VERSION 5.7 ;
  NOWIREEXTENSIONATPIN ON ;
  DIVIDERCHAR "/" ;
  BUSBITCHARS "[]" ;
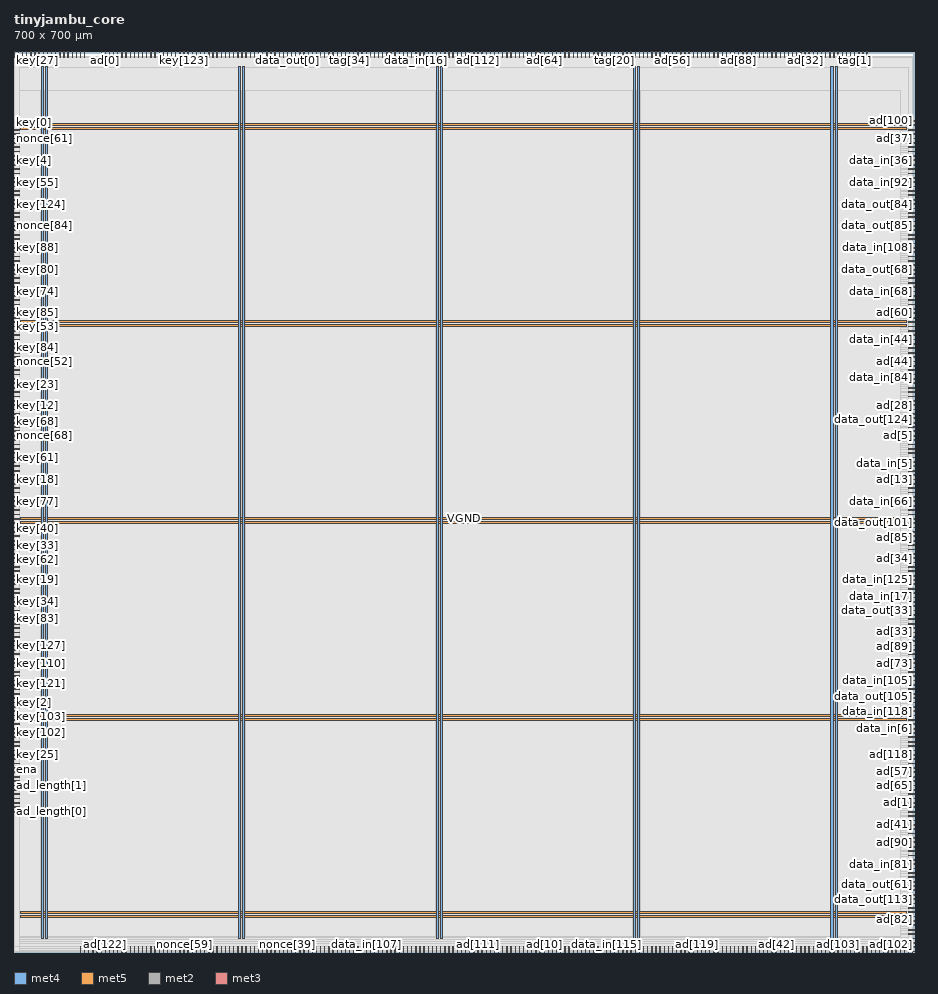
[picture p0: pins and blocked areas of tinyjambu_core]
MACRO tinyjambu_core
  CLASS BLOCK ;
  FOREIGN tinyjambu_core ;
  ORIGIN 0.000 0.000 ;
  SIZE 700.000 BY 700.000 ;
  PIN VGND
    DIRECTION INOUT ;
    USE GROUND ;
    PORT
      LAYER met4 ;
        RECT 24.340 10.640 25.940 688.400 ;
    END
    PORT
      LAYER met4 ;
        RECT 177.940 10.640 179.540 688.400 ;
    END
    PORT
      LAYER met4 ;
        RECT 331.540 10.640 333.140 688.400 ;
    END
    PORT
      LAYER met4 ;
        RECT 485.140 10.640 486.740 688.400 ;
    END
    PORT
      LAYER met4 ;
        RECT 638.740 10.640 640.340 688.400 ;
    END
    PORT
      LAYER met5 ;
        RECT 5.280 30.030 694.380 31.630 ;
    END
    PORT
      LAYER met5 ;
        RECT 5.280 183.210 694.380 184.810 ;
    END
    PORT
      LAYER met5 ;
        RECT 5.280 336.390 694.380 337.990 ;
    END
    PORT
      LAYER met5 ;
        RECT 5.280 489.570 694.380 491.170 ;
    END
    PORT
      LAYER met5 ;
        RECT 5.280 642.750 694.380 644.350 ;
    END
  END VGND
  PIN VPWR
    DIRECTION INOUT ;
    USE POWER ;
    PORT
      LAYER met4 ;
        RECT 21.040 10.640 22.640 688.400 ;
    END
    PORT
      LAYER met4 ;
        RECT 174.640 10.640 176.240 688.400 ;
    END
    PORT
      LAYER met4 ;
        RECT 328.240 10.640 329.840 688.400 ;
    END
    PORT
      LAYER met4 ;
        RECT 481.840 10.640 483.440 688.400 ;
    END
    PORT
      LAYER met4 ;
        RECT 635.440 10.640 637.040 688.400 ;
    END
    PORT
      LAYER met5 ;
        RECT 5.280 26.730 694.380 28.330 ;
    END
    PORT
      LAYER met5 ;
        RECT 5.280 179.910 694.380 181.510 ;
    END
    PORT
      LAYER met5 ;
        RECT 5.280 333.090 694.380 334.690 ;
    END
    PORT
      LAYER met5 ;
        RECT 5.280 486.270 694.380 487.870 ;
    END
    PORT
      LAYER met5 ;
        RECT 5.280 639.450 694.380 641.050 ;
    END
  END VPWR
  PIN ad[0]
    DIRECTION INPUT ;
    USE SIGNAL ;
    ANTENNAGATEAREA 0.213000 ;
    PORT
      LAYER met2 ;
        RECT 70.930 696.000 71.210 700.000 ;
    END
  END ad[0]
  PIN ad[100]
    DIRECTION INPUT ;
    USE SIGNAL ;
    ANTENNAGATEAREA 0.196500 ;
    PORT
      LAYER met3 ;
        RECT 696.000 646.040 700.000 646.640 ;
    END
  END ad[100]
  PIN ad[101]
    DIRECTION INPUT ;
    USE SIGNAL ;
    ANTENNAGATEAREA 0.196500 ;
    PORT
      LAYER met3 ;
        RECT 696.000 326.440 700.000 327.040 ;
    END
  END ad[101]
  PIN ad[102]
    DIRECTION INPUT ;
    USE SIGNAL ;
    ANTENNAGATEAREA 0.196500 ;
    PORT
      LAYER met2 ;
        RECT 685.950 0.000 686.230 4.000 ;
    END
  END ad[102]
  PIN ad[103]
    DIRECTION INPUT ;
    USE SIGNAL ;
    ANTENNAGATEAREA 0.213000 ;
    PORT
      LAYER met2 ;
        RECT 640.870 0.000 641.150 4.000 ;
    END
  END ad[103]
  PIN ad[104]
    DIRECTION INPUT ;
    USE SIGNAL ;
    ANTENNAGATEAREA 0.213000 ;
    PORT
      LAYER met2 ;
        RECT 663.410 696.000 663.690 700.000 ;
    END
  END ad[104]
  PIN ad[105]
    DIRECTION INPUT ;
    USE SIGNAL ;
    ANTENNAGATEAREA 0.213000 ;
    PORT
      LAYER met3 ;
        RECT 696.000 0.040 700.000 0.640 ;
    END
  END ad[105]
  PIN ad[106]
    DIRECTION INPUT ;
    USE SIGNAL ;
    ANTENNAGATEAREA 0.126000 ;
    PORT
      LAYER met3 ;
        RECT 696.000 71.440 700.000 72.040 ;
    END
  END ad[106]
  PIN ad[107]
    DIRECTION INPUT ;
    USE SIGNAL ;
    ANTENNAGATEAREA 0.213000 ;
    PORT
      LAYER met2 ;
        RECT 51.610 0.000 51.890 4.000 ;
    END
  END ad[107]
  PIN ad[108]
    DIRECTION INPUT ;
    USE SIGNAL ;
    ANTENNAGATEAREA 0.196500 ;
    PORT
      LAYER met3 ;
        RECT 696.000 618.840 700.000 619.440 ;
    END
  END ad[108]
  PIN ad[109]
    DIRECTION INPUT ;
    USE SIGNAL ;
    ANTENNAGATEAREA 0.196500 ;
    PORT
      LAYER met3 ;
        RECT 696.000 319.640 700.000 320.240 ;
    END
  END ad[109]
  PIN ad[10]
    DIRECTION INPUT ;
    USE SIGNAL ;
    ANTENNAGATEAREA 0.126000 ;
    PORT
      LAYER met2 ;
        RECT 412.250 0.000 412.530 4.000 ;
    END
  END ad[10]
  PIN ad[110]
    DIRECTION INPUT ;
    USE SIGNAL ;
    ANTENNAGATEAREA 0.196500 ;
    PORT
      LAYER met2 ;
        RECT 695.610 0.000 695.890 4.000 ;
    END
  END ad[110]
  PIN ad[111]
    DIRECTION INPUT ;
    USE SIGNAL ;
    ANTENNAGATEAREA 0.196500 ;
    PORT
      LAYER met2 ;
        RECT 360.730 0.000 361.010 4.000 ;
    END
  END ad[111]
  PIN ad[112]
    DIRECTION INPUT ;
    USE SIGNAL ;
    ANTENNAGATEAREA 0.196500 ;
    PORT
      LAYER met2 ;
        RECT 360.730 696.000 361.010 700.000 ;
    END
  END ad[112]
  PIN ad[113]
    DIRECTION INPUT ;
    USE SIGNAL ;
    ANTENNAGATEAREA 0.196500 ;
    PORT
      LAYER met3 ;
        RECT 696.000 295.840 700.000 296.440 ;
    END
  END ad[113]
  PIN ad[114]
    DIRECTION INPUT ;
    USE SIGNAL ;
    ANTENNAGATEAREA 0.196500 ;
    PORT
      LAYER met3 ;
        RECT 696.000 397.840 700.000 398.440 ;
    END
  END ad[114]
  PIN ad[115]
    DIRECTION INPUT ;
    USE SIGNAL ;
    ANTENNAGATEAREA 0.196500 ;
    PORT
      LAYER met2 ;
        RECT 621.550 0.000 621.830 4.000 ;
    END
  END ad[115]
  PIN ad[116]
    DIRECTION INPUT ;
    USE SIGNAL ;
    ANTENNAGATEAREA 0.126000 ;
    PORT
      LAYER met3 ;
        RECT 696.000 411.440 700.000 412.040 ;
    END
  END ad[116]
  PIN ad[117]
    DIRECTION INPUT ;
    USE SIGNAL ;
    ANTENNAGATEAREA 0.196500 ;
    PORT
      LAYER met3 ;
        RECT 696.000 520.240 700.000 520.840 ;
    END
  END ad[117]
  PIN ad[118]
    DIRECTION INPUT ;
    USE SIGNAL ;
    ANTENNAGATEAREA 0.196500 ;
    PORT
      LAYER met3 ;
        RECT 696.000 153.040 700.000 153.640 ;
    END
  END ad[118]
  PIN ad[119]
    DIRECTION INPUT ;
    USE SIGNAL ;
    ANTENNAGATEAREA 0.196500 ;
    PORT
      LAYER met2 ;
        RECT 531.390 0.000 531.670 4.000 ;
    END
  END ad[119]
  PIN ad[11]
    DIRECTION INPUT ;
    USE SIGNAL ;
    ANTENNAGATEAREA 0.213000 ;
    PORT
      LAYER met2 ;
        RECT 74.150 0.000 74.430 4.000 ;
    END
  END ad[11]
  PIN ad[120]
    DIRECTION INPUT ;
    USE SIGNAL ;
    ANTENNAGATEAREA 0.196500 ;
    PORT
      LAYER met2 ;
        RECT 370.390 696.000 370.670 700.000 ;
    END
  END ad[120]
  PIN ad[121]
    DIRECTION INPUT ;
    USE SIGNAL ;
    ANTENNAGATEAREA 0.196500 ;
    PORT
      LAYER met3 ;
        RECT 696.000 105.440 700.000 106.040 ;
    END
  END ad[121]
  PIN ad[122]
    DIRECTION INPUT ;
    USE SIGNAL ;
    ANTENNAGATEAREA 0.213000 ;
    PORT
      LAYER met2 ;
        RECT 70.930 0.000 71.210 4.000 ;
    END
  END ad[122]
  PIN ad[123]
    DIRECTION INPUT ;
    USE SIGNAL ;
    ANTENNAGATEAREA 0.213000 ;
    PORT
      LAYER met2 ;
        RECT 54.830 0.000 55.110 4.000 ;
    END
  END ad[123]
  PIN ad[124]
    DIRECTION INPUT ;
    USE SIGNAL ;
    ANTENNAGATEAREA 0.196500 ;
    PORT
      LAYER met3 ;
        RECT 696.000 612.040 700.000 612.640 ;
    END
  END ad[124]
  PIN ad[125]
    DIRECTION INPUT ;
    USE SIGNAL ;
    ANTENNAGATEAREA 0.196500 ;
    PORT
      LAYER met3 ;
        RECT 696.000 47.640 700.000 48.240 ;
    END
  END ad[125]
  PIN ad[126]
    DIRECTION INPUT ;
    USE SIGNAL ;
    ANTENNAGATEAREA 0.196500 ;
    PORT
      LAYER met2 ;
        RECT 518.510 0.000 518.790 4.000 ;
    END
  END ad[126]
  PIN ad[127]
    DIRECTION INPUT ;
    USE SIGNAL ;
    ANTENNAGATEAREA 0.196500 ;
    PORT
      LAYER met2 ;
        RECT 634.430 0.000 634.710 4.000 ;
    END
  END ad[127]
  PIN ad[12]
    DIRECTION INPUT ;
    USE SIGNAL ;
    ANTENNAGATEAREA 0.196500 ;
    PORT
      LAYER met3 ;
        RECT 696.000 571.240 700.000 571.840 ;
    END
  END ad[12]
  PIN ad[13]
    DIRECTION INPUT ;
    USE SIGNAL ;
    ANTENNAGATEAREA 0.196500 ;
    PORT
      LAYER met3 ;
        RECT 696.000 367.240 700.000 367.840 ;
    END
  END ad[13]
  PIN ad[14]
    DIRECTION INPUT ;
    USE SIGNAL ;
    ANTENNAGATEAREA 0.196500 ;
    PORT
      LAYER met2 ;
        RECT 666.630 0.000 666.910 4.000 ;
    END
  END ad[14]
  PIN ad[15]
    DIRECTION INPUT ;
    USE SIGNAL ;
    ANTENNAGATEAREA 0.196500 ;
    PORT
      LAYER met2 ;
        RECT 370.390 0.000 370.670 4.000 ;
    END
  END ad[15]
  PIN ad[16]
    DIRECTION INPUT ;
    USE SIGNAL ;
    ANTENNAGATEAREA 0.213000 ;
    PORT
      LAYER met2 ;
        RECT 83.810 696.000 84.090 700.000 ;
    END
  END ad[16]
  PIN ad[17]
    DIRECTION INPUT ;
    USE SIGNAL ;
    ANTENNAGATEAREA 0.196500 ;
    PORT
      LAYER met3 ;
        RECT 696.000 88.440 700.000 89.040 ;
    END
  END ad[17]
  PIN ad[18]
    DIRECTION INPUT ;
    USE SIGNAL ;
    ANTENNAGATEAREA 0.196500 ;
    PORT
      LAYER met3 ;
        RECT 696.000 6.840 700.000 7.440 ;
    END
  END ad[18]
  PIN ad[19]
    DIRECTION INPUT ;
    USE SIGNAL ;
    ANTENNAGATEAREA 0.196500 ;
    PORT
      LAYER met2 ;
        RECT 544.270 0.000 544.550 4.000 ;
    END
  END ad[19]
  PIN ad[1]
    DIRECTION INPUT ;
    USE SIGNAL ;
    ANTENNAGATEAREA 0.196500 ;
    PORT
      LAYER met3 ;
        RECT 696.000 115.640 700.000 116.240 ;
    END
  END ad[1]
  PIN ad[20]
    DIRECTION INPUT ;
    USE SIGNAL ;
    ANTENNAGATEAREA 0.196500 ;
    PORT
      LAYER met3 ;
        RECT 696.000 496.440 700.000 497.040 ;
    END
  END ad[20]
  PIN ad[21]
    DIRECTION INPUT ;
    USE SIGNAL ;
    ANTENNAGATEAREA 0.213000 ;
    PORT
      LAYER met3 ;
        RECT 696.000 601.840 700.000 602.440 ;
    END
  END ad[21]
  PIN ad[22]
    DIRECTION INPUT ;
    USE SIGNAL ;
    ANTENNAGATEAREA 0.196500 ;
    PORT
      LAYER met2 ;
        RECT 647.310 0.000 647.590 4.000 ;
    END
  END ad[22]
  PIN ad[23]
    DIRECTION INPUT ;
    USE SIGNAL ;
    ANTENNAGATEAREA 0.213000 ;
    PORT
      LAYER met2 ;
        RECT 637.650 0.000 637.930 4.000 ;
    END
  END ad[23]
  PIN ad[24]
    DIRECTION INPUT ;
    USE SIGNAL ;
    ANTENNAGATEAREA 0.196500 ;
    PORT
      LAYER met2 ;
        RECT 608.670 696.000 608.950 700.000 ;
    END
  END ad[24]
  PIN ad[25]
    DIRECTION INPUT ;
    USE SIGNAL ;
    ANTENNAGATEAREA 0.196500 ;
    PORT
      LAYER met3 ;
        RECT 696.000 95.240 700.000 95.840 ;
    END
  END ad[25]
  PIN ad[26]
    DIRECTION INPUT ;
    USE SIGNAL ;
    ANTENNAGATEAREA 0.213000 ;
    PORT
      LAYER met2 ;
        RECT 93.470 0.000 93.750 4.000 ;
    END
  END ad[26]
  PIN ad[27]
    DIRECTION INPUT ;
    USE SIGNAL ;
    ANTENNAGATEAREA 0.196500 ;
    PORT
      LAYER met2 ;
        RECT 415.470 0.000 415.750 4.000 ;
    END
  END ad[27]
  PIN ad[28]
    DIRECTION INPUT ;
    USE SIGNAL ;
    ANTENNAGATEAREA 0.196500 ;
    PORT
      LAYER met3 ;
        RECT 696.000 425.040 700.000 425.640 ;
    END
  END ad[28]
  PIN ad[29]
    DIRECTION INPUT ;
    USE SIGNAL ;
    ANTENNAGATEAREA 0.213000 ;
    PORT
      LAYER met3 ;
        RECT 696.000 622.240 700.000 622.840 ;
    END
  END ad[29]
  PIN ad[2]
    DIRECTION INPUT ;
    USE SIGNAL ;
    ANTENNAGATEAREA 0.213000 ;
    PORT
      LAYER met2 ;
        RECT 67.710 0.000 67.990 4.000 ;
    END
  END ad[2]
  PIN ad[30]
    DIRECTION INPUT ;
    USE SIGNAL ;
    ANTENNAGATEAREA 0.196500 ;
    PORT
      LAYER met2 ;
        RECT 692.390 0.000 692.670 4.000 ;
    END
  END ad[30]
  PIN ad[31]
    DIRECTION INPUT ;
    USE SIGNAL ;
    ANTENNAGATEAREA 0.159000 ;
    PORT
      LAYER met2 ;
        RECT 64.490 0.000 64.770 4.000 ;
    END
  END ad[31]
  PIN ad[32]
    DIRECTION INPUT ;
    USE SIGNAL ;
    ANTENNAGATEAREA 0.196500 ;
    PORT
      LAYER met2 ;
        RECT 615.110 696.000 615.390 700.000 ;
    END
  END ad[32]
  PIN ad[33]
    DIRECTION INPUT ;
    USE SIGNAL ;
    ANTENNAGATEAREA 0.196500 ;
    PORT
      LAYER met3 ;
        RECT 696.000 255.040 700.000 255.640 ;
    END
  END ad[33]
  PIN ad[34]
    DIRECTION INPUT ;
    USE SIGNAL ;
    ANTENNAGATEAREA 0.196500 ;
    PORT
      LAYER met3 ;
        RECT 696.000 306.040 700.000 306.640 ;
    END
  END ad[34]
  PIN ad[35]
    DIRECTION INPUT ;
    USE SIGNAL ;
    ANTENNAGATEAREA 0.196500 ;
    PORT
      LAYER met2 ;
        RECT 418.690 0.000 418.970 4.000 ;
    END
  END ad[35]
  PIN ad[36]
    DIRECTION INPUT ;
    USE SIGNAL ;
    ANTENNAGATEAREA 0.196500 ;
    PORT
      LAYER met3 ;
        RECT 696.000 510.040 700.000 510.640 ;
    END
  END ad[36]
  PIN ad[37]
    DIRECTION INPUT ;
    USE SIGNAL ;
    ANTENNAGATEAREA 0.213000 ;
    PORT
      LAYER met3 ;
        RECT 696.000 632.440 700.000 633.040 ;
    END
  END ad[37]
  PIN ad[38]
    DIRECTION INPUT ;
    USE SIGNAL ;
    ANTENNAGATEAREA 0.196500 ;
    PORT
      LAYER met2 ;
        RECT 679.510 0.000 679.790 4.000 ;
    END
  END ad[38]
  PIN ad[39]
    DIRECTION INPUT ;
    USE SIGNAL ;
    ANTENNAGATEAREA 0.196500 ;
    PORT
      LAYER met2 ;
        RECT 405.810 0.000 406.090 4.000 ;
    END
  END ad[39]
  PIN ad[3]
    DIRECTION INPUT ;
    USE SIGNAL ;
    ANTENNAGATEAREA 0.196500 ;
    PORT
      LAYER met2 ;
        RECT 483.090 0.000 483.370 4.000 ;
    END
  END ad[3]
  PIN ad[40]
    DIRECTION INPUT ;
    USE SIGNAL ;
    ANTENNAGATEAREA 0.196500 ;
    PORT
      LAYER met2 ;
        RECT 499.190 696.000 499.470 700.000 ;
    END
  END ad[40]
  PIN ad[41]
    DIRECTION INPUT ;
    USE SIGNAL ;
    ANTENNAGATEAREA 0.196500 ;
    PORT
      LAYER met3 ;
        RECT 696.000 98.640 700.000 99.240 ;
    END
  END ad[41]
  PIN ad[42]
    DIRECTION INPUT ;
    USE SIGNAL ;
    ANTENNAGATEAREA 0.196500 ;
    PORT
      LAYER met2 ;
        RECT 592.570 0.000 592.850 4.000 ;
    END
  END ad[42]
  PIN ad[43]
    DIRECTION INPUT ;
    USE SIGNAL ;
    ANTENNAGATEAREA 0.196500 ;
    PORT
      LAYER met2 ;
        RECT 367.170 0.000 367.450 4.000 ;
    END
  END ad[43]
  PIN ad[44]
    DIRECTION INPUT ;
    USE SIGNAL ;
    ANTENNAGATEAREA 0.196500 ;
    PORT
      LAYER met3 ;
        RECT 696.000 459.040 700.000 459.640 ;
    END
  END ad[44]
  PIN ad[45]
    DIRECTION INPUT ;
    USE SIGNAL ;
    ANTENNAGATEAREA 0.196500 ;
    PORT
      LAYER met3 ;
        RECT 696.000 421.640 700.000 422.240 ;
    END
  END ad[45]
  PIN ad[46]
    DIRECTION INPUT ;
    USE SIGNAL ;
    ANTENNAGATEAREA 0.196500 ;
    PORT
      LAYER met2 ;
        RECT 663.410 0.000 663.690 4.000 ;
    END
  END ad[46]
  PIN ad[47]
    DIRECTION INPUT ;
    USE SIGNAL ;
    ANTENNAGATEAREA 0.213000 ;
    PORT
      LAYER met2 ;
        RECT 103.130 0.000 103.410 4.000 ;
    END
  END ad[47]
  PIN ad[48]
    DIRECTION INPUT ;
    USE SIGNAL ;
    ANTENNAGATEAREA 0.126000 ;
    PORT
      LAYER met2 ;
        RECT 90.250 696.000 90.530 700.000 ;
    END
  END ad[48]
  PIN ad[49]
    DIRECTION INPUT ;
    USE SIGNAL ;
    ANTENNAGATEAREA 0.196500 ;
    PORT
      LAYER met3 ;
        RECT 696.000 108.840 700.000 109.440 ;
    END
  END ad[49]
  PIN ad[4]
    DIRECTION INPUT ;
    USE SIGNAL ;
    ANTENNAGATEAREA 0.196500 ;
    PORT
      LAYER met3 ;
        RECT 696.000 465.840 700.000 466.440 ;
    END
  END ad[4]
  PIN ad[50]
    DIRECTION INPUT ;
    USE SIGNAL ;
    ANTENNAGATEAREA 0.196500 ;
    PORT
      LAYER met3 ;
        RECT 696.000 360.440 700.000 361.040 ;
    END
  END ad[50]
  PIN ad[51]
    DIRECTION INPUT ;
    USE SIGNAL ;
    ANTENNAGATEAREA 0.196500 ;
    PORT
      LAYER met2 ;
        RECT 557.150 0.000 557.430 4.000 ;
    END
  END ad[51]
  PIN ad[52]
    DIRECTION INPUT ;
    USE SIGNAL ;
    ANTENNAGATEAREA 0.196500 ;
    PORT
      LAYER met3 ;
        RECT 696.000 462.440 700.000 463.040 ;
    END
  END ad[52]
  PIN ad[53]
    DIRECTION INPUT ;
    USE SIGNAL ;
    ANTENNAGATEAREA 0.213000 ;
    PORT
      LAYER met3 ;
        RECT 696.000 629.040 700.000 629.640 ;
    END
  END ad[53]
  PIN ad[54]
    DIRECTION INPUT ;
    USE SIGNAL ;
    ANTENNAGATEAREA 0.196500 ;
    PORT
      LAYER met2 ;
        RECT 673.070 0.000 673.350 4.000 ;
    END
  END ad[54]
  PIN ad[55]
    DIRECTION INPUT ;
    USE SIGNAL ;
    ANTENNAGATEAREA 0.196500 ;
    PORT
      LAYER met2 ;
        RECT 521.730 0.000 522.010 4.000 ;
    END
  END ad[55]
  PIN ad[56]
    DIRECTION INPUT ;
    USE SIGNAL ;
    ANTENNAGATEAREA 0.196500 ;
    PORT
      LAYER met2 ;
        RECT 512.070 696.000 512.350 700.000 ;
    END
  END ad[56]
  PIN ad[57]
    DIRECTION INPUT ;
    USE SIGNAL ;
    ANTENNAGATEAREA 0.196500 ;
    PORT
      LAYER met3 ;
        RECT 696.000 146.240 700.000 146.840 ;
    END
  END ad[57]
  PIN ad[58]
    DIRECTION INPUT ;
    USE SIGNAL ;
    ANTENNAGATEAREA 0.213000 ;
    PORT
      LAYER met3 ;
        RECT 696.000 292.440 700.000 293.040 ;
    END
  END ad[58]
  PIN ad[59]
    DIRECTION INPUT ;
    USE SIGNAL ;
    ANTENNAGATEAREA 0.196500 ;
    PORT
      LAYER met2 ;
        RECT 302.770 0.000 303.050 4.000 ;
    END
  END ad[59]
  PIN ad[5]
    DIRECTION INPUT ;
    USE SIGNAL ;
    ANTENNAGATEAREA 0.196500 ;
    PORT
      LAYER met3 ;
        RECT 696.000 401.240 700.000 401.840 ;
    END
  END ad[5]
  PIN ad[60]
    DIRECTION INPUT ;
    USE SIGNAL ;
    ANTENNAGATEAREA 0.196500 ;
    PORT
      LAYER met3 ;
        RECT 696.000 503.240 700.000 503.840 ;
    END
  END ad[60]
  PIN ad[61]
    DIRECTION INPUT ;
    USE SIGNAL ;
    ANTENNAGATEAREA 0.196500 ;
    PORT
      LAYER met3 ;
        RECT 696.000 414.840 700.000 415.440 ;
    END
  END ad[61]
  PIN ad[62]
    DIRECTION INPUT ;
    USE SIGNAL ;
    ANTENNAGATEAREA 0.196500 ;
    PORT
      LAYER met2 ;
        RECT 698.830 0.000 699.110 4.000 ;
    END
  END ad[62]
  PIN ad[63]
    DIRECTION INPUT ;
    USE SIGNAL ;
    ANTENNAGATEAREA 0.196500 ;
    PORT
      LAYER met2 ;
        RECT 470.210 0.000 470.490 4.000 ;
    END
  END ad[63]
  PIN ad[64]
    DIRECTION INPUT ;
    USE SIGNAL ;
    ANTENNAGATEAREA 0.196500 ;
    PORT
      LAYER met2 ;
        RECT 412.250 696.000 412.530 700.000 ;
    END
  END ad[64]
  PIN ad[65]
    DIRECTION INPUT ;
    USE SIGNAL ;
    ANTENNAGATEAREA 0.196500 ;
    PORT
      LAYER met3 ;
        RECT 696.000 129.240 700.000 129.840 ;
    END
  END ad[65]
  PIN ad[66]
    DIRECTION INPUT ;
    USE SIGNAL ;
    ANTENNAGATEAREA 0.196500 ;
    PORT
      LAYER met3 ;
        RECT 696.000 336.640 700.000 337.240 ;
    END
  END ad[66]
  PIN ad[67]
    DIRECTION INPUT ;
    USE SIGNAL ;
    ANTENNAGATEAREA 0.126000 ;
    PORT
      LAYER met2 ;
        RECT 624.770 0.000 625.050 4.000 ;
    END
  END ad[67]
  PIN ad[68]
    DIRECTION INPUT ;
    USE SIGNAL ;
    ANTENNAGATEAREA 0.196500 ;
    PORT
      LAYER met3 ;
        RECT 696.000 537.240 700.000 537.840 ;
    END
  END ad[68]
  PIN ad[69]
    DIRECTION INPUT ;
    USE SIGNAL ;
    ANTENNAGATEAREA 0.196500 ;
    PORT
      LAYER met3 ;
        RECT 696.000 363.840 700.000 364.440 ;
    END
  END ad[69]
  PIN ad[6]
    DIRECTION INPUT ;
    USE SIGNAL ;
    ANTENNAGATEAREA 0.196500 ;
    PORT
      LAYER met2 ;
        RECT 689.170 0.000 689.450 4.000 ;
    END
  END ad[6]
  PIN ad[70]
    DIRECTION INPUT ;
    USE SIGNAL ;
    ANTENNAGATEAREA 0.196500 ;
    PORT
      LAYER met2 ;
        RECT 656.970 0.000 657.250 4.000 ;
    END
  END ad[70]
  PIN ad[71]
    DIRECTION INPUT ;
    USE SIGNAL ;
    ANTENNAGATEAREA 0.196500 ;
    PORT
      LAYER met2 ;
        RECT 512.070 0.000 512.350 4.000 ;
    END
  END ad[71]
  PIN ad[72]
    DIRECTION INPUT ;
    USE SIGNAL ;
    ANTENNAGATEAREA 0.196500 ;
    PORT
      LAYER met2 ;
        RECT 418.690 696.000 418.970 700.000 ;
    END
  END ad[72]
  PIN ad[73]
    DIRECTION INPUT ;
    USE SIGNAL ;
    ANTENNAGATEAREA 0.196500 ;
    PORT
      LAYER met3 ;
        RECT 696.000 224.440 700.000 225.040 ;
    END
  END ad[73]
  PIN ad[74]
    DIRECTION INPUT ;
    USE SIGNAL ;
    ANTENNAGATEAREA 0.196500 ;
    PORT
      LAYER met3 ;
        RECT 696.000 54.440 700.000 55.040 ;
    END
  END ad[74]
  PIN ad[75]
    DIRECTION INPUT ;
    USE SIGNAL ;
    ANTENNAGATEAREA 0.196500 ;
    PORT
      LAYER met2 ;
        RECT 421.910 0.000 422.190 4.000 ;
    END
  END ad[75]
  PIN ad[76]
    DIRECTION INPUT ;
    USE SIGNAL ;
    ANTENNAGATEAREA 0.196500 ;
    PORT
      LAYER met3 ;
        RECT 696.000 482.840 700.000 483.440 ;
    END
  END ad[76]
  PIN ad[77]
    DIRECTION INPUT ;
    USE SIGNAL ;
    ANTENNAGATEAREA 0.159000 ;
    PORT
      LAYER met3 ;
        RECT 696.000 10.240 700.000 10.840 ;
    END
  END ad[77]
  PIN ad[78]
    DIRECTION INPUT ;
    USE SIGNAL ;
    ANTENNAGATEAREA 0.196500 ;
    PORT
      LAYER met2 ;
        RECT 653.750 0.000 654.030 4.000 ;
    END
  END ad[78]
  PIN ad[79]
    DIRECTION INPUT ;
    USE SIGNAL ;
    ANTENNAGATEAREA 0.196500 ;
    PORT
      LAYER met2 ;
        RECT 357.510 0.000 357.790 4.000 ;
    END
  END ad[79]
  PIN ad[7]
    DIRECTION INPUT ;
    USE SIGNAL ;
    ANTENNAGATEAREA 0.159000 ;
    PORT
      LAYER met2 ;
        RECT 61.270 0.000 61.550 4.000 ;
    END
  END ad[7]
  PIN ad[80]
    DIRECTION INPUT ;
    USE SIGNAL ;
    ANTENNAGATEAREA 0.126000 ;
    PORT
      LAYER met2 ;
        RECT 389.710 696.000 389.990 700.000 ;
    END
  END ad[80]
  PIN ad[81]
    DIRECTION INPUT ;
    USE SIGNAL ;
    ANTENNAGATEAREA 0.196500 ;
    PORT
      LAYER met3 ;
        RECT 696.000 125.840 700.000 126.440 ;
    END
  END ad[81]
  PIN ad[82]
    DIRECTION INPUT ;
    USE SIGNAL ;
    ANTENNAGATEAREA 0.196500 ;
    PORT
      LAYER met3 ;
        RECT 696.000 30.640 700.000 31.240 ;
    END
  END ad[82]
  PIN ad[83]
    DIRECTION INPUT ;
    USE SIGNAL ;
    ANTENNAGATEAREA 0.196500 ;
    PORT
      LAYER met2 ;
        RECT 570.030 0.000 570.310 4.000 ;
    END
  END ad[83]
  PIN ad[84]
    DIRECTION INPUT ;
    USE SIGNAL ;
    ANTENNAGATEAREA 0.196500 ;
    PORT
      LAYER met3 ;
        RECT 696.000 642.640 700.000 643.240 ;
    END
  END ad[84]
  PIN ad[85]
    DIRECTION INPUT ;
    USE SIGNAL ;
    ANTENNAGATEAREA 0.196500 ;
    PORT
      LAYER met3 ;
        RECT 696.000 316.240 700.000 316.840 ;
    END
  END ad[85]
  PIN ad[86]
    DIRECTION INPUT ;
    USE SIGNAL ;
    ANTENNAGATEAREA 0.196500 ;
    PORT
      LAYER met2 ;
        RECT 644.090 0.000 644.370 4.000 ;
    END
  END ad[86]
  PIN ad[87]
    DIRECTION INPUT ;
    USE SIGNAL ;
    ANTENNAGATEAREA 0.196500 ;
    PORT
      LAYER met2 ;
        RECT 576.470 0.000 576.750 4.000 ;
    END
  END ad[87]
  PIN ad[88]
    DIRECTION INPUT ;
    USE SIGNAL ;
    ANTENNAGATEAREA 0.126000 ;
    PORT
      LAYER met2 ;
        RECT 563.590 696.000 563.870 700.000 ;
    END
  END ad[88]
  PIN ad[89]
    DIRECTION INPUT ;
    USE SIGNAL ;
    ANTENNAGATEAREA 0.196500 ;
    PORT
      LAYER met3 ;
        RECT 696.000 231.240 700.000 231.840 ;
    END
  END ad[89]
  PIN ad[8]
    DIRECTION INPUT ;
    USE SIGNAL ;
    ANTENNAGATEAREA 0.196500 ;
    PORT
      LAYER met2 ;
        RECT 573.250 696.000 573.530 700.000 ;
    END
  END ad[8]
  PIN ad[90]
    DIRECTION INPUT ;
    USE SIGNAL ;
    ANTENNAGATEAREA 0.196500 ;
    PORT
      LAYER met3 ;
        RECT 696.000 85.040 700.000 85.640 ;
    END
  END ad[90]
  PIN ad[91]
    DIRECTION INPUT ;
    USE SIGNAL ;
    ANTENNAGATEAREA 0.196500 ;
    PORT
      LAYER met2 ;
        RECT 541.050 0.000 541.330 4.000 ;
    END
  END ad[91]
  PIN ad[92]
    DIRECTION INPUT ;
    USE SIGNAL ;
    ANTENNAGATEAREA 0.196500 ;
    PORT
      LAYER met3 ;
        RECT 696.000 428.440 700.000 429.040 ;
    END
  END ad[92]
  PIN ad[93]
    DIRECTION INPUT ;
    USE SIGNAL ;
    ANTENNAGATEAREA 0.159000 ;
    PORT
      LAYER met3 ;
        RECT 696.000 23.840 700.000 24.440 ;
    END
  END ad[93]
  PIN ad[94]
    DIRECTION INPUT ;
    USE SIGNAL ;
    ANTENNAGATEAREA 0.196500 ;
    PORT
      LAYER met2 ;
        RECT 650.530 0.000 650.810 4.000 ;
    END
  END ad[94]
  PIN ad[95]
    DIRECTION INPUT ;
    USE SIGNAL ;
    ANTENNAGATEAREA 0.159000 ;
    PORT
      LAYER met2 ;
        RECT 58.050 0.000 58.330 4.000 ;
    END
  END ad[95]
  PIN ad[96]
    DIRECTION INPUT ;
    USE SIGNAL ;
    ANTENNAGATEAREA 0.196500 ;
    PORT
      LAYER met2 ;
        RECT 579.690 696.000 579.970 700.000 ;
    END
  END ad[96]
  PIN ad[97]
    DIRECTION INPUT ;
    USE SIGNAL ;
    ANTENNAGATEAREA 0.196500 ;
    PORT
      LAYER met3 ;
        RECT 696.000 112.240 700.000 112.840 ;
    END
  END ad[97]
  PIN ad[98]
    DIRECTION INPUT ;
    USE SIGNAL ;
    ANTENNAGATEAREA 0.196500 ;
    PORT
      LAYER met3 ;
        RECT 696.000 380.840 700.000 381.440 ;
    END
  END ad[98]
  PIN ad[99]
    DIRECTION INPUT ;
    USE SIGNAL ;
    ANTENNAGATEAREA 0.196500 ;
    PORT
      LAYER met2 ;
        RECT 489.530 0.000 489.810 4.000 ;
    END
  END ad[99]
  PIN ad[9]
    DIRECTION INPUT ;
    USE SIGNAL ;
    ANTENNAGATEAREA 0.196500 ;
    PORT
      LAYER met3 ;
        RECT 696.000 221.040 700.000 221.640 ;
    END
  END ad[9]
  PIN ad_length[0]
    DIRECTION INPUT ;
    USE SIGNAL ;
    ANTENNAGATEAREA 0.247500 ;
    PORT
      LAYER met3 ;
        RECT 0.000 108.840 4.000 109.440 ;
    END
  END ad_length[0]
  PIN ad_length[1]
    DIRECTION INPUT ;
    USE SIGNAL ;
    ANTENNAGATEAREA 0.247500 ;
    PORT
      LAYER met3 ;
        RECT 0.000 129.240 4.000 129.840 ;
    END
  END ad_length[1]
  PIN ad_length[2]
    DIRECTION INPUT ;
    USE SIGNAL ;
    ANTENNAGATEAREA 0.426000 ;
    PORT
      LAYER met3 ;
        RECT 696.000 479.440 700.000 480.040 ;
    END
  END ad_length[2]
  PIN ad_length[3]
    DIRECTION INPUT ;
    USE SIGNAL ;
    ANTENNAGATEAREA 0.213000 ;
    PORT
      LAYER met2 ;
        RECT 322.090 0.000 322.370 4.000 ;
    END
  END ad_length[3]
  PIN ad_length[4]
    DIRECTION INPUT ;
    USE SIGNAL ;
    ANTENNAGATEAREA 0.213000 ;
    PORT
      LAYER met2 ;
        RECT 328.530 0.000 328.810 4.000 ;
    END
  END ad_length[4]
  PIN clk
    DIRECTION INPUT ;
    USE SIGNAL ;
    ANTENNAGATEAREA 0.852000 ;
    PORT
      LAYER met2 ;
        RECT 67.710 696.000 67.990 700.000 ;
    END
  END clk
  PIN data_in[0]
    DIRECTION INPUT ;
    USE SIGNAL ;
    ANTENNAGATEAREA 0.196500 ;
    PORT
      LAYER met2 ;
        RECT 248.030 696.000 248.310 700.000 ;
    END
  END data_in[0]
  PIN data_in[100]
    DIRECTION INPUT ;
    USE SIGNAL ;
    ANTENNAGATEAREA 0.196500 ;
    PORT
      LAYER met3 ;
        RECT 696.000 523.640 700.000 524.240 ;
    END
  END data_in[100]
  PIN data_in[101]
    DIRECTION INPUT ;
    USE SIGNAL ;
    ANTENNAGATEAREA 0.213000 ;
    PORT
      LAYER met3 ;
        RECT 696.000 567.840 700.000 568.440 ;
    END
  END data_in[101]
  PIN data_in[102]
    DIRECTION INPUT ;
    USE SIGNAL ;
    ANTENNAGATEAREA 0.196500 ;
    PORT
      LAYER met2 ;
        RECT 669.850 0.000 670.130 4.000 ;
    END
  END data_in[102]
  PIN data_in[103]
    DIRECTION INPUT ;
    USE SIGNAL ;
    ANTENNAGATEAREA 0.196500 ;
    PORT
      LAYER met2 ;
        RECT 447.670 0.000 447.950 4.000 ;
    END
  END data_in[103]
  PIN data_in[104]
    DIRECTION INPUT ;
    USE SIGNAL ;
    ANTENNAGATEAREA 0.196500 ;
    PORT
      LAYER met2 ;
        RECT 495.970 696.000 496.250 700.000 ;
    END
  END data_in[104]
  PIN data_in[105]
    DIRECTION INPUT ;
    USE SIGNAL ;
    ANTENNAGATEAREA 0.196500 ;
    PORT
      LAYER met3 ;
        RECT 696.000 210.840 700.000 211.440 ;
    END
  END data_in[105]
  PIN data_in[106]
    DIRECTION INPUT ;
    USE SIGNAL ;
    ANTENNAGATEAREA 0.196500 ;
    PORT
      LAYER met3 ;
        RECT 696.000 81.640 700.000 82.240 ;
    END
  END data_in[106]
  PIN data_in[107]
    DIRECTION INPUT ;
    USE SIGNAL ;
    ANTENNAGATEAREA 0.196500 ;
    PORT
      LAYER met2 ;
        RECT 273.790 0.000 274.070 4.000 ;
    END
  END data_in[107]
  PIN data_in[108]
    DIRECTION INPUT ;
    USE SIGNAL ;
    ANTENNAGATEAREA 0.196500 ;
    PORT
      LAYER met3 ;
        RECT 696.000 547.440 700.000 548.040 ;
    END
  END data_in[108]
  PIN data_in[109]
    DIRECTION INPUT ;
    USE SIGNAL ;
    ANTENNAGATEAREA 0.213000 ;
    PORT
      LAYER met3 ;
        RECT 696.000 3.440 700.000 4.040 ;
    END
  END data_in[109]
  PIN data_in[10]
    DIRECTION INPUT ;
    USE SIGNAL ;
    ANTENNAGATEAREA 0.196500 ;
    PORT
      LAYER met2 ;
        RECT 586.130 0.000 586.410 4.000 ;
    END
  END data_in[10]
  PIN data_in[110]
    DIRECTION INPUT ;
    USE SIGNAL ;
    ANTENNAGATEAREA 0.196500 ;
    PORT
      LAYER met2 ;
        RECT 682.730 0.000 683.010 4.000 ;
    END
  END data_in[110]
  PIN data_in[111]
    DIRECTION INPUT ;
    USE SIGNAL ;
    ANTENNAGATEAREA 0.196500 ;
    PORT
      LAYER met2 ;
        RECT 351.070 0.000 351.350 4.000 ;
    END
  END data_in[111]
  PIN data_in[112]
    DIRECTION INPUT ;
    USE SIGNAL ;
    ANTENNAGATEAREA 0.159000 ;
    PORT
      LAYER met2 ;
        RECT 80.590 696.000 80.870 700.000 ;
    END
  END data_in[112]
  PIN data_in[113]
    DIRECTION INPUT ;
    USE SIGNAL ;
    ANTENNAGATEAREA 0.126000 ;
    PORT
      LAYER met3 ;
        RECT 696.000 302.640 700.000 303.240 ;
    END
  END data_in[113]
  PIN data_in[114]
    DIRECTION INPUT ;
    USE SIGNAL ;
    ANTENNAGATEAREA 0.196500 ;
    PORT
      LAYER met3 ;
        RECT 696.000 370.640 700.000 371.240 ;
    END
  END data_in[114]
  PIN data_in[115]
    DIRECTION INPUT ;
    USE SIGNAL ;
    ANTENNAGATEAREA 0.196500 ;
    PORT
      LAYER met2 ;
        RECT 460.550 0.000 460.830 4.000 ;
    END
  END data_in[115]
  PIN data_in[116]
    DIRECTION INPUT ;
    USE SIGNAL ;
    ANTENNAGATEAREA 0.196500 ;
    PORT
      LAYER met3 ;
        RECT 696.000 544.040 700.000 544.640 ;
    END
  END data_in[116]
  PIN data_in[117]
    DIRECTION INPUT ;
    USE SIGNAL ;
    ANTENNAGATEAREA 0.213000 ;
    PORT
      LAYER met3 ;
        RECT 696.000 595.040 700.000 595.640 ;
    END
  END data_in[117]
  PIN data_in[118]
    DIRECTION INPUT ;
    USE SIGNAL ;
    ANTENNAGATEAREA 0.196500 ;
    PORT
      LAYER met3 ;
        RECT 696.000 187.040 700.000 187.640 ;
    END
  END data_in[118]
  PIN data_in[119]
    DIRECTION INPUT ;
    USE SIGNAL ;
    ANTENNAGATEAREA 0.126000 ;
    PORT
      LAYER met2 ;
        RECT 615.110 0.000 615.390 4.000 ;
    END
  END data_in[119]
  PIN data_in[11]
    DIRECTION INPUT ;
    USE SIGNAL ;
    ANTENNAGATEAREA 0.196500 ;
    PORT
      LAYER met2 ;
        RECT 344.630 0.000 344.910 4.000 ;
    END
  END data_in[11]
  PIN data_in[120]
    DIRECTION INPUT ;
    USE SIGNAL ;
    ANTENNAGATEAREA 0.126000 ;
    PORT
      LAYER met2 ;
        RECT 650.530 696.000 650.810 700.000 ;
    END
  END data_in[120]
  PIN data_in[121]
    DIRECTION INPUT ;
    USE SIGNAL ;
    ANTENNAGATEAREA 0.196500 ;
    PORT
      LAYER met3 ;
        RECT 696.000 248.240 700.000 248.840 ;
    END
  END data_in[121]
  PIN data_in[122]
    DIRECTION INPUT ;
    USE SIGNAL ;
    ANTENNAGATEAREA 0.196500 ;
    PORT
      LAYER met2 ;
        RECT 383.270 0.000 383.550 4.000 ;
    END
  END data_in[122]
  PIN data_in[123]
    DIRECTION INPUT ;
    USE SIGNAL ;
    ANTENNAGATEAREA 0.196500 ;
    PORT
      LAYER met2 ;
        RECT 409.030 0.000 409.310 4.000 ;
    END
  END data_in[123]
  PIN data_in[124]
    DIRECTION INPUT ;
    USE SIGNAL ;
    ANTENNAGATEAREA 0.196500 ;
    PORT
      LAYER met3 ;
        RECT 696.000 561.040 700.000 561.640 ;
    END
  END data_in[124]
  PIN data_in[125]
    DIRECTION INPUT ;
    USE SIGNAL ;
    ANTENNAGATEAREA 0.213000 ;
    PORT
      LAYER met3 ;
        RECT 696.000 289.040 700.000 289.640 ;
    END
  END data_in[125]
  PIN data_in[126]
    DIRECTION INPUT ;
    USE SIGNAL ;
    ANTENNAGATEAREA 0.196500 ;
    PORT
      LAYER met3 ;
        RECT 696.000 183.640 700.000 184.240 ;
    END
  END data_in[126]
  PIN data_in[127]
    DIRECTION INPUT ;
    USE SIGNAL ;
    ANTENNAGATEAREA 0.196500 ;
    PORT
      LAYER met2 ;
        RECT 602.230 0.000 602.510 4.000 ;
    END
  END data_in[127]
  PIN data_in[12]
    DIRECTION INPUT ;
    USE SIGNAL ;
    ANTENNAGATEAREA 0.196500 ;
    PORT
      LAYER met3 ;
        RECT 696.000 493.040 700.000 493.640 ;
    END
  END data_in[12]
  PIN data_in[13]
    DIRECTION INPUT ;
    USE SIGNAL ;
    ANTENNAGATEAREA 0.213000 ;
    PORT
      LAYER met3 ;
        RECT 696.000 574.640 700.000 575.240 ;
    END
  END data_in[13]
  PIN data_in[14]
    DIRECTION INPUT ;
    USE SIGNAL ;
    ANTENNAGATEAREA 0.196500 ;
    PORT
      LAYER met2 ;
        RECT 676.290 0.000 676.570 4.000 ;
    END
  END data_in[14]
  PIN data_in[15]
    DIRECTION INPUT ;
    USE SIGNAL ;
    ANTENNAGATEAREA 0.213000 ;
    PORT
      LAYER met2 ;
        RECT 87.030 0.000 87.310 4.000 ;
    END
  END data_in[15]
  PIN data_in[16]
    DIRECTION INPUT ;
    USE SIGNAL ;
    ANTENNAGATEAREA 0.196500 ;
    PORT
      LAYER met2 ;
        RECT 312.430 696.000 312.710 700.000 ;
    END
  END data_in[16]
  PIN data_in[17]
    DIRECTION INPUT ;
    USE SIGNAL ;
    ANTENNAGATEAREA 0.126000 ;
    PORT
      LAYER met3 ;
        RECT 696.000 282.240 700.000 282.840 ;
    END
  END data_in[17]
  PIN data_in[18]
    DIRECTION INPUT ;
    USE SIGNAL ;
    ANTENNAGATEAREA 0.196500 ;
    PORT
      LAYER met3 ;
        RECT 696.000 323.040 700.000 323.640 ;
    END
  END data_in[18]
  PIN data_in[19]
    DIRECTION INPUT ;
    USE SIGNAL ;
    ANTENNAGATEAREA 0.196500 ;
    PORT
      LAYER met2 ;
        RECT 595.790 0.000 596.070 4.000 ;
    END
  END data_in[19]
  PIN data_in[1]
    DIRECTION INPUT ;
    USE SIGNAL ;
    ANTENNAGATEAREA 0.196500 ;
    PORT
      LAYER met3 ;
        RECT 696.000 244.840 700.000 245.440 ;
    END
  END data_in[1]
  PIN data_in[20]
    DIRECTION INPUT ;
    USE SIGNAL ;
    ANTENNAGATEAREA 0.196500 ;
    PORT
      LAYER met3 ;
        RECT 696.000 550.840 700.000 551.440 ;
    END
  END data_in[20]
  PIN data_in[21]
    DIRECTION INPUT ;
    USE SIGNAL ;
    ANTENNAGATEAREA 0.213000 ;
    PORT
      LAYER met3 ;
        RECT 696.000 635.840 700.000 636.440 ;
    END
  END data_in[21]
  PIN data_in[22]
    DIRECTION INPUT ;
    USE SIGNAL ;
    ANTENNAGATEAREA 0.196500 ;
    PORT
      LAYER met2 ;
        RECT 660.190 0.000 660.470 4.000 ;
    END
  END data_in[22]
  PIN data_in[23]
    DIRECTION INPUT ;
    USE SIGNAL ;
    ANTENNAGATEAREA 0.196500 ;
    PORT
      LAYER met2 ;
        RECT 454.110 0.000 454.390 4.000 ;
    END
  END data_in[23]
  PIN data_in[24]
    DIRECTION INPUT ;
    USE SIGNAL ;
    ANTENNAGATEAREA 0.196500 ;
    PORT
      LAYER met2 ;
        RECT 611.890 696.000 612.170 700.000 ;
    END
  END data_in[24]
  PIN data_in[25]
    DIRECTION INPUT ;
    USE SIGNAL ;
    ANTENNAGATEAREA 0.196500 ;
    PORT
      LAYER met3 ;
        RECT 696.000 258.440 700.000 259.040 ;
    END
  END data_in[25]
  PIN data_in[26]
    DIRECTION INPUT ;
    USE SIGNAL ;
    ANTENNAGATEAREA 0.196500 ;
    PORT
      LAYER met2 ;
        RECT 286.670 0.000 286.950 4.000 ;
    END
  END data_in[26]
  PIN data_in[27]
    DIRECTION INPUT ;
    USE SIGNAL ;
    ANTENNAGATEAREA 0.196500 ;
    PORT
      LAYER met2 ;
        RECT 392.930 0.000 393.210 4.000 ;
    END
  END data_in[27]
  PIN data_in[28]
    DIRECTION INPUT ;
    USE SIGNAL ;
    ANTENNAGATEAREA 0.196500 ;
    PORT
      LAYER met3 ;
        RECT 696.000 557.640 700.000 558.240 ;
    END
  END data_in[28]
  PIN data_in[29]
    DIRECTION INPUT ;
    USE SIGNAL ;
    ANTENNAGATEAREA 0.196500 ;
    PORT
      LAYER met3 ;
        RECT 696.000 37.440 700.000 38.040 ;
    END
  END data_in[29]
  PIN data_in[2]
    DIRECTION INPUT ;
    USE SIGNAL ;
    ANTENNAGATEAREA 0.126000 ;
    PORT
      LAYER met2 ;
        RECT 90.250 0.000 90.530 4.000 ;
    END
  END data_in[2]
  PIN data_in[30]
    DIRECTION INPUT ;
    USE SIGNAL ;
    ANTENNAGATEAREA 0.196500 ;
    PORT
      LAYER met2 ;
        RECT 502.410 0.000 502.690 4.000 ;
    END
  END data_in[30]
  PIN data_in[31]
    DIRECTION INPUT ;
    USE SIGNAL ;
    ANTENNAGATEAREA 0.196500 ;
    PORT
      LAYER met2 ;
        RECT 283.450 0.000 283.730 4.000 ;
    END
  END data_in[31]
  PIN data_in[32]
    DIRECTION INPUT ;
    USE SIGNAL ;
    ANTENNAGATEAREA 0.196500 ;
    PORT
      LAYER met2 ;
        RECT 640.870 696.000 641.150 700.000 ;
    END
  END data_in[32]
  PIN data_in[33]
    DIRECTION INPUT ;
    USE SIGNAL ;
    ANTENNAGATEAREA 0.196500 ;
    PORT
      LAYER met3 ;
        RECT 696.000 261.840 700.000 262.440 ;
    END
  END data_in[33]
  PIN data_in[34]
    DIRECTION INPUT ;
    USE SIGNAL ;
    ANTENNAGATEAREA 0.196500 ;
    PORT
      LAYER met3 ;
        RECT 696.000 312.840 700.000 313.440 ;
    END
  END data_in[34]
  PIN data_in[35]
    DIRECTION INPUT ;
    USE SIGNAL ;
    ANTENNAGATEAREA 0.196500 ;
    PORT
      LAYER met2 ;
        RECT 386.490 0.000 386.770 4.000 ;
    END
  END data_in[35]
  PIN data_in[36]
    DIRECTION INPUT ;
    USE SIGNAL ;
    ANTENNAGATEAREA 0.196500 ;
    PORT
      LAYER met3 ;
        RECT 696.000 615.440 700.000 616.040 ;
    END
  END data_in[36]
  PIN data_in[37]
    DIRECTION INPUT ;
    USE SIGNAL ;
    ANTENNAGATEAREA 0.196500 ;
    PORT
      LAYER met3 ;
        RECT 696.000 431.840 700.000 432.440 ;
    END
  END data_in[37]
  PIN data_in[38]
    DIRECTION INPUT ;
    USE SIGNAL ;
    ANTENNAGATEAREA 0.196500 ;
    PORT
      LAYER met3 ;
        RECT 696.000 136.040 700.000 136.640 ;
    END
  END data_in[38]
  PIN data_in[39]
    DIRECTION INPUT ;
    USE SIGNAL ;
    ANTENNAGATEAREA 0.196500 ;
    PORT
      LAYER met2 ;
        RECT 373.610 0.000 373.890 4.000 ;
    END
  END data_in[39]
  PIN data_in[3]
    DIRECTION INPUT ;
    USE SIGNAL ;
    ANTENNAGATEAREA 0.196500 ;
    PORT
      LAYER met2 ;
        RECT 457.330 0.000 457.610 4.000 ;
    END
  END data_in[3]
  PIN data_in[40]
    DIRECTION INPUT ;
    USE SIGNAL ;
    ANTENNAGATEAREA 0.196500 ;
    PORT
      LAYER met2 ;
        RECT 444.450 696.000 444.730 700.000 ;
    END
  END data_in[40]
  PIN data_in[41]
    DIRECTION INPUT ;
    USE SIGNAL ;
    ANTENNAGATEAREA 0.196500 ;
    PORT
      LAYER met3 ;
        RECT 696.000 197.240 700.000 197.840 ;
    END
  END data_in[41]
  PIN data_in[42]
    DIRECTION INPUT ;
    USE SIGNAL ;
    ANTENNAGATEAREA 0.196500 ;
    PORT
      LAYER met2 ;
        RECT 589.350 0.000 589.630 4.000 ;
    END
  END data_in[42]
  PIN data_in[43]
    DIRECTION INPUT ;
    USE SIGNAL ;
    ANTENNAGATEAREA 0.213000 ;
    PORT
      LAYER met2 ;
        RECT 83.810 0.000 84.090 4.000 ;
    END
  END data_in[43]
  PIN data_in[44]
    DIRECTION INPUT ;
    USE SIGNAL ;
    ANTENNAGATEAREA 0.196500 ;
    PORT
      LAYER met3 ;
        RECT 696.000 476.040 700.000 476.640 ;
    END
  END data_in[44]
  PIN data_in[45]
    DIRECTION INPUT ;
    USE SIGNAL ;
    ANTENNAGATEAREA 0.213000 ;
    PORT
      LAYER met3 ;
        RECT 696.000 591.640 700.000 592.240 ;
    END
  END data_in[45]
  PIN data_in[46]
    DIRECTION INPUT ;
    USE SIGNAL ;
    ANTENNAGATEAREA 0.196500 ;
    PORT
      LAYER met3 ;
        RECT 696.000 119.040 700.000 119.640 ;
    END
  END data_in[46]
  PIN data_in[47]
    DIRECTION INPUT ;
    USE SIGNAL ;
    ANTENNAGATEAREA 0.196500 ;
    PORT
      LAYER met2 ;
        RECT 325.310 0.000 325.590 4.000 ;
    END
  END data_in[47]
  PIN data_in[48]
    DIRECTION INPUT ;
    USE SIGNAL ;
    ANTENNAGATEAREA 0.196500 ;
    PORT
      LAYER met2 ;
        RECT 116.010 696.000 116.290 700.000 ;
    END
  END data_in[48]
  PIN data_in[49]
    DIRECTION INPUT ;
    USE SIGNAL ;
    ANTENNAGATEAREA 0.196500 ;
    PORT
      LAYER met3 ;
        RECT 696.000 78.240 700.000 78.840 ;
    END
  END data_in[49]
  PIN data_in[4]
    DIRECTION INPUT ;
    USE SIGNAL ;
    ANTENNAGATEAREA 0.196500 ;
    PORT
      LAYER met3 ;
        RECT 696.000 533.840 700.000 534.440 ;
    END
  END data_in[4]
  PIN data_in[50]
    DIRECTION INPUT ;
    USE SIGNAL ;
    ANTENNAGATEAREA 0.213000 ;
    PORT
      LAYER met3 ;
        RECT 696.000 625.640 700.000 626.240 ;
    END
  END data_in[50]
  PIN data_in[51]
    DIRECTION INPUT ;
    USE SIGNAL ;
    ANTENNAGATEAREA 0.196500 ;
    PORT
      LAYER met2 ;
        RECT 479.870 0.000 480.150 4.000 ;
    END
  END data_in[51]
  PIN data_in[52]
    DIRECTION INPUT ;
    USE SIGNAL ;
    ANTENNAGATEAREA 0.196500 ;
    PORT
      LAYER met3 ;
        RECT 696.000 445.440 700.000 446.040 ;
    END
  END data_in[52]
  PIN data_in[53]
    DIRECTION INPUT ;
    USE SIGNAL ;
    ANTENNAGATEAREA 0.196500 ;
    PORT
      LAYER met3 ;
        RECT 696.000 394.440 700.000 395.040 ;
    END
  END data_in[53]
  PIN data_in[54]
    DIRECTION INPUT ;
    USE SIGNAL ;
    ANTENNAGATEAREA 0.196500 ;
    PORT
      LAYER met2 ;
        RECT 608.670 0.000 608.950 4.000 ;
    END
  END data_in[54]
  PIN data_in[55]
    DIRECTION INPUT ;
    USE SIGNAL ;
    ANTENNAGATEAREA 0.196500 ;
    PORT
      LAYER met2 ;
        RECT 450.890 0.000 451.170 4.000 ;
    END
  END data_in[55]
  PIN data_in[56]
    DIRECTION INPUT ;
    USE SIGNAL ;
    ANTENNAGATEAREA 0.196500 ;
    PORT
      LAYER met2 ;
        RECT 425.130 696.000 425.410 700.000 ;
    END
  END data_in[56]
  PIN data_in[57]
    DIRECTION INPUT ;
    USE SIGNAL ;
    ANTENNAGATEAREA 0.196500 ;
    PORT
      LAYER met3 ;
        RECT 696.000 149.640 700.000 150.240 ;
    END
  END data_in[57]
  PIN data_in[58]
    DIRECTION INPUT ;
    USE SIGNAL ;
    ANTENNAGATEAREA 0.196500 ;
    PORT
      LAYER met2 ;
        RECT 376.830 0.000 377.110 4.000 ;
    END
  END data_in[58]
  PIN data_in[59]
    DIRECTION INPUT ;
    USE SIGNAL ;
    ANTENNAGATEAREA 0.196500 ;
    PORT
      LAYER met2 ;
        RECT 338.190 0.000 338.470 4.000 ;
    END
  END data_in[59]
  PIN data_in[5]
    DIRECTION INPUT ;
    USE SIGNAL ;
    ANTENNAGATEAREA 0.196500 ;
    PORT
      LAYER met3 ;
        RECT 696.000 374.040 700.000 374.640 ;
    END
  END data_in[5]
  PIN data_in[60]
    DIRECTION INPUT ;
    USE SIGNAL ;
    ANTENNAGATEAREA 0.196500 ;
    PORT
      LAYER met3 ;
        RECT 696.000 605.240 700.000 605.840 ;
    END
  END data_in[60]
  PIN data_in[61]
    DIRECTION INPUT ;
    USE SIGNAL ;
    ANTENNAGATEAREA 0.196500 ;
    PORT
      LAYER met3 ;
        RECT 696.000 51.040 700.000 51.640 ;
    END
  END data_in[61]
  PIN data_in[62]
    DIRECTION INPUT ;
    USE SIGNAL ;
    ANTENNAGATEAREA 0.196500 ;
    PORT
      LAYER met2 ;
        RECT 505.630 0.000 505.910 4.000 ;
    END
  END data_in[62]
  PIN data_in[63]
    DIRECTION INPUT ;
    USE SIGNAL ;
    ANTENNAGATEAREA 0.196500 ;
    PORT
      LAYER met2 ;
        RECT 399.370 0.000 399.650 4.000 ;
    END
  END data_in[63]
  PIN data_in[64]
    DIRECTION INPUT ;
    USE SIGNAL ;
    ANTENNAGATEAREA 0.213000 ;
    PORT
      LAYER met2 ;
        RECT 560.370 696.000 560.650 700.000 ;
    END
  END data_in[64]
  PIN data_in[65]
    DIRECTION INPUT ;
    USE SIGNAL ;
    ANTENNAGATEAREA 0.196500 ;
    PORT
      LAYER met3 ;
        RECT 696.000 238.040 700.000 238.640 ;
    END
  END data_in[65]
  PIN data_in[66]
    DIRECTION INPUT ;
    USE SIGNAL ;
    ANTENNAGATEAREA 0.196500 ;
    PORT
      LAYER met3 ;
        RECT 696.000 350.240 700.000 350.840 ;
    END
  END data_in[66]
  PIN data_in[67]
    DIRECTION INPUT ;
    USE SIGNAL ;
    ANTENNAGATEAREA 0.196500 ;
    PORT
      LAYER met2 ;
        RECT 486.310 0.000 486.590 4.000 ;
    END
  END data_in[67]
  PIN data_in[68]
    DIRECTION INPUT ;
    USE SIGNAL ;
    ANTENNAGATEAREA 0.196500 ;
    PORT
      LAYER met3 ;
        RECT 696.000 513.440 700.000 514.040 ;
    END
  END data_in[68]
  PIN data_in[69]
    DIRECTION INPUT ;
    USE SIGNAL ;
    ANTENNAGATEAREA 0.196500 ;
    PORT
      LAYER met3 ;
        RECT 696.000 343.440 700.000 344.040 ;
    END
  END data_in[69]
  PIN data_in[6]
    DIRECTION INPUT ;
    USE SIGNAL ;
    ANTENNAGATEAREA 0.196500 ;
    PORT
      LAYER met3 ;
        RECT 696.000 173.440 700.000 174.040 ;
    END
  END data_in[6]
  PIN data_in[70]
    DIRECTION INPUT ;
    USE SIGNAL ;
    ANTENNAGATEAREA 0.196500 ;
    PORT
      LAYER met3 ;
        RECT 696.000 156.440 700.000 157.040 ;
    END
  END data_in[70]
  PIN data_in[71]
    DIRECTION INPUT ;
    USE SIGNAL ;
    ANTENNAGATEAREA 0.196500 ;
    PORT
      LAYER met2 ;
        RECT 441.230 0.000 441.510 4.000 ;
    END
  END data_in[71]
  PIN data_in[72]
    DIRECTION INPUT ;
    USE SIGNAL ;
    ANTENNAGATEAREA 0.196500 ;
    PORT
      LAYER met2 ;
        RECT 428.350 696.000 428.630 700.000 ;
    END
  END data_in[72]
  PIN data_in[73]
    DIRECTION INPUT ;
    USE SIGNAL ;
    ANTENNAGATEAREA 0.196500 ;
    PORT
      LAYER met3 ;
        RECT 696.000 190.440 700.000 191.040 ;
    END
  END data_in[73]
  PIN data_in[74]
    DIRECTION INPUT ;
    USE SIGNAL ;
    ANTENNAGATEAREA 0.196500 ;
    PORT
      LAYER met3 ;
        RECT 696.000 285.640 700.000 286.240 ;
    END
  END data_in[74]
  PIN data_in[75]
    DIRECTION INPUT ;
    USE SIGNAL ;
    ANTENNAGATEAREA 0.196500 ;
    PORT
      LAYER met2 ;
        RECT 434.790 0.000 435.070 4.000 ;
    END
  END data_in[75]
  PIN data_in[76]
    DIRECTION INPUT ;
    USE SIGNAL ;
    ANTENNAGATEAREA 0.196500 ;
    PORT
      LAYER met3 ;
        RECT 696.000 639.240 700.000 639.840 ;
    END
  END data_in[76]
  PIN data_in[77]
    DIRECTION INPUT ;
    USE SIGNAL ;
    ANTENNAGATEAREA 0.213000 ;
    PORT
      LAYER met3 ;
        RECT 696.000 20.440 700.000 21.040 ;
    END
  END data_in[77]
  PIN data_in[78]
    DIRECTION INPUT ;
    USE SIGNAL ;
    ANTENNAGATEAREA 0.196500 ;
    PORT
      LAYER met2 ;
        RECT 553.930 0.000 554.210 4.000 ;
    END
  END data_in[78]
  PIN data_in[79]
    DIRECTION INPUT ;
    USE SIGNAL ;
    ANTENNAGATEAREA 0.196500 ;
    PORT
      LAYER met2 ;
        RECT 293.110 0.000 293.390 4.000 ;
    END
  END data_in[79]
  PIN data_in[7]
    DIRECTION INPUT ;
    USE SIGNAL ;
    ANTENNAGATEAREA 0.196500 ;
    PORT
      LAYER met2 ;
        RECT 354.290 0.000 354.570 4.000 ;
    END
  END data_in[7]
  PIN data_in[80]
    DIRECTION INPUT ;
    USE SIGNAL ;
    ANTENNAGATEAREA 0.196500 ;
    PORT
      LAYER met2 ;
        RECT 380.050 696.000 380.330 700.000 ;
    END
  END data_in[80]
  PIN data_in[81]
    DIRECTION INPUT ;
    USE SIGNAL ;
    ANTENNAGATEAREA 0.196500 ;
    PORT
      LAYER met3 ;
        RECT 696.000 68.040 700.000 68.640 ;
    END
  END data_in[81]
  PIN data_in[82]
    DIRECTION INPUT ;
    USE SIGNAL ;
    ANTENNAGATEAREA 0.196500 ;
    PORT
      LAYER met3 ;
        RECT 696.000 17.040 700.000 17.640 ;
    END
  END data_in[82]
  PIN data_in[83]
    DIRECTION INPUT ;
    USE SIGNAL ;
    ANTENNAGATEAREA 0.196500 ;
    PORT
      LAYER met2 ;
        RECT 631.210 0.000 631.490 4.000 ;
    END
  END data_in[83]
  PIN data_in[84]
    DIRECTION INPUT ;
    USE SIGNAL ;
    ANTENNAGATEAREA 0.196500 ;
    PORT
      LAYER met3 ;
        RECT 696.000 452.240 700.000 452.840 ;
    END
  END data_in[84]
  PIN data_in[85]
    DIRECTION INPUT ;
    USE SIGNAL ;
    ANTENNAGATEAREA 0.196500 ;
    PORT
      LAYER met3 ;
        RECT 696.000 584.840 700.000 585.440 ;
    END
  END data_in[85]
  PIN data_in[86]
    DIRECTION INPUT ;
    USE SIGNAL ;
    ANTENNAGATEAREA 0.196500 ;
    PORT
      LAYER met3 ;
        RECT 696.000 166.640 700.000 167.240 ;
    END
  END data_in[86]
  PIN data_in[87]
    DIRECTION INPUT ;
    USE SIGNAL ;
    ANTENNAGATEAREA 0.196500 ;
    PORT
      LAYER met2 ;
        RECT 550.710 0.000 550.990 4.000 ;
    END
  END data_in[87]
  PIN data_in[88]
    DIRECTION INPUT ;
    USE SIGNAL ;
    ANTENNAGATEAREA 0.196500 ;
    PORT
      LAYER met2 ;
        RECT 553.930 696.000 554.210 700.000 ;
    END
  END data_in[88]
  PIN data_in[89]
    DIRECTION INPUT ;
    USE SIGNAL ;
    ANTENNAGATEAREA 0.196500 ;
    PORT
      LAYER met3 ;
        RECT 696.000 132.640 700.000 133.240 ;
    END
  END data_in[89]
  PIN data_in[8]
    DIRECTION INPUT ;
    USE SIGNAL ;
    ANTENNAGATEAREA 0.196500 ;
    PORT
      LAYER met2 ;
        RECT 402.590 696.000 402.870 700.000 ;
    END
  END data_in[8]
  PIN data_in[90]
    DIRECTION INPUT ;
    USE SIGNAL ;
    ANTENNAGATEAREA 0.196500 ;
    PORT
      LAYER met2 ;
        RECT 363.950 0.000 364.230 4.000 ;
    END
  END data_in[90]
  PIN data_in[91]
    DIRECTION INPUT ;
    USE SIGNAL ;
    ANTENNAGATEAREA 0.196500 ;
    PORT
      LAYER met2 ;
        RECT 402.590 0.000 402.870 4.000 ;
    END
  END data_in[91]
  PIN data_in[92]
    DIRECTION INPUT ;
    USE SIGNAL ;
    ANTENNAGATEAREA 0.196500 ;
    PORT
      LAYER met3 ;
        RECT 696.000 598.440 700.000 599.040 ;
    END
  END data_in[92]
  PIN data_in[93]
    DIRECTION INPUT ;
    USE SIGNAL ;
    ANTENNAGATEAREA 0.213000 ;
    PORT
      LAYER met3 ;
        RECT 696.000 34.040 700.000 34.640 ;
    END
  END data_in[93]
  PIN data_in[94]
    DIRECTION INPUT ;
    USE SIGNAL ;
    ANTENNAGATEAREA 0.196500 ;
    PORT
      LAYER met2 ;
        RECT 499.190 0.000 499.470 4.000 ;
    END
  END data_in[94]
  PIN data_in[95]
    DIRECTION INPUT ;
    USE SIGNAL ;
    ANTENNAGATEAREA 0.213000 ;
    PORT
      LAYER met2 ;
        RECT 106.350 0.000 106.630 4.000 ;
    END
  END data_in[95]
  PIN data_in[96]
    DIRECTION INPUT ;
    USE SIGNAL ;
    ANTENNAGATEAREA 0.213000 ;
    PORT
      LAYER met2 ;
        RECT 392.930 696.000 393.210 700.000 ;
    END
  END data_in[96]
  PIN data_in[97]
    DIRECTION INPUT ;
    USE SIGNAL ;
    ANTENNAGATEAREA 0.126000 ;
    PORT
      LAYER met3 ;
        RECT 696.000 91.840 700.000 92.440 ;
    END
  END data_in[97]
  PIN data_in[98]
    DIRECTION INPUT ;
    USE SIGNAL ;
    ANTENNAGATEAREA 0.196500 ;
    PORT
      LAYER met3 ;
        RECT 696.000 377.440 700.000 378.040 ;
    END
  END data_in[98]
  PIN data_in[99]
    DIRECTION INPUT ;
    USE SIGNAL ;
    ANTENNAGATEAREA 0.196500 ;
    PORT
      LAYER met2 ;
        RECT 547.490 0.000 547.770 4.000 ;
    END
  END data_in[99]
  PIN data_in[9]
    DIRECTION INPUT ;
    USE SIGNAL ;
    ANTENNAGATEAREA 0.196500 ;
    PORT
      LAYER met3 ;
        RECT 696.000 214.240 700.000 214.840 ;
    END
  END data_in[9]
  PIN data_length[0]
    DIRECTION INPUT ;
    USE SIGNAL ;
    ANTENNAGATEAREA 0.247500 ;
    PORT
      LAYER met3 ;
        RECT 0.000 285.640 4.000 286.240 ;
    END
  END data_length[0]
  PIN data_length[1]
    DIRECTION INPUT ;
    USE SIGNAL ;
    ANTENNAGATEAREA 0.247500 ;
    PORT
      LAYER met3 ;
        RECT 0.000 319.640 4.000 320.240 ;
    END
  END data_length[1]
  PIN data_length[2]
    DIRECTION INPUT ;
    USE SIGNAL ;
    ANTENNAGATEAREA 0.247500 ;
    PORT
      LAYER met3 ;
        RECT 696.000 384.240 700.000 384.840 ;
    END
  END data_length[2]
  PIN data_length[3]
    DIRECTION INPUT ;
    USE SIGNAL ;
    ANTENNAGATEAREA 0.213000 ;
    PORT
      LAYER met2 ;
        RECT 315.650 0.000 315.930 4.000 ;
    END
  END data_length[3]
  PIN data_length[4]
    DIRECTION INPUT ;
    USE SIGNAL ;
    ANTENNAGATEAREA 0.159000 ;
    PORT
      LAYER met2 ;
        RECT 296.330 0.000 296.610 4.000 ;
    END
  END data_length[4]
  PIN data_out[0]
    DIRECTION OUTPUT ;
    USE SIGNAL ;
    ANTENNADIFFAREA 0.445500 ;
    PORT
      LAYER met2 ;
        RECT 212.610 696.000 212.890 700.000 ;
    END
  END data_out[0]
  PIN data_out[100]
    DIRECTION OUTPUT ;
    USE SIGNAL ;
    ANTENNADIFFAREA 0.445500 ;
    PORT
      LAYER met3 ;
        RECT 696.000 527.040 700.000 527.640 ;
    END
  END data_out[100]
  PIN data_out[101]
    DIRECTION OUTPUT ;
    USE SIGNAL ;
    ANTENNADIFFAREA 0.445500 ;
    PORT
      LAYER met3 ;
        RECT 696.000 340.040 700.000 340.640 ;
    END
  END data_out[101]
  PIN data_out[102]
    DIRECTION OUTPUT ;
    USE SIGNAL ;
    ANTENNADIFFAREA 0.445500 ;
    PORT
      LAYER met3 ;
        RECT 696.000 176.840 700.000 177.440 ;
    END
  END data_out[102]
  PIN data_out[103]
    DIRECTION OUTPUT ;
    USE SIGNAL ;
    ANTENNADIFFAREA 0.445500 ;
    PORT
      LAYER met2 ;
        RECT 579.690 0.000 579.970 4.000 ;
    END
  END data_out[103]
  PIN data_out[104]
    DIRECTION OUTPUT ;
    USE SIGNAL ;
    ANTENNADIFFAREA 0.445500 ;
    PORT
      LAYER met2 ;
        RECT 486.310 696.000 486.590 700.000 ;
    END
  END data_out[104]
  PIN data_out[105]
    DIRECTION OUTPUT ;
    USE SIGNAL ;
    ANTENNADIFFAREA 0.445500 ;
    PORT
      LAYER met3 ;
        RECT 696.000 204.040 700.000 204.640 ;
    END
  END data_out[105]
  PIN data_out[106]
    DIRECTION OUTPUT ;
    USE SIGNAL ;
    ANTENNADIFFAREA 0.445500 ;
    PORT
      LAYER met3 ;
        RECT 696.000 272.040 700.000 272.640 ;
    END
  END data_out[106]
  PIN data_out[107]
    DIRECTION OUTPUT ;
    USE SIGNAL ;
    ANTENNADIFFAREA 0.445500 ;
    PORT
      LAYER met2 ;
        RECT 318.870 0.000 319.150 4.000 ;
    END
  END data_out[107]
  PIN data_out[108]
    DIRECTION OUTPUT ;
    USE SIGNAL ;
    ANTENNADIFFAREA 0.445500 ;
    PORT
      LAYER met3 ;
        RECT 696.000 486.240 700.000 486.840 ;
    END
  END data_out[108]
  PIN data_out[109]
    DIRECTION OUTPUT ;
    USE SIGNAL ;
    ANTENNADIFFAREA 0.445500 ;
    PORT
      LAYER met3 ;
        RECT 696.000 309.440 700.000 310.040 ;
    END
  END data_out[109]
  PIN data_out[10]
    DIRECTION OUTPUT ;
    USE SIGNAL ;
    ANTENNADIFFAREA 0.445500 ;
    PORT
      LAYER met2 ;
        RECT 560.370 0.000 560.650 4.000 ;
    END
  END data_out[10]
  PIN data_out[110]
    DIRECTION OUTPUT ;
    USE SIGNAL ;
    ANTENNADIFFAREA 0.445500 ;
    PORT
      LAYER met3 ;
        RECT 696.000 142.840 700.000 143.440 ;
    END
  END data_out[110]
  PIN data_out[111]
    DIRECTION OUTPUT ;
    USE SIGNAL ;
    ANTENNADIFFAREA 0.445500 ;
    PORT
      LAYER met2 ;
        RECT 312.430 0.000 312.710 4.000 ;
    END
  END data_out[111]
  PIN data_out[112]
    DIRECTION OUTPUT ;
    USE SIGNAL ;
    ANTENNADIFFAREA 0.445500 ;
    PORT
      LAYER met2 ;
        RECT 309.210 696.000 309.490 700.000 ;
    END
  END data_out[112]
  PIN data_out[113]
    DIRECTION OUTPUT ;
    USE SIGNAL ;
    ANTENNADIFFAREA 0.445500 ;
    PORT
      LAYER met3 ;
        RECT 696.000 40.840 700.000 41.440 ;
    END
  END data_out[113]
  PIN data_out[114]
    DIRECTION OUTPUT ;
    USE SIGNAL ;
    ANTENNADIFFAREA 0.445500 ;
    PORT
      LAYER met3 ;
        RECT 696.000 404.640 700.000 405.240 ;
    END
  END data_out[114]
  PIN data_out[115]
    DIRECTION OUTPUT ;
    USE SIGNAL ;
    ANTENNADIFFAREA 0.445500 ;
    PORT
      LAYER met2 ;
        RECT 534.610 0.000 534.890 4.000 ;
    END
  END data_out[115]
  PIN data_out[116]
    DIRECTION OUTPUT ;
    USE SIGNAL ;
    ANTENNADIFFAREA 0.445500 ;
    PORT
      LAYER met3 ;
        RECT 696.000 554.240 700.000 554.840 ;
    END
  END data_out[116]
  PIN data_out[117]
    DIRECTION OUTPUT ;
    USE SIGNAL ;
    ANTENNADIFFAREA 0.445500 ;
    PORT
      LAYER met3 ;
        RECT 696.000 391.040 700.000 391.640 ;
    END
  END data_out[117]
  PIN data_out[118]
    DIRECTION OUTPUT ;
    USE SIGNAL ;
    ANTENNADIFFAREA 0.445500 ;
    PORT
      LAYER met3 ;
        RECT 696.000 180.240 700.000 180.840 ;
    END
  END data_out[118]
  PIN data_out[119]
    DIRECTION OUTPUT ;
    USE SIGNAL ;
    ANTENNADIFFAREA 0.445500 ;
    PORT
      LAYER met2 ;
        RECT 444.450 0.000 444.730 4.000 ;
    END
  END data_out[119]
  PIN data_out[11]
    DIRECTION OUTPUT ;
    USE SIGNAL ;
    ANTENNADIFFAREA 0.445500 ;
    PORT
      LAYER met2 ;
        RECT 341.410 0.000 341.690 4.000 ;
    END
  END data_out[11]
  PIN data_out[120]
    DIRECTION OUTPUT ;
    USE SIGNAL ;
    ANTENNADIFFAREA 0.445500 ;
    PORT
      LAYER met2 ;
        RECT 660.190 696.000 660.470 700.000 ;
    END
  END data_out[120]
  PIN data_out[121]
    DIRECTION OUTPUT ;
    USE SIGNAL ;
    ANTENNADIFFAREA 0.445500 ;
    PORT
      LAYER met3 ;
        RECT 696.000 102.040 700.000 102.640 ;
    END
  END data_out[121]
  PIN data_out[122]
    DIRECTION OUTPUT ;
    USE SIGNAL ;
    ANTENNADIFFAREA 0.445500 ;
    PORT
      LAYER met2 ;
        RECT 96.690 0.000 96.970 4.000 ;
    END
  END data_out[122]
  PIN data_out[123]
    DIRECTION OUTPUT ;
    USE SIGNAL ;
    ANTENNADIFFAREA 0.445500 ;
    PORT
      LAYER met2 ;
        RECT 77.370 0.000 77.650 4.000 ;
    END
  END data_out[123]
  PIN data_out[124]
    DIRECTION OUTPUT ;
    USE SIGNAL ;
    ANTENNADIFFAREA 0.445500 ;
    PORT
      LAYER met3 ;
        RECT 696.000 408.040 700.000 408.640 ;
    END
  END data_out[124]
  PIN data_out[125]
    DIRECTION OUTPUT ;
    USE SIGNAL ;
    ANTENNADIFFAREA 0.445500 ;
    PORT
      LAYER met3 ;
        RECT 696.000 61.240 700.000 61.840 ;
    END
  END data_out[125]
  PIN data_out[126]
    DIRECTION OUTPUT ;
    USE SIGNAL ;
    ANTENNADIFFAREA 0.445500 ;
    PORT
      LAYER met2 ;
        RECT 495.970 0.000 496.250 4.000 ;
    END
  END data_out[126]
  PIN data_out[127]
    DIRECTION OUTPUT ;
    USE SIGNAL ;
    ANTENNADIFFAREA 0.445500 ;
    PORT
      LAYER met2 ;
        RECT 438.010 0.000 438.290 4.000 ;
    END
  END data_out[127]
  PIN data_out[12]
    DIRECTION OUTPUT ;
    USE SIGNAL ;
    ANTENNADIFFAREA 0.445500 ;
    PORT
      LAYER met3 ;
        RECT 696.000 540.640 700.000 541.240 ;
    END
  END data_out[12]
  PIN data_out[13]
    DIRECTION OUTPUT ;
    USE SIGNAL ;
    ANTENNADIFFAREA 0.445500 ;
    PORT
      LAYER met3 ;
        RECT 696.000 387.640 700.000 388.240 ;
    END
  END data_out[13]
  PIN data_out[14]
    DIRECTION OUTPUT ;
    USE SIGNAL ;
    ANTENNADIFFAREA 0.445500 ;
    PORT
      LAYER met2 ;
        RECT 524.950 0.000 525.230 4.000 ;
    END
  END data_out[14]
  PIN data_out[15]
    DIRECTION OUTPUT ;
    USE SIGNAL ;
    ANTENNADIFFAREA 0.445500 ;
    PORT
      LAYER met2 ;
        RECT 289.890 0.000 290.170 4.000 ;
    END
  END data_out[15]
  PIN data_out[16]
    DIRECTION OUTPUT ;
    USE SIGNAL ;
    ANTENNADIFFAREA 0.445500 ;
    PORT
      LAYER met2 ;
        RECT 289.890 696.000 290.170 700.000 ;
    END
  END data_out[16]
  PIN data_out[17]
    DIRECTION OUTPUT ;
    USE SIGNAL ;
    ANTENNADIFFAREA 0.445500 ;
    PORT
      LAYER met3 ;
        RECT 696.000 74.840 700.000 75.440 ;
    END
  END data_out[17]
  PIN data_out[18]
    DIRECTION OUTPUT ;
    USE SIGNAL ;
    ANTENNADIFFAREA 0.445500 ;
    PORT
      LAYER met3 ;
        RECT 696.000 333.240 700.000 333.840 ;
    END
  END data_out[18]
  PIN data_out[19]
    DIRECTION OUTPUT ;
    USE SIGNAL ;
    ANTENNADIFFAREA 0.445500 ;
    PORT
      LAYER met2 ;
        RECT 466.990 0.000 467.270 4.000 ;
    END
  END data_out[19]
  PIN data_out[1]
    DIRECTION OUTPUT ;
    USE SIGNAL ;
    ANTENNADIFFAREA 0.445500 ;
    PORT
      LAYER met3 ;
        RECT 696.000 241.440 700.000 242.040 ;
    END
  END data_out[1]
  PIN data_out[20]
    DIRECTION OUTPUT ;
    USE SIGNAL ;
    ANTENNADIFFAREA 0.445500 ;
    PORT
      LAYER met3 ;
        RECT 696.000 469.240 700.000 469.840 ;
    END
  END data_out[20]
  PIN data_out[21]
    DIRECTION OUTPUT ;
    USE SIGNAL ;
    ANTENNADIFFAREA 0.445500 ;
    PORT
      LAYER met3 ;
        RECT 696.000 438.640 700.000 439.240 ;
    END
  END data_out[21]
  PIN data_out[22]
    DIRECTION OUTPUT ;
    USE SIGNAL ;
    ANTENNADIFFAREA 0.445500 ;
    PORT
      LAYER met2 ;
        RECT 599.010 0.000 599.290 4.000 ;
    END
  END data_out[22]
  PIN data_out[23]
    DIRECTION OUTPUT ;
    USE SIGNAL ;
    ANTENNADIFFAREA 0.445500 ;
    PORT
      LAYER met2 ;
        RECT 473.430 0.000 473.710 4.000 ;
    END
  END data_out[23]
  PIN data_out[24]
    DIRECTION OUTPUT ;
    USE SIGNAL ;
    ANTENNADIFFAREA 0.445500 ;
    PORT
      LAYER met2 ;
        RECT 605.450 696.000 605.730 700.000 ;
    END
  END data_out[24]
  PIN data_out[25]
    DIRECTION OUTPUT ;
    USE SIGNAL ;
    ANTENNADIFFAREA 0.445500 ;
    PORT
      LAYER met3 ;
        RECT 696.000 251.640 700.000 252.240 ;
    END
  END data_out[25]
  PIN data_out[26]
    DIRECTION OUTPUT ;
    USE SIGNAL ;
    ANTENNADIFFAREA 0.445500 ;
    PORT
      LAYER met2 ;
        RECT 299.550 0.000 299.830 4.000 ;
    END
  END data_out[26]
  PIN data_out[27]
    DIRECTION OUTPUT ;
    USE SIGNAL ;
    ANTENNADIFFAREA 0.445500 ;
    PORT
      LAYER met2 ;
        RECT 396.150 0.000 396.430 4.000 ;
    END
  END data_out[27]
  PIN data_out[28]
    DIRECTION OUTPUT ;
    USE SIGNAL ;
    ANTENNADIFFAREA 0.445500 ;
    PORT
      LAYER met3 ;
        RECT 696.000 435.240 700.000 435.840 ;
    END
  END data_out[28]
  PIN data_out[29]
    DIRECTION OUTPUT ;
    USE SIGNAL ;
    ANTENNADIFFAREA 0.445500 ;
    PORT
      LAYER met3 ;
        RECT 696.000 44.240 700.000 44.840 ;
    END
  END data_out[29]
  PIN data_out[2]
    DIRECTION OUTPUT ;
    USE SIGNAL ;
    ANTENNADIFFAREA 0.445500 ;
    PORT
      LAYER met2 ;
        RECT 99.910 0.000 100.190 4.000 ;
    END
  END data_out[2]
  PIN data_out[30]
    DIRECTION OUTPUT ;
    USE SIGNAL ;
    ANTENNADIFFAREA 0.445500 ;
    PORT
      LAYER met2 ;
        RECT 492.750 0.000 493.030 4.000 ;
    END
  END data_out[30]
  PIN data_out[31]
    DIRECTION OUTPUT ;
    USE SIGNAL ;
    ANTENNADIFFAREA 0.445500 ;
    PORT
      LAYER met2 ;
        RECT 309.210 0.000 309.490 4.000 ;
    END
  END data_out[31]
  PIN data_out[32]
    DIRECTION OUTPUT ;
    USE SIGNAL ;
    ANTENNADIFFAREA 0.445500 ;
    PORT
      LAYER met2 ;
        RECT 637.650 696.000 637.930 700.000 ;
    END
  END data_out[32]
  PIN data_out[33]
    DIRECTION OUTPUT ;
    USE SIGNAL ;
    ANTENNADIFFAREA 0.445500 ;
    PORT
      LAYER met3 ;
        RECT 696.000 265.240 700.000 265.840 ;
    END
  END data_out[33]
  PIN data_out[34]
    DIRECTION OUTPUT ;
    USE SIGNAL ;
    ANTENNADIFFAREA 0.445500 ;
    PORT
      LAYER met3 ;
        RECT 696.000 329.840 700.000 330.440 ;
    END
  END data_out[34]
  PIN data_out[35]
    DIRECTION OUTPUT ;
    USE SIGNAL ;
    ANTENNADIFFAREA 0.445500 ;
    PORT
      LAYER met2 ;
        RECT 428.350 0.000 428.630 4.000 ;
    END
  END data_out[35]
  PIN data_out[36]
    DIRECTION OUTPUT ;
    USE SIGNAL ;
    ANTENNADIFFAREA 0.445500 ;
    PORT
      LAYER met3 ;
        RECT 696.000 489.640 700.000 490.240 ;
    END
  END data_out[36]
  PIN data_out[37]
    DIRECTION OUTPUT ;
    USE SIGNAL ;
    ANTENNADIFFAREA 0.445500 ;
    PORT
      LAYER met3 ;
        RECT 696.000 516.840 700.000 517.440 ;
    END
  END data_out[37]
  PIN data_out[38]
    DIRECTION OUTPUT ;
    USE SIGNAL ;
    ANTENNADIFFAREA 0.445500 ;
    PORT
      LAYER met3 ;
        RECT 696.000 139.440 700.000 140.040 ;
    END
  END data_out[38]
  PIN data_out[39]
    DIRECTION OUTPUT ;
    USE SIGNAL ;
    ANTENNADIFFAREA 0.445500 ;
    PORT
      LAYER met2 ;
        RECT 380.050 0.000 380.330 4.000 ;
    END
  END data_out[39]
  PIN data_out[3]
    DIRECTION OUTPUT ;
    USE SIGNAL ;
    ANTENNADIFFAREA 0.445500 ;
    PORT
      LAYER met2 ;
        RECT 566.810 0.000 567.090 4.000 ;
    END
  END data_out[3]
  PIN data_out[40]
    DIRECTION OUTPUT ;
    USE SIGNAL ;
    ANTENNADIFFAREA 0.445500 ;
    PORT
      LAYER met2 ;
        RECT 479.870 696.000 480.150 700.000 ;
    END
  END data_out[40]
  PIN data_out[41]
    DIRECTION OUTPUT ;
    USE SIGNAL ;
    ANTENNADIFFAREA 0.445500 ;
    PORT
      LAYER met3 ;
        RECT 696.000 200.640 700.000 201.240 ;
    END
  END data_out[41]
  PIN data_out[42]
    DIRECTION OUTPUT ;
    USE SIGNAL ;
    ANTENNADIFFAREA 0.445500 ;
    PORT
      LAYER met2 ;
        RECT 508.850 0.000 509.130 4.000 ;
    END
  END data_out[42]
  PIN data_out[43]
    DIRECTION OUTPUT ;
    USE SIGNAL ;
    ANTENNADIFFAREA 0.445500 ;
    PORT
      LAYER met2 ;
        RECT 280.230 0.000 280.510 4.000 ;
    END
  END data_out[43]
  PIN data_out[44]
    DIRECTION OUTPUT ;
    USE SIGNAL ;
    ANTENNADIFFAREA 0.445500 ;
    PORT
      LAYER met3 ;
        RECT 696.000 472.640 700.000 473.240 ;
    END
  END data_out[44]
  PIN data_out[45]
    DIRECTION OUTPUT ;
    USE SIGNAL ;
    ANTENNADIFFAREA 0.445500 ;
    PORT
      LAYER met3 ;
        RECT 696.000 357.040 700.000 357.640 ;
    END
  END data_out[45]
  PIN data_out[46]
    DIRECTION OUTPUT ;
    USE SIGNAL ;
    ANTENNADIFFAREA 0.445500 ;
    PORT
      LAYER met3 ;
        RECT 696.000 122.440 700.000 123.040 ;
    END
  END data_out[46]
  PIN data_out[47]
    DIRECTION OUTPUT ;
    USE SIGNAL ;
    ANTENNADIFFAREA 0.445500 ;
    PORT
      LAYER met2 ;
        RECT 334.970 0.000 335.250 4.000 ;
    END
  END data_out[47]
  PIN data_out[48]
    DIRECTION OUTPUT ;
    USE SIGNAL ;
    ANTENNADIFFAREA 0.445500 ;
    PORT
      LAYER met2 ;
        RECT 128.890 696.000 129.170 700.000 ;
    END
  END data_out[48]
  PIN data_out[49]
    DIRECTION OUTPUT ;
    USE SIGNAL ;
    ANTENNADIFFAREA 0.445500 ;
    PORT
      LAYER met3 ;
        RECT 696.000 278.840 700.000 279.440 ;
    END
  END data_out[49]
  PIN data_out[4]
    DIRECTION OUTPUT ;
    USE SIGNAL ;
    ANTENNADIFFAREA 0.445500 ;
    PORT
      LAYER met3 ;
        RECT 696.000 455.640 700.000 456.240 ;
    END
  END data_out[4]
  PIN data_out[50]
    DIRECTION OUTPUT ;
    USE SIGNAL ;
    ANTENNADIFFAREA 0.445500 ;
    PORT
      LAYER met3 ;
        RECT 696.000 353.640 700.000 354.240 ;
    END
  END data_out[50]
  PIN data_out[51]
    DIRECTION OUTPUT ;
    USE SIGNAL ;
    ANTENNADIFFAREA 0.445500 ;
    PORT
      LAYER met2 ;
        RECT 463.770 0.000 464.050 4.000 ;
    END
  END data_out[51]
  PIN data_out[52]
    DIRECTION OUTPUT ;
    USE SIGNAL ;
    ANTENNADIFFAREA 0.445500 ;
    PORT
      LAYER met3 ;
        RECT 696.000 442.040 700.000 442.640 ;
    END
  END data_out[52]
  PIN data_out[53]
    DIRECTION OUTPUT ;
    USE SIGNAL ;
    ANTENNADIFFAREA 0.445500 ;
    PORT
      LAYER met3 ;
        RECT 696.000 608.640 700.000 609.240 ;
    END
  END data_out[53]
  PIN data_out[54]
    DIRECTION OUTPUT ;
    USE SIGNAL ;
    ANTENNADIFFAREA 0.445500 ;
    PORT
      LAYER met2 ;
        RECT 573.250 0.000 573.530 4.000 ;
    END
  END data_out[54]
  PIN data_out[55]
    DIRECTION OUTPUT ;
    USE SIGNAL ;
    ANTENNADIFFAREA 0.445500 ;
    PORT
      LAYER met2 ;
        RECT 582.910 0.000 583.190 4.000 ;
    END
  END data_out[55]
  PIN data_out[56]
    DIRECTION OUTPUT ;
    USE SIGNAL ;
    ANTENNADIFFAREA 0.445500 ;
    PORT
      LAYER met2 ;
        RECT 508.850 696.000 509.130 700.000 ;
    END
  END data_out[56]
  PIN data_out[57]
    DIRECTION OUTPUT ;
    USE SIGNAL ;
    ANTENNADIFFAREA 0.445500 ;
    PORT
      LAYER met3 ;
        RECT 696.000 217.640 700.000 218.240 ;
    END
  END data_out[57]
  PIN data_out[58]
    DIRECTION OUTPUT ;
    USE SIGNAL ;
    ANTENNADIFFAREA 0.445500 ;
    PORT
      LAYER met2 ;
        RECT 389.710 0.000 389.990 4.000 ;
    END
  END data_out[58]
  PIN data_out[59]
    DIRECTION OUTPUT ;
    USE SIGNAL ;
    ANTENNADIFFAREA 0.445500 ;
    PORT
      LAYER met2 ;
        RECT 331.750 0.000 332.030 4.000 ;
    END
  END data_out[59]
  PIN data_out[5]
    DIRECTION OUTPUT ;
    USE SIGNAL ;
    ANTENNADIFFAREA 0.445500 ;
    PORT
      LAYER met3 ;
        RECT 696.000 588.240 700.000 588.840 ;
    END
  END data_out[5]
  PIN data_out[60]
    DIRECTION OUTPUT ;
    USE SIGNAL ;
    ANTENNADIFFAREA 0.445500 ;
    PORT
      LAYER met3 ;
        RECT 696.000 499.840 700.000 500.440 ;
    END
  END data_out[60]
  PIN data_out[61]
    DIRECTION OUTPUT ;
    USE SIGNAL ;
    ANTENNADIFFAREA 0.445500 ;
    PORT
      LAYER met3 ;
        RECT 696.000 57.840 700.000 58.440 ;
    END
  END data_out[61]
  PIN data_out[62]
    DIRECTION OUTPUT ;
    USE SIGNAL ;
    ANTENNADIFFAREA 0.445500 ;
    PORT
      LAYER met2 ;
        RECT 515.290 0.000 515.570 4.000 ;
    END
  END data_out[62]
  PIN data_out[63]
    DIRECTION OUTPUT ;
    USE SIGNAL ;
    ANTENNADIFFAREA 0.445500 ;
    PORT
      LAYER met2 ;
        RECT 627.990 0.000 628.270 4.000 ;
    END
  END data_out[63]
  PIN data_out[64]
    DIRECTION OUTPUT ;
    USE SIGNAL ;
    ANTENNADIFFAREA 0.445500 ;
    PORT
      LAYER met2 ;
        RECT 405.810 696.000 406.090 700.000 ;
    END
  END data_out[64]
  PIN data_out[65]
    DIRECTION OUTPUT ;
    USE SIGNAL ;
    ANTENNADIFFAREA 0.445500 ;
    PORT
      LAYER met3 ;
        RECT 696.000 234.640 700.000 235.240 ;
    END
  END data_out[65]
  PIN data_out[66]
    DIRECTION OUTPUT ;
    USE SIGNAL ;
    ANTENNADIFFAREA 0.445500 ;
    PORT
      LAYER met3 ;
        RECT 696.000 418.240 700.000 418.840 ;
    END
  END data_out[66]
  PIN data_out[67]
    DIRECTION OUTPUT ;
    USE SIGNAL ;
    ANTENNADIFFAREA 0.445500 ;
    PORT
      LAYER met2 ;
        RECT 618.330 0.000 618.610 4.000 ;
    END
  END data_out[67]
  PIN data_out[68]
    DIRECTION OUTPUT ;
    USE SIGNAL ;
    ANTENNADIFFAREA 0.445500 ;
    PORT
      LAYER met3 ;
        RECT 696.000 530.440 700.000 531.040 ;
    END
  END data_out[68]
  PIN data_out[69]
    DIRECTION OUTPUT ;
    USE SIGNAL ;
    ANTENNADIFFAREA 0.445500 ;
    PORT
      LAYER met3 ;
        RECT 696.000 578.040 700.000 578.640 ;
    END
  END data_out[69]
  PIN data_out[6]
    DIRECTION OUTPUT ;
    USE SIGNAL ;
    ANTENNADIFFAREA 0.445500 ;
    PORT
      LAYER met3 ;
        RECT 696.000 170.040 700.000 170.640 ;
    END
  END data_out[6]
  PIN data_out[70]
    DIRECTION OUTPUT ;
    USE SIGNAL ;
    ANTENNADIFFAREA 0.445500 ;
    PORT
      LAYER met3 ;
        RECT 696.000 163.240 700.000 163.840 ;
    END
  END data_out[70]
  PIN data_out[71]
    DIRECTION OUTPUT ;
    USE SIGNAL ;
    ANTENNADIFFAREA 0.445500 ;
    PORT
      LAYER met2 ;
        RECT 425.130 0.000 425.410 4.000 ;
    END
  END data_out[71]
  PIN data_out[72]
    DIRECTION OUTPUT ;
    USE SIGNAL ;
    ANTENNADIFFAREA 0.445500 ;
    PORT
      LAYER met2 ;
        RECT 505.630 696.000 505.910 700.000 ;
    END
  END data_out[72]
  PIN data_out[73]
    DIRECTION OUTPUT ;
    USE SIGNAL ;
    ANTENNADIFFAREA 0.445500 ;
    PORT
      LAYER met3 ;
        RECT 696.000 193.840 700.000 194.440 ;
    END
  END data_out[73]
  PIN data_out[74]
    DIRECTION OUTPUT ;
    USE SIGNAL ;
    ANTENNADIFFAREA 0.445500 ;
    PORT
      LAYER met3 ;
        RECT 696.000 275.440 700.000 276.040 ;
    END
  END data_out[74]
  PIN data_out[75]
    DIRECTION OUTPUT ;
    USE SIGNAL ;
    ANTENNADIFFAREA 0.445500 ;
    PORT
      LAYER met2 ;
        RECT 476.650 0.000 476.930 4.000 ;
    END
  END data_out[75]
  PIN data_out[76]
    DIRECTION OUTPUT ;
    USE SIGNAL ;
    ANTENNADIFFAREA 0.445500 ;
    PORT
      LAYER met3 ;
        RECT 696.000 506.640 700.000 507.240 ;
    END
  END data_out[76]
  PIN data_out[77]
    DIRECTION OUTPUT ;
    USE SIGNAL ;
    ANTENNADIFFAREA 0.445500 ;
    PORT
      LAYER met3 ;
        RECT 696.000 27.240 700.000 27.840 ;
    END
  END data_out[77]
  PIN data_out[78]
    DIRECTION OUTPUT ;
    USE SIGNAL ;
    ANTENNADIFFAREA 0.445500 ;
    PORT
      LAYER met2 ;
        RECT 563.590 0.000 563.870 4.000 ;
    END
  END data_out[78]
  PIN data_out[79]
    DIRECTION OUTPUT ;
    USE SIGNAL ;
    ANTENNADIFFAREA 0.445500 ;
    PORT
      LAYER met2 ;
        RECT 305.990 0.000 306.270 4.000 ;
    END
  END data_out[79]
  PIN data_out[7]
    DIRECTION OUTPUT ;
    USE SIGNAL ;
    ANTENNADIFFAREA 0.445500 ;
    PORT
      LAYER met2 ;
        RECT 277.010 0.000 277.290 4.000 ;
    END
  END data_out[7]
  PIN data_out[80]
    DIRECTION OUTPUT ;
    USE SIGNAL ;
    ANTENNADIFFAREA 0.445500 ;
    PORT
      LAYER met2 ;
        RECT 621.550 696.000 621.830 700.000 ;
    END
  END data_out[80]
  PIN data_out[81]
    DIRECTION OUTPUT ;
    USE SIGNAL ;
    ANTENNADIFFAREA 0.445500 ;
    PORT
      LAYER met3 ;
        RECT 696.000 64.640 700.000 65.240 ;
    END
  END data_out[81]
  PIN data_out[82]
    DIRECTION OUTPUT ;
    USE SIGNAL ;
    ANTENNADIFFAREA 0.445500 ;
    PORT
      LAYER met3 ;
        RECT 696.000 13.640 700.000 14.240 ;
    END
  END data_out[82]
  PIN data_out[83]
    DIRECTION OUTPUT ;
    USE SIGNAL ;
    ANTENNADIFFAREA 0.445500 ;
    PORT
      LAYER met2 ;
        RECT 528.170 0.000 528.450 4.000 ;
    END
  END data_out[83]
  PIN data_out[84]
    DIRECTION OUTPUT ;
    USE SIGNAL ;
    ANTENNADIFFAREA 0.445500 ;
    PORT
      LAYER met3 ;
        RECT 696.000 581.440 700.000 582.040 ;
    END
  END data_out[84]
  PIN data_out[85]
    DIRECTION OUTPUT ;
    USE SIGNAL ;
    ANTENNADIFFAREA 0.445500 ;
    PORT
      LAYER met3 ;
        RECT 696.000 564.440 700.000 565.040 ;
    END
  END data_out[85]
  PIN data_out[86]
    DIRECTION OUTPUT ;
    USE SIGNAL ;
    ANTENNADIFFAREA 0.445500 ;
    PORT
      LAYER met3 ;
        RECT 696.000 159.840 700.000 160.440 ;
    END
  END data_out[86]
  PIN data_out[87]
    DIRECTION OUTPUT ;
    USE SIGNAL ;
    ANTENNADIFFAREA 0.445500 ;
    PORT
      LAYER met2 ;
        RECT 605.450 0.000 605.730 4.000 ;
    END
  END data_out[87]
  PIN data_out[88]
    DIRECTION OUTPUT ;
    USE SIGNAL ;
    ANTENNADIFFAREA 0.445500 ;
    PORT
      LAYER met2 ;
        RECT 524.950 696.000 525.230 700.000 ;
    END
  END data_out[88]
  PIN data_out[89]
    DIRECTION OUTPUT ;
    USE SIGNAL ;
    ANTENNADIFFAREA 0.445500 ;
    PORT
      LAYER met3 ;
        RECT 696.000 227.840 700.000 228.440 ;
    END
  END data_out[89]
  PIN data_out[8]
    DIRECTION OUTPUT ;
    USE SIGNAL ;
    ANTENNADIFFAREA 0.445500 ;
    PORT
      LAYER met2 ;
        RECT 547.490 696.000 547.770 700.000 ;
    END
  END data_out[8]
  PIN data_out[90]
    DIRECTION OUTPUT ;
    USE SIGNAL ;
    ANTENNADIFFAREA 0.445500 ;
    PORT
      LAYER met2 ;
        RECT 80.590 0.000 80.870 4.000 ;
    END
  END data_out[90]
  PIN data_out[91]
    DIRECTION OUTPUT ;
    USE SIGNAL ;
    ANTENNADIFFAREA 0.445500 ;
    PORT
      LAYER met2 ;
        RECT 611.890 0.000 612.170 4.000 ;
    END
  END data_out[91]
  PIN data_out[92]
    DIRECTION OUTPUT ;
    USE SIGNAL ;
    ANTENNADIFFAREA 0.445500 ;
    PORT
      LAYER met3 ;
        RECT 696.000 448.840 700.000 449.440 ;
    END
  END data_out[92]
  PIN data_out[93]
    DIRECTION OUTPUT ;
    USE SIGNAL ;
    ANTENNADIFFAREA 0.445500 ;
    PORT
      LAYER met3 ;
        RECT 696.000 299.240 700.000 299.840 ;
    END
  END data_out[93]
  PIN data_out[94]
    DIRECTION OUTPUT ;
    USE SIGNAL ;
    ANTENNADIFFAREA 0.445500 ;
    PORT
      LAYER met2 ;
        RECT 537.830 0.000 538.110 4.000 ;
    END
  END data_out[94]
  PIN data_out[95]
    DIRECTION OUTPUT ;
    USE SIGNAL ;
    ANTENNADIFFAREA 0.445500 ;
    PORT
      LAYER met2 ;
        RECT 347.850 0.000 348.130 4.000 ;
    END
  END data_out[95]
  PIN data_out[96]
    DIRECTION OUTPUT ;
    USE SIGNAL ;
    ANTENNADIFFAREA 0.445500 ;
    PORT
      LAYER met2 ;
        RECT 592.570 696.000 592.850 700.000 ;
    END
  END data_out[96]
  PIN data_out[97]
    DIRECTION OUTPUT ;
    USE SIGNAL ;
    ANTENNADIFFAREA 0.445500 ;
    PORT
      LAYER met3 ;
        RECT 696.000 268.640 700.000 269.240 ;
    END
  END data_out[97]
  PIN data_out[98]
    DIRECTION OUTPUT ;
    USE SIGNAL ;
    ANTENNADIFFAREA 0.445500 ;
    PORT
      LAYER met3 ;
        RECT 696.000 346.840 700.000 347.440 ;
    END
  END data_out[98]
  PIN data_out[99]
    DIRECTION OUTPUT ;
    USE SIGNAL ;
    ANTENNADIFFAREA 0.445500 ;
    PORT
      LAYER met2 ;
        RECT 431.570 0.000 431.850 4.000 ;
    END
  END data_out[99]
  PIN data_out[9]
    DIRECTION OUTPUT ;
    USE SIGNAL ;
    ANTENNADIFFAREA 0.445500 ;
    PORT
      LAYER met3 ;
        RECT 696.000 207.440 700.000 208.040 ;
    END
  END data_out[9]
  PIN done
    DIRECTION OUTPUT ;
    USE SIGNAL ;
    ANTENNADIFFAREA 0.445500 ;
    PORT
      LAYER met2 ;
        RECT 109.570 0.000 109.850 4.000 ;
    END
  END done
  PIN ena
    DIRECTION INPUT ;
    USE SIGNAL ;
    ANTENNAGATEAREA 0.213000 ;
    PORT
      LAYER met3 ;
        RECT 0.000 136.040 4.000 136.640 ;
    END
  END ena
  PIN key[0]
    DIRECTION INPUT ;
    USE SIGNAL ;
    ANTENNAGATEAREA 0.196500 ;
    PORT
      LAYER met3 ;
        RECT 0.000 639.240 4.000 639.840 ;
    END
  END key[0]
  PIN key[100]
    DIRECTION INPUT ;
    USE SIGNAL ;
    ANTENNAGATEAREA 0.196500 ;
    PORT
      LAYER met3 ;
        RECT 0.000 414.840 4.000 415.440 ;
    END
  END key[100]
  PIN key[101]
    DIRECTION INPUT ;
    USE SIGNAL ;
    ANTENNAGATEAREA 0.196500 ;
    PORT
      LAYER met3 ;
        RECT 0.000 139.440 4.000 140.040 ;
    END
  END key[101]
  PIN key[102]
    DIRECTION INPUT ;
    USE SIGNAL ;
    ANTENNAGATEAREA 0.196500 ;
    PORT
      LAYER met3 ;
        RECT 0.000 170.040 4.000 170.640 ;
    END
  END key[102]
  PIN key[103]
    DIRECTION INPUT ;
    USE SIGNAL ;
    ANTENNAGATEAREA 0.196500 ;
    PORT
      LAYER met3 ;
        RECT 0.000 176.840 4.000 177.440 ;
    END
  END key[103]
  PIN key[104]
    DIRECTION INPUT ;
    USE SIGNAL ;
    ANTENNAGATEAREA 0.196500 ;
    PORT
      LAYER met3 ;
        RECT 0.000 326.440 4.000 327.040 ;
    END
  END key[104]
  PIN key[105]
    DIRECTION INPUT ;
    USE SIGNAL ;
    ANTENNAGATEAREA 0.196500 ;
    PORT
      LAYER met3 ;
        RECT 0.000 557.640 4.000 558.240 ;
    END
  END key[105]
  PIN key[106]
    DIRECTION INPUT ;
    USE SIGNAL ;
    ANTENNAGATEAREA 0.196500 ;
    PORT
      LAYER met3 ;
        RECT 0.000 537.240 4.000 537.840 ;
    END
  END key[106]
  PIN key[107]
    DIRECTION INPUT ;
    USE SIGNAL ;
    ANTENNAGATEAREA 0.196500 ;
    PORT
      LAYER met2 ;
        RECT 22.630 696.000 22.910 700.000 ;
    END
  END key[107]
  PIN key[108]
    DIRECTION INPUT ;
    USE SIGNAL ;
    ANTENNAGATEAREA 0.126000 ;
    PORT
      LAYER met3 ;
        RECT 0.000 601.840 4.000 602.440 ;
    END
  END key[108]
  PIN key[109]
    DIRECTION INPUT ;
    USE SIGNAL ;
    ANTENNAGATEAREA 0.196500 ;
    PORT
      LAYER met3 ;
        RECT 0.000 353.640 4.000 354.240 ;
    END
  END key[109]
  PIN key[10]
    DIRECTION INPUT ;
    USE SIGNAL ;
    ANTENNAGATEAREA 0.196500 ;
    PORT
      LAYER met3 ;
        RECT 0.000 516.840 4.000 517.440 ;
    END
  END key[10]
  PIN key[110]
    DIRECTION INPUT ;
    USE SIGNAL ;
    ANTENNAGATEAREA 0.196500 ;
    PORT
      LAYER met3 ;
        RECT 0.000 224.440 4.000 225.040 ;
    END
  END key[110]
  PIN key[111]
    DIRECTION INPUT ;
    USE SIGNAL ;
    ANTENNAGATEAREA 0.196500 ;
    PORT
      LAYER met2 ;
        RECT 41.950 696.000 42.230 700.000 ;
    END
  END key[111]
  PIN key[112]
    DIRECTION INPUT ;
    USE SIGNAL ;
    ANTENNAGATEAREA 0.196500 ;
    PORT
      LAYER met2 ;
        RECT 32.290 696.000 32.570 700.000 ;
    END
  END key[112]
  PIN key[113]
    DIRECTION INPUT ;
    USE SIGNAL ;
    ANTENNAGATEAREA 0.196500 ;
    PORT
      LAYER met2 ;
        RECT 54.830 696.000 55.110 700.000 ;
    END
  END key[113]
  PIN key[114]
    DIRECTION INPUT ;
    USE SIGNAL ;
    ANTENNAGATEAREA 0.196500 ;
    PORT
      LAYER met3 ;
        RECT 0.000 363.840 4.000 364.440 ;
    END
  END key[114]
  PIN key[115]
    DIRECTION INPUT ;
    USE SIGNAL ;
    ANTENNAGATEAREA 0.196500 ;
    PORT
      LAYER met3 ;
        RECT 0.000 115.640 4.000 116.240 ;
    END
  END key[115]
  PIN key[116]
    DIRECTION INPUT ;
    USE SIGNAL ;
    ANTENNAGATEAREA 0.196500 ;
    PORT
      LAYER met3 ;
        RECT 0.000 472.640 4.000 473.240 ;
    END
  END key[116]
  PIN key[117]
    DIRECTION INPUT ;
    USE SIGNAL ;
    ANTENNAGATEAREA 0.196500 ;
    PORT
      LAYER met3 ;
        RECT 0.000 550.840 4.000 551.440 ;
    END
  END key[117]
  PIN key[118]
    DIRECTION INPUT ;
    USE SIGNAL ;
    ANTENNAGATEAREA 0.196500 ;
    PORT
      LAYER met2 ;
        RECT 19.410 696.000 19.690 700.000 ;
    END
  END key[118]
  PIN key[119]
    DIRECTION INPUT ;
    USE SIGNAL ;
    ANTENNAGATEAREA 0.196500 ;
    PORT
      LAYER met3 ;
        RECT 0.000 438.640 4.000 439.240 ;
    END
  END key[119]
  PIN key[11]
    DIRECTION INPUT ;
    USE SIGNAL ;
    ANTENNAGATEAREA 0.196500 ;
    PORT
      LAYER met2 ;
        RECT 9.750 696.000 10.030 700.000 ;
    END
  END key[11]
  PIN key[120]
    DIRECTION INPUT ;
    USE SIGNAL ;
    ANTENNAGATEAREA 0.196500 ;
    PORT
      LAYER met3 ;
        RECT 0.000 540.640 4.000 541.240 ;
    END
  END key[120]
  PIN key[121]
    DIRECTION INPUT ;
    USE SIGNAL ;
    ANTENNAGATEAREA 0.196500 ;
    PORT
      LAYER met3 ;
        RECT 0.000 214.240 4.000 214.840 ;
    END
  END key[121]
  PIN key[122]
    DIRECTION INPUT ;
    USE SIGNAL ;
    ANTENNAGATEAREA 0.196500 ;
    PORT
      LAYER met2 ;
        RECT 12.970 696.000 13.250 700.000 ;
    END
  END key[122]
  PIN key[123]
    DIRECTION INPUT ;
    USE SIGNAL ;
    ANTENNAGATEAREA 0.196500 ;
    PORT
      LAYER met2 ;
        RECT 132.110 696.000 132.390 700.000 ;
    END
  END key[123]
  PIN key[124]
    DIRECTION INPUT ;
    USE SIGNAL ;
    ANTENNAGATEAREA 0.196500 ;
    PORT
      LAYER met3 ;
        RECT 0.000 581.440 4.000 582.040 ;
    END
  END key[124]
  PIN key[125]
    DIRECTION INPUT ;
    USE SIGNAL ;
    ANTENNAGATEAREA 0.213000 ;
    PORT
      LAYER met3 ;
        RECT 0.000 622.240 4.000 622.840 ;
    END
  END key[125]
  PIN key[126]
    DIRECTION INPUT ;
    USE SIGNAL ;
    ANTENNAGATEAREA 0.196500 ;
    PORT
      LAYER met3 ;
        RECT 0.000 302.640 4.000 303.240 ;
    END
  END key[126]
  PIN key[127]
    DIRECTION INPUT ;
    USE SIGNAL ;
    ANTENNAGATEAREA 0.196500 ;
    PORT
      LAYER met3 ;
        RECT 0.000 238.040 4.000 238.640 ;
    END
  END key[127]
  PIN key[12]
    DIRECTION INPUT ;
    USE SIGNAL ;
    ANTENNAGATEAREA 0.196500 ;
    PORT
      LAYER met3 ;
        RECT 0.000 425.040 4.000 425.640 ;
    END
  END key[12]
  PIN key[13]
    DIRECTION INPUT ;
    USE SIGNAL ;
    ANTENNAGATEAREA 0.196500 ;
    PORT
      LAYER met3 ;
        RECT 0.000 343.440 4.000 344.040 ;
    END
  END key[13]
  PIN key[14]
    DIRECTION INPUT ;
    USE SIGNAL ;
    ANTENNAGATEAREA 0.196500 ;
    PORT
      LAYER met3 ;
        RECT 0.000 210.840 4.000 211.440 ;
    END
  END key[14]
  PIN key[15]
    DIRECTION INPUT ;
    USE SIGNAL ;
    ANTENNAGATEAREA 0.196500 ;
    PORT
      LAYER met3 ;
        RECT 0.000 510.040 4.000 510.640 ;
    END
  END key[15]
  PIN key[16]
    DIRECTION INPUT ;
    USE SIGNAL ;
    ANTENNAGATEAREA 0.196500 ;
    PORT
      LAYER met2 ;
        RECT 51.610 696.000 51.890 700.000 ;
    END
  END key[16]
  PIN key[17]
    DIRECTION INPUT ;
    USE SIGNAL ;
    ANTENNAGATEAREA 0.196500 ;
    PORT
      LAYER met2 ;
        RECT 45.170 696.000 45.450 700.000 ;
    END
  END key[17]
  PIN key[18]
    DIRECTION INPUT ;
    USE SIGNAL ;
    ANTENNAGATEAREA 0.196500 ;
    PORT
      LAYER met3 ;
        RECT 0.000 367.240 4.000 367.840 ;
    END
  END key[18]
  PIN key[19]
    DIRECTION INPUT ;
    USE SIGNAL ;
    ANTENNAGATEAREA 0.196500 ;
    PORT
      LAYER met3 ;
        RECT 0.000 289.040 4.000 289.640 ;
    END
  END key[19]
  PIN key[1]
    DIRECTION INPUT ;
    USE SIGNAL ;
    ANTENNAGATEAREA 0.196500 ;
    PORT
      LAYER met3 ;
        RECT 0.000 309.440 4.000 310.040 ;
    END
  END key[1]
  PIN key[20]
    DIRECTION INPUT ;
    USE SIGNAL ;
    ANTENNAGATEAREA 0.196500 ;
    PORT
      LAYER met3 ;
        RECT 0.000 567.840 4.000 568.440 ;
    END
  END key[20]
  PIN key[21]
    DIRECTION INPUT ;
    USE SIGNAL ;
    ANTENNAGATEAREA 0.196500 ;
    PORT
      LAYER met3 ;
        RECT 0.000 506.640 4.000 507.240 ;
    END
  END key[21]
  PIN key[22]
    DIRECTION INPUT ;
    USE SIGNAL ;
    ANTENNAGATEAREA 0.196500 ;
    PORT
      LAYER met2 ;
        RECT 29.070 696.000 29.350 700.000 ;
    END
  END key[22]
  PIN key[23]
    DIRECTION INPUT ;
    USE SIGNAL ;
    ANTENNAGATEAREA 0.196500 ;
    PORT
      LAYER met3 ;
        RECT 0.000 435.240 4.000 435.840 ;
    END
  END key[23]
  PIN key[24]
    DIRECTION INPUT ;
    USE SIGNAL ;
    ANTENNAGATEAREA 0.196500 ;
    PORT
      LAYER met3 ;
        RECT 0.000 496.440 4.000 497.040 ;
    END
  END key[24]
  PIN key[25]
    DIRECTION INPUT ;
    USE SIGNAL ;
    ANTENNAGATEAREA 0.196500 ;
    PORT
      LAYER met3 ;
        RECT 0.000 153.040 4.000 153.640 ;
    END
  END key[25]
  PIN key[26]
    DIRECTION INPUT ;
    USE SIGNAL ;
    ANTENNAGATEAREA 0.196500 ;
    PORT
      LAYER met2 ;
        RECT 35.510 696.000 35.790 700.000 ;
    END
  END key[26]
  PIN key[27]
    DIRECTION INPUT ;
    USE SIGNAL ;
    ANTENNAGATEAREA 0.196500 ;
    PORT
      LAYER met2 ;
        RECT 16.190 696.000 16.470 700.000 ;
    END
  END key[27]
  PIN key[28]
    DIRECTION INPUT ;
    USE SIGNAL ;
    ANTENNAGATEAREA 0.196500 ;
    PORT
      LAYER met3 ;
        RECT 0.000 448.840 4.000 449.440 ;
    END
  END key[28]
  PIN key[29]
    DIRECTION INPUT ;
    USE SIGNAL ;
    ANTENNAGATEAREA 0.196500 ;
    PORT
      LAYER met3 ;
        RECT 0.000 397.840 4.000 398.440 ;
    END
  END key[29]
  PIN key[2]
    DIRECTION INPUT ;
    USE SIGNAL ;
    ANTENNAGATEAREA 0.196500 ;
    PORT
      LAYER met3 ;
        RECT 0.000 193.840 4.000 194.440 ;
    END
  END key[2]
  PIN key[30]
    DIRECTION INPUT ;
    USE SIGNAL ;
    ANTENNAGATEAREA 0.196500 ;
    PORT
      LAYER met3 ;
        RECT 0.000 275.440 4.000 276.040 ;
    END
  END key[30]
  PIN key[31]
    DIRECTION INPUT ;
    USE SIGNAL ;
    ANTENNAGATEAREA 0.196500 ;
    PORT
      LAYER met3 ;
        RECT 0.000 149.640 4.000 150.240 ;
    END
  END key[31]
  PIN key[32]
    DIRECTION INPUT ;
    USE SIGNAL ;
    ANTENNAGATEAREA 0.196500 ;
    PORT
      LAYER met3 ;
        RECT 0.000 479.440 4.000 480.040 ;
    END
  END key[32]
  PIN key[33]
    DIRECTION INPUT ;
    USE SIGNAL ;
    ANTENNAGATEAREA 0.196500 ;
    PORT
      LAYER met3 ;
        RECT 0.000 316.240 4.000 316.840 ;
    END
  END key[33]
  PIN key[34]
    DIRECTION INPUT ;
    USE SIGNAL ;
    ANTENNAGATEAREA 0.196500 ;
    PORT
      LAYER met3 ;
        RECT 0.000 272.040 4.000 272.640 ;
    END
  END key[34]
  PIN key[35]
    DIRECTION INPUT ;
    USE SIGNAL ;
    ANTENNAGATEAREA 0.196500 ;
    PORT
      LAYER met3 ;
        RECT 0.000 200.640 4.000 201.240 ;
    END
  END key[35]
  PIN key[36]
    DIRECTION INPUT ;
    USE SIGNAL ;
    ANTENNAGATEAREA 0.196500 ;
    PORT
      LAYER met3 ;
        RECT 0.000 618.840 4.000 619.440 ;
    END
  END key[36]
  PIN key[37]
    DIRECTION INPUT ;
    USE SIGNAL ;
    ANTENNAGATEAREA 0.196500 ;
    PORT
      LAYER met3 ;
        RECT 0.000 163.240 4.000 163.840 ;
    END
  END key[37]
  PIN key[38]
    DIRECTION INPUT ;
    USE SIGNAL ;
    ANTENNAGATEAREA 0.196500 ;
    PORT
      LAYER met3 ;
        RECT 0.000 217.640 4.000 218.240 ;
    END
  END key[38]
  PIN key[39]
    DIRECTION INPUT ;
    USE SIGNAL ;
    ANTENNAGATEAREA 0.196500 ;
    PORT
      LAYER met3 ;
        RECT 0.000 207.440 4.000 208.040 ;
    END
  END key[39]
  PIN key[3]
    DIRECTION INPUT ;
    USE SIGNAL ;
    ANTENNAGATEAREA 0.196500 ;
    PORT
      LAYER met3 ;
        RECT 0.000 142.840 4.000 143.440 ;
    END
  END key[3]
  PIN key[40]
    DIRECTION INPUT ;
    USE SIGNAL ;
    ANTENNAGATEAREA 0.196500 ;
    PORT
      LAYER met3 ;
        RECT 0.000 323.040 4.000 323.640 ;
    END
  END key[40]
  PIN key[41]
    DIRECTION INPUT ;
    USE SIGNAL ;
    ANTENNAGATEAREA 0.196500 ;
    PORT
      LAYER met3 ;
        RECT 0.000 499.840 4.000 500.440 ;
    END
  END key[41]
  PIN key[42]
    DIRECTION INPUT ;
    USE SIGNAL ;
    ANTENNAGATEAREA 0.196500 ;
    PORT
      LAYER met3 ;
        RECT 0.000 520.240 4.000 520.840 ;
    END
  END key[42]
  PIN key[43]
    DIRECTION INPUT ;
    USE SIGNAL ;
    ANTENNAGATEAREA 0.196500 ;
    PORT
      LAYER met2 ;
        RECT 25.850 696.000 26.130 700.000 ;
    END
  END key[43]
  PIN key[44]
    DIRECTION INPUT ;
    USE SIGNAL ;
    ANTENNAGATEAREA 0.196500 ;
    PORT
      LAYER met3 ;
        RECT 0.000 428.440 4.000 429.040 ;
    END
  END key[44]
  PIN key[45]
    DIRECTION INPUT ;
    USE SIGNAL ;
    ANTENNAGATEAREA 0.196500 ;
    PORT
      LAYER met3 ;
        RECT 0.000 336.640 4.000 337.240 ;
    END
  END key[45]
  PIN key[46]
    DIRECTION INPUT ;
    USE SIGNAL ;
    ANTENNAGATEAREA 0.196500 ;
    PORT
      LAYER met3 ;
        RECT 0.000 166.640 4.000 167.240 ;
    END
  END key[46]
  PIN key[47]
    DIRECTION INPUT ;
    USE SIGNAL ;
    ANTENNAGATEAREA 0.196500 ;
    PORT
      LAYER met3 ;
        RECT 0.000 527.040 4.000 527.640 ;
    END
  END key[47]
  PIN key[48]
    DIRECTION INPUT ;
    USE SIGNAL ;
    ANTENNAGATEAREA 0.196500 ;
    PORT
      LAYER met2 ;
        RECT 38.730 696.000 39.010 700.000 ;
    END
  END key[48]
  PIN key[49]
    DIRECTION INPUT ;
    USE SIGNAL ;
    ANTENNAGATEAREA 0.196500 ;
    PORT
      LAYER met2 ;
        RECT 3.310 696.000 3.590 700.000 ;
    END
  END key[49]
  PIN key[4]
    DIRECTION INPUT ;
    USE SIGNAL ;
    ANTENNAGATEAREA 0.196500 ;
    PORT
      LAYER met3 ;
        RECT 0.000 615.440 4.000 616.040 ;
    END
  END key[4]
  PIN key[50]
    DIRECTION INPUT ;
    USE SIGNAL ;
    ANTENNAGATEAREA 0.196500 ;
    PORT
      LAYER met3 ;
        RECT 0.000 360.440 4.000 361.040 ;
    END
  END key[50]
  PIN key[51]
    DIRECTION INPUT ;
    USE SIGNAL ;
    ANTENNAGATEAREA 0.196500 ;
    PORT
      LAYER met3 ;
        RECT 0.000 261.840 4.000 262.440 ;
    END
  END key[51]
  PIN key[52]
    DIRECTION INPUT ;
    USE SIGNAL ;
    ANTENNAGATEAREA 0.196500 ;
    PORT
      LAYER met3 ;
        RECT 0.000 561.040 4.000 561.640 ;
    END
  END key[52]
  PIN key[53]
    DIRECTION INPUT ;
    USE SIGNAL ;
    ANTENNAGATEAREA 0.196500 ;
    PORT
      LAYER met3 ;
        RECT 0.000 486.240 4.000 486.840 ;
    END
  END key[53]
  PIN key[54]
    DIRECTION INPUT ;
    USE SIGNAL ;
    ANTENNAGATEAREA 0.196500 ;
    PORT
      LAYER met2 ;
        RECT 6.530 696.000 6.810 700.000 ;
    END
  END key[54]
  PIN key[55]
    DIRECTION INPUT ;
    USE SIGNAL ;
    ANTENNAGATEAREA 0.196500 ;
    PORT
      LAYER met3 ;
        RECT 0.000 598.440 4.000 599.040 ;
    END
  END key[55]
  PIN key[56]
    DIRECTION INPUT ;
    USE SIGNAL ;
    ANTENNAGATEAREA 0.196500 ;
    PORT
      LAYER met3 ;
        RECT 0.000 489.640 4.000 490.240 ;
    END
  END key[56]
  PIN key[57]
    DIRECTION INPUT ;
    USE SIGNAL ;
    ANTENNAGATEAREA 0.196500 ;
    PORT
      LAYER met3 ;
        RECT 0.000 292.440 4.000 293.040 ;
    END
  END key[57]
  PIN key[58]
    DIRECTION INPUT ;
    USE SIGNAL ;
    ANTENNAGATEAREA 0.196500 ;
    PORT
      LAYER met2 ;
        RECT 0.090 696.000 0.370 700.000 ;
    END
  END key[58]
  PIN key[59]
    DIRECTION INPUT ;
    USE SIGNAL ;
    ANTENNAGATEAREA 0.196500 ;
    PORT
      LAYER met2 ;
        RECT 48.390 696.000 48.670 700.000 ;
    END
  END key[59]
  PIN key[5]
    DIRECTION INPUT ;
    USE SIGNAL ;
    ANTENNAGATEAREA 0.196500 ;
    PORT
      LAYER met3 ;
        RECT 0.000 278.840 4.000 279.440 ;
    END
  END key[5]
  PIN key[60]
    DIRECTION INPUT ;
    USE SIGNAL ;
    ANTENNAGATEAREA 0.196500 ;
    PORT
      LAYER met3 ;
        RECT 0.000 588.240 4.000 588.840 ;
    END
  END key[60]
  PIN key[61]
    DIRECTION INPUT ;
    USE SIGNAL ;
    ANTENNAGATEAREA 0.196500 ;
    PORT
      LAYER met3 ;
        RECT 0.000 384.240 4.000 384.840 ;
    END
  END key[61]
  PIN key[62]
    DIRECTION INPUT ;
    USE SIGNAL ;
    ANTENNAGATEAREA 0.196500 ;
    PORT
      LAYER met3 ;
        RECT 0.000 299.240 4.000 299.840 ;
    END
  END key[62]
  PIN key[63]
    DIRECTION INPUT ;
    USE SIGNAL ;
    ANTENNAGATEAREA 0.196500 ;
    PORT
      LAYER met3 ;
        RECT 0.000 231.240 4.000 231.840 ;
    END
  END key[63]
  PIN key[64]
    DIRECTION INPUT ;
    USE SIGNAL ;
    ANTENNAGATEAREA 0.196500 ;
    PORT
      LAYER met3 ;
        RECT 0.000 482.840 4.000 483.440 ;
    END
  END key[64]
  PIN key[65]
    DIRECTION INPUT ;
    USE SIGNAL ;
    ANTENNAGATEAREA 0.196500 ;
    PORT
      LAYER met3 ;
        RECT 0.000 329.840 4.000 330.440 ;
    END
  END key[65]
  PIN key[66]
    DIRECTION INPUT ;
    USE SIGNAL ;
    ANTENNAGATEAREA 0.196500 ;
    PORT
      LAYER met3 ;
        RECT 0.000 197.240 4.000 197.840 ;
    END
  END key[66]
  PIN key[67]
    DIRECTION INPUT ;
    USE SIGNAL ;
    ANTENNAGATEAREA 0.196500 ;
    PORT
      LAYER met3 ;
        RECT 0.000 180.240 4.000 180.840 ;
    END
  END key[67]
  PIN key[68]
    DIRECTION INPUT ;
    USE SIGNAL ;
    ANTENNAGATEAREA 0.196500 ;
    PORT
      LAYER met3 ;
        RECT 0.000 418.240 4.000 418.840 ;
    END
  END key[68]
  PIN key[69]
    DIRECTION INPUT ;
    USE SIGNAL ;
    ANTENNAGATEAREA 0.196500 ;
    PORT
      LAYER met3 ;
        RECT 0.000 241.440 4.000 242.040 ;
    END
  END key[69]
  PIN key[6]
    DIRECTION INPUT ;
    USE SIGNAL ;
    ANTENNAGATEAREA 0.196500 ;
    PORT
      LAYER met3 ;
        RECT 0.000 258.440 4.000 259.040 ;
    END
  END key[6]
  PIN key[70]
    DIRECTION INPUT ;
    USE SIGNAL ;
    ANTENNAGATEAREA 0.196500 ;
    PORT
      LAYER met3 ;
        RECT 0.000 251.640 4.000 252.240 ;
    END
  END key[70]
  PIN key[71]
    DIRECTION INPUT ;
    USE SIGNAL ;
    ANTENNAGATEAREA 0.196500 ;
    PORT
      LAYER met3 ;
        RECT 0.000 187.040 4.000 187.640 ;
    END
  END key[71]
  PIN key[72]
    DIRECTION INPUT ;
    USE SIGNAL ;
    ANTENNAGATEAREA 0.196500 ;
    PORT
      LAYER met3 ;
        RECT 0.000 268.640 4.000 269.240 ;
    END
  END key[72]
  PIN key[73]
    DIRECTION INPUT ;
    USE SIGNAL ;
    ANTENNAGATEAREA 0.196500 ;
    PORT
      LAYER met3 ;
        RECT 0.000 544.040 4.000 544.640 ;
    END
  END key[73]
  PIN key[74]
    DIRECTION INPUT ;
    USE SIGNAL ;
    ANTENNAGATEAREA 0.196500 ;
    PORT
      LAYER met3 ;
        RECT 0.000 513.440 4.000 514.040 ;
    END
  END key[74]
  PIN key[75]
    DIRECTION INPUT ;
    USE SIGNAL ;
    ANTENNAGATEAREA 0.196500 ;
    PORT
      LAYER met3 ;
        RECT 0.000 533.840 4.000 534.440 ;
    END
  END key[75]
  PIN key[76]
    DIRECTION INPUT ;
    USE SIGNAL ;
    ANTENNAGATEAREA 0.196500 ;
    PORT
      LAYER met3 ;
        RECT 0.000 431.840 4.000 432.440 ;
    END
  END key[76]
  PIN key[77]
    DIRECTION INPUT ;
    USE SIGNAL ;
    ANTENNAGATEAREA 0.196500 ;
    PORT
      LAYER met3 ;
        RECT 0.000 350.240 4.000 350.840 ;
    END
  END key[77]
  PIN key[78]
    DIRECTION INPUT ;
    USE SIGNAL ;
    ANTENNAGATEAREA 0.196500 ;
    PORT
      LAYER met3 ;
        RECT 0.000 234.640 4.000 235.240 ;
    END
  END key[78]
  PIN key[79]
    DIRECTION INPUT ;
    USE SIGNAL ;
    ANTENNAGATEAREA 0.196500 ;
    PORT
      LAYER met3 ;
        RECT 0.000 523.640 4.000 524.240 ;
    END
  END key[79]
  PIN key[7]
    DIRECTION INPUT ;
    USE SIGNAL ;
    ANTENNAGATEAREA 0.196500 ;
    PORT
      LAYER met3 ;
        RECT 0.000 122.440 4.000 123.040 ;
    END
  END key[7]
  PIN key[80]
    DIRECTION INPUT ;
    USE SIGNAL ;
    ANTENNAGATEAREA 0.196500 ;
    PORT
      LAYER met3 ;
        RECT 0.000 530.440 4.000 531.040 ;
    END
  END key[80]
  PIN key[81]
    DIRECTION INPUT ;
    USE SIGNAL ;
    ANTENNAGATEAREA 0.196500 ;
    PORT
      LAYER met2 ;
        RECT 206.170 696.000 206.450 700.000 ;
    END
  END key[81]
  PIN key[82]
    DIRECTION INPUT ;
    USE SIGNAL ;
    ANTENNAGATEAREA 0.196500 ;
    PORT
      LAYER met3 ;
        RECT 0.000 346.840 4.000 347.440 ;
    END
  END key[82]
  PIN key[83]
    DIRECTION INPUT ;
    USE SIGNAL ;
    ANTENNAGATEAREA 0.196500 ;
    PORT
      LAYER met3 ;
        RECT 0.000 265.240 4.000 265.840 ;
    END
  END key[83]
  PIN key[84]
    DIRECTION INPUT ;
    USE SIGNAL ;
    ANTENNAGATEAREA 0.196500 ;
    PORT
      LAYER met3 ;
        RECT 0.000 476.040 4.000 476.640 ;
    END
  END key[84]
  PIN key[85]
    DIRECTION INPUT ;
    USE SIGNAL ;
    ANTENNAGATEAREA 0.196500 ;
    PORT
      LAYER met3 ;
        RECT 0.000 503.240 4.000 503.840 ;
    END
  END key[85]
  PIN key[86]
    DIRECTION INPUT ;
    USE SIGNAL ;
    ANTENNAGATEAREA 0.196500 ;
    PORT
      LAYER met3 ;
        RECT 0.000 554.240 4.000 554.840 ;
    END
  END key[86]
  PIN key[87]
    DIRECTION INPUT ;
    USE SIGNAL ;
    ANTENNAGATEAREA 0.196500 ;
    PORT
      LAYER met3 ;
        RECT 0.000 595.040 4.000 595.640 ;
    END
  END key[87]
  PIN key[88]
    DIRECTION INPUT ;
    USE SIGNAL ;
    ANTENNAGATEAREA 0.196500 ;
    PORT
      LAYER met3 ;
        RECT 0.000 547.440 4.000 548.040 ;
    END
  END key[88]
  PIN key[89]
    DIRECTION INPUT ;
    USE SIGNAL ;
    ANTENNAGATEAREA 0.196500 ;
    PORT
      LAYER met3 ;
        RECT 0.000 146.240 4.000 146.840 ;
    END
  END key[89]
  PIN key[8]
    DIRECTION INPUT ;
    USE SIGNAL ;
    ANTENNAGATEAREA 0.196500 ;
    PORT
      LAYER met3 ;
        RECT 0.000 190.440 4.000 191.040 ;
    END
  END key[8]
  PIN key[90]
    DIRECTION INPUT ;
    USE SIGNAL ;
    ANTENNAGATEAREA 0.196500 ;
    PORT
      LAYER met2 ;
        RECT 148.210 696.000 148.490 700.000 ;
    END
  END key[90]
  PIN key[91]
    DIRECTION INPUT ;
    USE SIGNAL ;
    ANTENNAGATEAREA 0.196500 ;
    PORT
      LAYER met2 ;
        RECT 190.070 696.000 190.350 700.000 ;
    END
  END key[91]
  PIN key[92]
    DIRECTION INPUT ;
    USE SIGNAL ;
    ANTENNAGATEAREA 0.196500 ;
    PORT
      LAYER met3 ;
        RECT 0.000 584.840 4.000 585.440 ;
    END
  END key[92]
  PIN key[93]
    DIRECTION INPUT ;
    USE SIGNAL ;
    ANTENNAGATEAREA 0.196500 ;
    PORT
      LAYER met3 ;
        RECT 0.000 394.440 4.000 395.040 ;
    END
  END key[93]
  PIN key[94]
    DIRECTION INPUT ;
    USE SIGNAL ;
    ANTENNAGATEAREA 0.196500 ;
    PORT
      LAYER met3 ;
        RECT 0.000 295.840 4.000 296.440 ;
    END
  END key[94]
  PIN key[95]
    DIRECTION INPUT ;
    USE SIGNAL ;
    ANTENNAGATEAREA 0.196500 ;
    PORT
      LAYER met3 ;
        RECT 0.000 221.040 4.000 221.640 ;
    END
  END key[95]
  PIN key[96]
    DIRECTION INPUT ;
    USE SIGNAL ;
    ANTENNAGATEAREA 0.196500 ;
    PORT
      LAYER met3 ;
        RECT 0.000 571.240 4.000 571.840 ;
    END
  END key[96]
  PIN key[97]
    DIRECTION INPUT ;
    USE SIGNAL ;
    ANTENNAGATEAREA 0.196500 ;
    PORT
      LAYER met3 ;
        RECT 0.000 312.840 4.000 313.440 ;
    END
  END key[97]
  PIN key[98]
    DIRECTION INPUT ;
    USE SIGNAL ;
    ANTENNAGATEAREA 0.196500 ;
    PORT
      LAYER met3 ;
        RECT 0.000 255.040 4.000 255.640 ;
    END
  END key[98]
  PIN key[99]
    DIRECTION INPUT ;
    USE SIGNAL ;
    ANTENNAGATEAREA 0.196500 ;
    PORT
      LAYER met3 ;
        RECT 0.000 173.440 4.000 174.040 ;
    END
  END key[99]
  PIN key[9]
    DIRECTION INPUT ;
    USE SIGNAL ;
    ANTENNAGATEAREA 0.196500 ;
    PORT
      LAYER met3 ;
        RECT 0.000 493.040 4.000 493.640 ;
    END
  END key[9]
  PIN nonce[0]
    DIRECTION INPUT ;
    USE SIGNAL ;
    ANTENNAGATEAREA 0.196500 ;
    PORT
      LAYER met3 ;
        RECT 0.000 411.440 4.000 412.040 ;
    END
  END nonce[0]
  PIN nonce[10]
    DIRECTION INPUT ;
    USE SIGNAL ;
    ANTENNAGATEAREA 0.196500 ;
    PORT
      LAYER met3 ;
        RECT 0.000 357.040 4.000 357.640 ;
    END
  END nonce[10]
  PIN nonce[11]
    DIRECTION INPUT ;
    USE SIGNAL ;
    ANTENNAGATEAREA 0.196500 ;
    PORT
      LAYER met2 ;
        RECT 128.890 0.000 129.170 4.000 ;
    END
  END nonce[11]
  PIN nonce[12]
    DIRECTION INPUT ;
    USE SIGNAL ;
    ANTENNAGATEAREA 0.196500 ;
    PORT
      LAYER met3 ;
        RECT 0.000 605.240 4.000 605.840 ;
    END
  END nonce[12]
  PIN nonce[13]
    DIRECTION INPUT ;
    USE SIGNAL ;
    ANTENNAGATEAREA 0.196500 ;
    PORT
      LAYER met2 ;
        RECT 135.330 0.000 135.610 4.000 ;
    END
  END nonce[13]
  PIN nonce[14]
    DIRECTION INPUT ;
    USE SIGNAL ;
    ANTENNAGATEAREA 0.196500 ;
    PORT
      LAYER met2 ;
        RECT 222.270 0.000 222.550 4.000 ;
    END
  END nonce[14]
  PIN nonce[15]
    DIRECTION INPUT ;
    USE SIGNAL ;
    ANTENNAGATEAREA 0.126000 ;
    PORT
      LAYER met3 ;
        RECT 0.000 156.440 4.000 157.040 ;
    END
  END nonce[15]
  PIN nonce[16]
    DIRECTION INPUT ;
    USE SIGNAL ;
    ANTENNAGATEAREA 0.196500 ;
    PORT
      LAYER met3 ;
        RECT 0.000 574.640 4.000 575.240 ;
    END
  END nonce[16]
  PIN nonce[17]
    DIRECTION INPUT ;
    USE SIGNAL ;
    ANTENNAGATEAREA 0.196500 ;
    PORT
      LAYER met2 ;
        RECT 148.210 0.000 148.490 4.000 ;
    END
  END nonce[17]
  PIN nonce[18]
    DIRECTION INPUT ;
    USE SIGNAL ;
    ANTENNAGATEAREA 0.196500 ;
    PORT
      LAYER met3 ;
        RECT 0.000 183.640 4.000 184.240 ;
    END
  END nonce[18]
  PIN nonce[19]
    DIRECTION INPUT ;
    USE SIGNAL ;
    ANTENNAGATEAREA 0.196500 ;
    PORT
      LAYER met2 ;
        RECT 164.310 0.000 164.590 4.000 ;
    END
  END nonce[19]
  PIN nonce[1]
    DIRECTION INPUT ;
    USE SIGNAL ;
    ANTENNAGATEAREA 0.196500 ;
    PORT
      LAYER met2 ;
        RECT 154.650 0.000 154.930 4.000 ;
    END
  END nonce[1]
  PIN nonce[20]
    DIRECTION INPUT ;
    USE SIGNAL ;
    ANTENNAGATEAREA 0.196500 ;
    PORT
      LAYER met3 ;
        RECT 0.000 465.840 4.000 466.440 ;
    END
  END nonce[20]
  PIN nonce[21]
    DIRECTION INPUT ;
    USE SIGNAL ;
    ANTENNAGATEAREA 0.196500 ;
    PORT
      LAYER met3 ;
        RECT 0.000 125.840 4.000 126.440 ;
    END
  END nonce[21]
  PIN nonce[22]
    DIRECTION INPUT ;
    USE SIGNAL ;
    ANTENNAGATEAREA 0.196500 ;
    PORT
      LAYER met2 ;
        RECT 173.970 0.000 174.250 4.000 ;
    END
  END nonce[22]
  PIN nonce[23]
    DIRECTION INPUT ;
    USE SIGNAL ;
    ANTENNAGATEAREA 0.196500 ;
    PORT
      LAYER met2 ;
        RECT 264.130 0.000 264.410 4.000 ;
    END
  END nonce[23]
  PIN nonce[24]
    DIRECTION INPUT ;
    USE SIGNAL ;
    ANTENNAGATEAREA 0.196500 ;
    PORT
      LAYER met3 ;
        RECT 0.000 578.040 4.000 578.640 ;
    END
  END nonce[24]
  PIN nonce[25]
    DIRECTION INPUT ;
    USE SIGNAL ;
    ANTENNAGATEAREA 0.196500 ;
    PORT
      LAYER met3 ;
        RECT 0.000 248.240 4.000 248.840 ;
    END
  END nonce[25]
  PIN nonce[26]
    DIRECTION INPUT ;
    USE SIGNAL ;
    ANTENNAGATEAREA 0.196500 ;
    PORT
      LAYER met3 ;
        RECT 0.000 377.440 4.000 378.040 ;
    END
  END nonce[26]
  PIN nonce[27]
    DIRECTION INPUT ;
    USE SIGNAL ;
    ANTENNAGATEAREA 0.196500 ;
    PORT
      LAYER met2 ;
        RECT 248.030 0.000 248.310 4.000 ;
    END
  END nonce[27]
  PIN nonce[28]
    DIRECTION INPUT ;
    USE SIGNAL ;
    ANTENNAGATEAREA 0.196500 ;
    PORT
      LAYER met3 ;
        RECT 0.000 591.640 4.000 592.240 ;
    END
  END nonce[28]
  PIN nonce[29]
    DIRECTION INPUT ;
    USE SIGNAL ;
    ANTENNAGATEAREA 0.196500 ;
    PORT
      LAYER met3 ;
        RECT 0.000 408.040 4.000 408.640 ;
    END
  END nonce[29]
  PIN nonce[2]
    DIRECTION INPUT ;
    USE SIGNAL ;
    ANTENNAGATEAREA 0.196500 ;
    PORT
      LAYER met2 ;
        RECT 144.990 0.000 145.270 4.000 ;
    END
  END nonce[2]
  PIN nonce[30]
    DIRECTION INPUT ;
    USE SIGNAL ;
    ANTENNAGATEAREA 0.196500 ;
    PORT
      LAYER met2 ;
        RECT 183.630 0.000 183.910 4.000 ;
    END
  END nonce[30]
  PIN nonce[31]
    DIRECTION INPUT ;
    USE SIGNAL ;
    ANTENNAGATEAREA 0.196500 ;
    PORT
      LAYER met2 ;
        RECT 209.390 0.000 209.670 4.000 ;
    END
  END nonce[31]
  PIN nonce[32]
    DIRECTION INPUT ;
    USE SIGNAL ;
    ANTENNAGATEAREA 0.196500 ;
    PORT
      LAYER met3 ;
        RECT 0.000 404.640 4.000 405.240 ;
    END
  END nonce[32]
  PIN nonce[33]
    DIRECTION INPUT ;
    USE SIGNAL ;
    ANTENNAGATEAREA 0.196500 ;
    PORT
      LAYER met2 ;
        RECT 238.370 0.000 238.650 4.000 ;
    END
  END nonce[33]
  PIN nonce[34]
    DIRECTION INPUT ;
    USE SIGNAL ;
    ANTENNAGATEAREA 0.196500 ;
    PORT
      LAYER met2 ;
        RECT 260.910 0.000 261.190 4.000 ;
    END
  END nonce[34]
  PIN nonce[35]
    DIRECTION INPUT ;
    USE SIGNAL ;
    ANTENNAGATEAREA 0.196500 ;
    PORT
      LAYER met2 ;
        RECT 225.490 0.000 225.770 4.000 ;
    END
  END nonce[35]
  PIN nonce[36]
    DIRECTION INPUT ;
    USE SIGNAL ;
    ANTENNAGATEAREA 0.196500 ;
    PORT
      LAYER met3 ;
        RECT 0.000 380.840 4.000 381.440 ;
    END
  END nonce[36]
  PIN nonce[37]
    DIRECTION INPUT ;
    USE SIGNAL ;
    ANTENNAGATEAREA 0.196500 ;
    PORT
      LAYER met2 ;
        RECT 219.050 0.000 219.330 4.000 ;
    END
  END nonce[37]
  PIN nonce[38]
    DIRECTION INPUT ;
    USE SIGNAL ;
    ANTENNAGATEAREA 0.196500 ;
    PORT
      LAYER met2 ;
        RECT 141.770 0.000 142.050 4.000 ;
    END
  END nonce[38]
  PIN nonce[39]
    DIRECTION INPUT ;
    USE SIGNAL ;
    ANTENNAGATEAREA 0.196500 ;
    PORT
      LAYER met2 ;
        RECT 212.610 0.000 212.890 4.000 ;
    END
  END nonce[39]
  PIN nonce[3]
    DIRECTION INPUT ;
    USE SIGNAL ;
    ANTENNAGATEAREA 0.196500 ;
    PORT
      LAYER met2 ;
        RECT 235.150 0.000 235.430 4.000 ;
    END
  END nonce[3]
  PIN nonce[40]
    DIRECTION INPUT ;
    USE SIGNAL ;
    ANTENNAGATEAREA 0.196500 ;
    PORT
      LAYER met3 ;
        RECT 0.000 625.640 4.000 626.240 ;
    END
  END nonce[40]
  PIN nonce[41]
    DIRECTION INPUT ;
    USE SIGNAL ;
    ANTENNAGATEAREA 0.196500 ;
    PORT
      LAYER met3 ;
        RECT 0.000 282.240 4.000 282.840 ;
    END
  END nonce[41]
  PIN nonce[42]
    DIRECTION INPUT ;
    USE SIGNAL ;
    ANTENNAGATEAREA 0.213000 ;
    PORT
      LAYER met3 ;
        RECT 0.000 112.240 4.000 112.840 ;
    END
  END nonce[42]
  PIN nonce[43]
    DIRECTION INPUT ;
    USE SIGNAL ;
    ANTENNAGATEAREA 0.196500 ;
    PORT
      LAYER met2 ;
        RECT 231.930 0.000 232.210 4.000 ;
    END
  END nonce[43]
  PIN nonce[44]
    DIRECTION INPUT ;
    USE SIGNAL ;
    ANTENNAGATEAREA 0.196500 ;
    PORT
      LAYER met3 ;
        RECT 0.000 608.640 4.000 609.240 ;
    END
  END nonce[44]
  PIN nonce[45]
    DIRECTION INPUT ;
    USE SIGNAL ;
    ANTENNAGATEAREA 0.196500 ;
    PORT
      LAYER met2 ;
        RECT 270.570 0.000 270.850 4.000 ;
    END
  END nonce[45]
  PIN nonce[46]
    DIRECTION INPUT ;
    USE SIGNAL ;
    ANTENNAGATEAREA 0.196500 ;
    PORT
      LAYER met2 ;
        RECT 228.710 0.000 228.990 4.000 ;
    END
  END nonce[46]
  PIN nonce[47]
    DIRECTION INPUT ;
    USE SIGNAL ;
    ANTENNAGATEAREA 0.196500 ;
    PORT
      LAYER met2 ;
        RECT 180.410 0.000 180.690 4.000 ;
    END
  END nonce[47]
  PIN nonce[48]
    DIRECTION INPUT ;
    USE SIGNAL ;
    ANTENNAGATEAREA 0.196500 ;
    PORT
      LAYER met3 ;
        RECT 0.000 462.440 4.000 463.040 ;
    END
  END nonce[48]
  PIN nonce[49]
    DIRECTION INPUT ;
    USE SIGNAL ;
    ANTENNAGATEAREA 0.196500 ;
    PORT
      LAYER met2 ;
        RECT 125.670 0.000 125.950 4.000 ;
    END
  END nonce[49]
  PIN nonce[4]
    DIRECTION INPUT ;
    USE SIGNAL ;
    ANTENNAGATEAREA 0.213000 ;
    PORT
      LAYER met3 ;
        RECT 0.000 635.840 4.000 636.440 ;
    END
  END nonce[4]
  PIN nonce[50]
    DIRECTION INPUT ;
    USE SIGNAL ;
    ANTENNAGATEAREA 0.196500 ;
    PORT
      LAYER met3 ;
        RECT 0.000 159.840 4.000 160.440 ;
    END
  END nonce[50]
  PIN nonce[51]
    DIRECTION INPUT ;
    USE SIGNAL ;
    ANTENNAGATEAREA 0.196500 ;
    PORT
      LAYER met2 ;
        RECT 196.510 0.000 196.790 4.000 ;
    END
  END nonce[51]
  PIN nonce[52]
    DIRECTION INPUT ;
    USE SIGNAL ;
    ANTENNAGATEAREA 0.196500 ;
    PORT
      LAYER met3 ;
        RECT 0.000 459.040 4.000 459.640 ;
    END
  END nonce[52]
  PIN nonce[53]
    DIRECTION INPUT ;
    USE SIGNAL ;
    ANTENNAGATEAREA 0.196500 ;
    PORT
      LAYER met3 ;
        RECT 0.000 340.040 4.000 340.640 ;
    END
  END nonce[53]
  PIN nonce[54]
    DIRECTION INPUT ;
    USE SIGNAL ;
    ANTENNAGATEAREA 0.196500 ;
    PORT
      LAYER met2 ;
        RECT 170.750 0.000 171.030 4.000 ;
    END
  END nonce[54]
  PIN nonce[55]
    DIRECTION INPUT ;
    USE SIGNAL ;
    ANTENNAGATEAREA 0.126000 ;
    PORT
      LAYER met2 ;
        RECT 119.230 0.000 119.510 4.000 ;
    END
  END nonce[55]
  PIN nonce[56]
    DIRECTION INPUT ;
    USE SIGNAL ;
    ANTENNAGATEAREA 0.196500 ;
    PORT
      LAYER met3 ;
        RECT 0.000 455.640 4.000 456.240 ;
    END
  END nonce[56]
  PIN nonce[57]
    DIRECTION INPUT ;
    USE SIGNAL ;
    ANTENNAGATEAREA 0.196500 ;
    PORT
      LAYER met3 ;
        RECT 0.000 244.840 4.000 245.440 ;
    END
  END nonce[57]
  PIN nonce[58]
    DIRECTION INPUT ;
    USE SIGNAL ;
    ANTENNAGATEAREA 0.196500 ;
    PORT
      LAYER met3 ;
        RECT 0.000 370.640 4.000 371.240 ;
    END
  END nonce[58]
  PIN nonce[59]
    DIRECTION INPUT ;
    USE SIGNAL ;
    ANTENNAGATEAREA 0.196500 ;
    PORT
      LAYER met2 ;
        RECT 132.110 0.000 132.390 4.000 ;
    END
  END nonce[59]
  PIN nonce[5]
    DIRECTION INPUT ;
    USE SIGNAL ;
    ANTENNAGATEAREA 0.196500 ;
    PORT
      LAYER met2 ;
        RECT 161.090 0.000 161.370 4.000 ;
    END
  END nonce[5]
  PIN nonce[60]
    DIRECTION INPUT ;
    USE SIGNAL ;
    ANTENNAGATEAREA 0.196500 ;
    PORT
      LAYER met3 ;
        RECT 0.000 445.440 4.000 446.040 ;
    END
  END nonce[60]
  PIN nonce[61]
    DIRECTION INPUT ;
    USE SIGNAL ;
    ANTENNAGATEAREA 0.213000 ;
    PORT
      LAYER met3 ;
        RECT 0.000 632.440 4.000 633.040 ;
    END
  END nonce[61]
  PIN nonce[62]
    DIRECTION INPUT ;
    USE SIGNAL ;
    ANTENNAGATEAREA 0.196500 ;
    PORT
      LAYER met2 ;
        RECT 186.850 0.000 187.130 4.000 ;
    END
  END nonce[62]
  PIN nonce[63]
    DIRECTION INPUT ;
    USE SIGNAL ;
    ANTENNAGATEAREA 0.196500 ;
    PORT
      LAYER met2 ;
        RECT 206.170 0.000 206.450 4.000 ;
    END
  END nonce[63]
  PIN nonce[64]
    DIRECTION INPUT ;
    USE SIGNAL ;
    ANTENNAGATEAREA 0.196500 ;
    PORT
      LAYER met3 ;
        RECT 0.000 612.040 4.000 612.640 ;
    END
  END nonce[64]
  PIN nonce[65]
    DIRECTION INPUT ;
    USE SIGNAL ;
    ANTENNAGATEAREA 0.196500 ;
    PORT
      LAYER met2 ;
        RECT 251.250 0.000 251.530 4.000 ;
    END
  END nonce[65]
  PIN nonce[66]
    DIRECTION INPUT ;
    USE SIGNAL ;
    ANTENNAGATEAREA 0.196500 ;
    PORT
      LAYER met2 ;
        RECT 267.350 0.000 267.630 4.000 ;
    END
  END nonce[66]
  PIN nonce[67]
    DIRECTION INPUT ;
    USE SIGNAL ;
    ANTENNAGATEAREA 0.196500 ;
    PORT
      LAYER met2 ;
        RECT 244.810 0.000 245.090 4.000 ;
    END
  END nonce[67]
  PIN nonce[68]
    DIRECTION INPUT ;
    USE SIGNAL ;
    ANTENNAGATEAREA 0.196500 ;
    PORT
      LAYER met3 ;
        RECT 0.000 401.240 4.000 401.840 ;
    END
  END nonce[68]
  PIN nonce[69]
    DIRECTION INPUT ;
    USE SIGNAL ;
    ANTENNAGATEAREA 0.196500 ;
    PORT
      LAYER met2 ;
        RECT 151.430 0.000 151.710 4.000 ;
    END
  END nonce[69]
  PIN nonce[6]
    DIRECTION INPUT ;
    USE SIGNAL ;
    ANTENNAGATEAREA 0.196500 ;
    PORT
      LAYER met2 ;
        RECT 122.450 0.000 122.730 4.000 ;
    END
  END nonce[6]
  PIN nonce[70]
    DIRECTION INPUT ;
    USE SIGNAL ;
    ANTENNAGATEAREA 0.196500 ;
    PORT
      LAYER met2 ;
        RECT 257.690 0.000 257.970 4.000 ;
    END
  END nonce[70]
  PIN nonce[71]
    DIRECTION INPUT ;
    USE SIGNAL ;
    ANTENNAGATEAREA 0.196500 ;
    PORT
      LAYER met2 ;
        RECT 177.190 0.000 177.470 4.000 ;
    END
  END nonce[71]
  PIN nonce[72]
    DIRECTION INPUT ;
    USE SIGNAL ;
    ANTENNAGATEAREA 0.196500 ;
    PORT
      LAYER met3 ;
        RECT 0.000 391.040 4.000 391.640 ;
    END
  END nonce[72]
  PIN nonce[73]
    DIRECTION INPUT ;
    USE SIGNAL ;
    ANTENNAGATEAREA 0.196500 ;
    PORT
      LAYER met3 ;
        RECT 0.000 306.040 4.000 306.640 ;
    END
  END nonce[73]
  PIN nonce[74]
    DIRECTION INPUT ;
    USE SIGNAL ;
    ANTENNAGATEAREA 0.196500 ;
    PORT
      LAYER met3 ;
        RECT 0.000 333.240 4.000 333.840 ;
    END
  END nonce[74]
  PIN nonce[75]
    DIRECTION INPUT ;
    USE SIGNAL ;
    ANTENNAGATEAREA 0.196500 ;
    PORT
      LAYER met2 ;
        RECT 241.590 0.000 241.870 4.000 ;
    END
  END nonce[75]
  PIN nonce[76]
    DIRECTION INPUT ;
    USE SIGNAL ;
    ANTENNAGATEAREA 0.196500 ;
    PORT
      LAYER met3 ;
        RECT 0.000 421.640 4.000 422.240 ;
    END
  END nonce[76]
  PIN nonce[77]
    DIRECTION INPUT ;
    USE SIGNAL ;
    ANTENNAGATEAREA 0.196500 ;
    PORT
      LAYER met2 ;
        RECT 138.550 0.000 138.830 4.000 ;
    END
  END nonce[77]
  PIN nonce[78]
    DIRECTION INPUT ;
    USE SIGNAL ;
    ANTENNAGATEAREA 0.196500 ;
    PORT
      LAYER met2 ;
        RECT 157.870 0.000 158.150 4.000 ;
    END
  END nonce[78]
  PIN nonce[79]
    DIRECTION INPUT ;
    USE SIGNAL ;
    ANTENNAGATEAREA 0.196500 ;
    PORT
      LAYER met2 ;
        RECT 193.290 0.000 193.570 4.000 ;
    END
  END nonce[79]
  PIN nonce[7]
    DIRECTION INPUT ;
    USE SIGNAL ;
    ANTENNAGATEAREA 0.196500 ;
    PORT
      LAYER met2 ;
        RECT 202.950 0.000 203.230 4.000 ;
    END
  END nonce[7]
  PIN nonce[80]
    DIRECTION INPUT ;
    USE SIGNAL ;
    ANTENNAGATEAREA 0.196500 ;
    PORT
      LAYER met3 ;
        RECT 0.000 469.240 4.000 469.840 ;
    END
  END nonce[80]
  PIN nonce[81]
    DIRECTION INPUT ;
    USE SIGNAL ;
    ANTENNAGATEAREA 0.196500 ;
    PORT
      LAYER met2 ;
        RECT 116.010 0.000 116.290 4.000 ;
    END
  END nonce[81]
  PIN nonce[82]
    DIRECTION INPUT ;
    USE SIGNAL ;
    ANTENNAGATEAREA 0.196500 ;
    PORT
      LAYER met3 ;
        RECT 0.000 227.840 4.000 228.440 ;
    END
  END nonce[82]
  PIN nonce[83]
    DIRECTION INPUT ;
    USE SIGNAL ;
    ANTENNAGATEAREA 0.196500 ;
    PORT
      LAYER met2 ;
        RECT 199.730 0.000 200.010 4.000 ;
    END
  END nonce[83]
  PIN nonce[84]
    DIRECTION INPUT ;
    USE SIGNAL ;
    ANTENNAGATEAREA 0.196500 ;
    PORT
      LAYER met3 ;
        RECT 0.000 564.440 4.000 565.040 ;
    END
  END nonce[84]
  PIN nonce[85]
    DIRECTION INPUT ;
    USE SIGNAL ;
    ANTENNAGATEAREA 0.196500 ;
    PORT
      LAYER met3 ;
        RECT 0.000 119.040 4.000 119.640 ;
    END
  END nonce[85]
  PIN nonce[86]
    DIRECTION INPUT ;
    USE SIGNAL ;
    ANTENNAGATEAREA 0.196500 ;
    PORT
      LAYER met2 ;
        RECT 167.530 0.000 167.810 4.000 ;
    END
  END nonce[86]
  PIN nonce[87]
    DIRECTION INPUT ;
    USE SIGNAL ;
    ANTENNAGATEAREA 0.196500 ;
    PORT
      LAYER met2 ;
        RECT 254.470 0.000 254.750 4.000 ;
    END
  END nonce[87]
  PIN nonce[88]
    DIRECTION INPUT ;
    USE SIGNAL ;
    ANTENNAGATEAREA 0.196500 ;
    PORT
      LAYER met3 ;
        RECT 0.000 452.240 4.000 452.840 ;
    END
  END nonce[88]
  PIN nonce[89]
    DIRECTION INPUT ;
    USE SIGNAL ;
    ANTENNAGATEAREA 0.196500 ;
    PORT
      LAYER met3 ;
        RECT 0.000 204.040 4.000 204.640 ;
    END
  END nonce[89]
  PIN nonce[8]
    DIRECTION INPUT ;
    USE SIGNAL ;
    ANTENNAGATEAREA 0.196500 ;
    PORT
      LAYER met3 ;
        RECT 0.000 629.040 4.000 629.640 ;
    END
  END nonce[8]
  PIN nonce[90]
    DIRECTION INPUT ;
    USE SIGNAL ;
    ANTENNAGATEAREA 0.196500 ;
    PORT
      LAYER met3 ;
        RECT 0.000 374.040 4.000 374.640 ;
    END
  END nonce[90]
  PIN nonce[91]
    DIRECTION INPUT ;
    USE SIGNAL ;
    ANTENNAGATEAREA 0.196500 ;
    PORT
      LAYER met2 ;
        RECT 112.790 0.000 113.070 4.000 ;
    END
  END nonce[91]
  PIN nonce[92]
    DIRECTION INPUT ;
    USE SIGNAL ;
    ANTENNAGATEAREA 0.196500 ;
    PORT
      LAYER met3 ;
        RECT 0.000 442.040 4.000 442.640 ;
    END
  END nonce[92]
  PIN nonce[93]
    DIRECTION INPUT ;
    USE SIGNAL ;
    ANTENNAGATEAREA 0.196500 ;
    PORT
      LAYER met3 ;
        RECT 0.000 387.640 4.000 388.240 ;
    END
  END nonce[93]
  PIN nonce[94]
    DIRECTION INPUT ;
    USE SIGNAL ;
    ANTENNAGATEAREA 0.196500 ;
    PORT
      LAYER met2 ;
        RECT 190.070 0.000 190.350 4.000 ;
    END
  END nonce[94]
  PIN nonce[95]
    DIRECTION INPUT ;
    USE SIGNAL ;
    ANTENNAGATEAREA 0.196500 ;
    PORT
      LAYER met2 ;
        RECT 215.830 0.000 216.110 4.000 ;
    END
  END nonce[95]
  PIN nonce[9]
    DIRECTION INPUT ;
    USE SIGNAL ;
    ANTENNAGATEAREA 0.196500 ;
    PORT
      LAYER met3 ;
        RECT 0.000 132.640 4.000 133.240 ;
    END
  END nonce[9]
  PIN rst_n
    DIRECTION INPUT ;
    USE SIGNAL ;
    ANTENNAGATEAREA 0.196500 ;
    PORT
      LAYER met2 ;
        RECT 74.150 696.000 74.430 700.000 ;
    END
  END rst_n
  PIN sel_type[0]
    DIRECTION INPUT ;
    USE SIGNAL ;
    ANTENNAGATEAREA 0.213000 ;
    PORT
      LAYER met2 ;
        RECT 624.770 696.000 625.050 700.000 ;
    END
  END sel_type[0]
  PIN sel_type[1]
    DIRECTION INPUT ;
    USE SIGNAL ;
    ANTENNAGATEAREA 0.213000 ;
    PORT
      LAYER met2 ;
        RECT 634.430 696.000 634.710 700.000 ;
    END
  END sel_type[1]
  PIN sel_type[2]
    DIRECTION INPUT ;
    USE SIGNAL ;
    ANTENNAGATEAREA 0.196500 ;
    PORT
      LAYER met2 ;
        RECT 376.830 696.000 377.110 700.000 ;
    END
  END sel_type[2]
  PIN tag[0]
    DIRECTION OUTPUT ;
    USE SIGNAL ;
    ANTENNADIFFAREA 0.445500 ;
    PORT
      LAYER met2 ;
        RECT 231.930 696.000 232.210 700.000 ;
    END
  END tag[0]
  PIN tag[10]
    DIRECTION OUTPUT ;
    USE SIGNAL ;
    ANTENNADIFFAREA 0.445500 ;
    PORT
      LAYER met2 ;
        RECT 293.110 696.000 293.390 700.000 ;
    END
  END tag[10]
  PIN tag[11]
    DIRECTION OUTPUT ;
    USE SIGNAL ;
    ANTENNADIFFAREA 0.445500 ;
    PORT
      LAYER met2 ;
        RECT 193.290 696.000 193.570 700.000 ;
    END
  END tag[11]
  PIN tag[12]
    DIRECTION OUTPUT ;
    USE SIGNAL ;
    ANTENNADIFFAREA 0.445500 ;
    PORT
      LAYER met2 ;
        RECT 544.270 696.000 544.550 700.000 ;
    END
  END tag[12]
  PIN tag[13]
    DIRECTION OUTPUT ;
    USE SIGNAL ;
    ANTENNADIFFAREA 0.445500 ;
    PORT
      LAYER met2 ;
        RECT 557.150 696.000 557.430 700.000 ;
    END
  END tag[13]
  PIN tag[14]
    DIRECTION OUTPUT ;
    USE SIGNAL ;
    ANTENNADIFFAREA 0.445500 ;
    PORT
      LAYER met2 ;
        RECT 161.090 696.000 161.370 700.000 ;
    END
  END tag[14]
  PIN tag[15]
    DIRECTION OUTPUT ;
    USE SIGNAL ;
    ANTENNADIFFAREA 0.445500 ;
    PORT
      LAYER met2 ;
        RECT 219.050 696.000 219.330 700.000 ;
    END
  END tag[15]
  PIN tag[16]
    DIRECTION OUTPUT ;
    USE SIGNAL ;
    ANTENNADIFFAREA 0.445500 ;
    PORT
      LAYER met2 ;
        RECT 183.630 696.000 183.910 700.000 ;
    END
  END tag[16]
  PIN tag[17]
    DIRECTION OUTPUT ;
    USE SIGNAL ;
    ANTENNADIFFAREA 0.445500 ;
    PORT
      LAYER met2 ;
        RECT 476.650 696.000 476.930 700.000 ;
    END
  END tag[17]
  PIN tag[18]
    DIRECTION OUTPUT ;
    USE SIGNAL ;
    ANTENNADIFFAREA 0.445500 ;
    PORT
      LAYER met2 ;
        RECT 280.230 696.000 280.510 700.000 ;
    END
  END tag[18]
  PIN tag[19]
    DIRECTION OUTPUT ;
    USE SIGNAL ;
    ANTENNADIFFAREA 0.445500 ;
    PORT
      LAYER met2 ;
        RECT 209.390 696.000 209.670 700.000 ;
    END
  END tag[19]
  PIN tag[1]
    DIRECTION OUTPUT ;
    USE SIGNAL ;
    ANTENNADIFFAREA 0.445500 ;
    PORT
      LAYER met2 ;
        RECT 653.750 696.000 654.030 700.000 ;
    END
  END tag[1]
  PIN tag[20]
    DIRECTION OUTPUT ;
    USE SIGNAL ;
    ANTENNADIFFAREA 0.445500 ;
    PORT
      LAYER met2 ;
        RECT 466.990 696.000 467.270 700.000 ;
    END
  END tag[20]
  PIN tag[21]
    DIRECTION OUTPUT ;
    USE SIGNAL ;
    ANTENNADIFFAREA 0.445500 ;
    PORT
      LAYER met2 ;
        RECT 595.790 696.000 596.070 700.000 ;
    END
  END tag[21]
  PIN tag[22]
    DIRECTION OUTPUT ;
    USE SIGNAL ;
    ANTENNADIFFAREA 0.445500 ;
    PORT
      LAYER met2 ;
        RECT 222.270 696.000 222.550 700.000 ;
    END
  END tag[22]
  PIN tag[23]
    DIRECTION OUTPUT ;
    USE SIGNAL ;
    ANTENNADIFFAREA 0.445500 ;
    PORT
      LAYER met2 ;
        RECT 518.510 696.000 518.790 700.000 ;
    END
  END tag[23]
  PIN tag[24]
    DIRECTION OUTPUT ;
    USE SIGNAL ;
    ANTENNADIFFAREA 0.445500 ;
    PORT
      LAYER met2 ;
        RECT 315.650 696.000 315.930 700.000 ;
    END
  END tag[24]
  PIN tag[25]
    DIRECTION OUTPUT ;
    USE SIGNAL ;
    ANTENNADIFFAREA 0.445500 ;
    PORT
      LAYER met2 ;
        RECT 357.510 696.000 357.790 700.000 ;
    END
  END tag[25]
  PIN tag[26]
    DIRECTION OUTPUT ;
    USE SIGNAL ;
    ANTENNADIFFAREA 0.445500 ;
    PORT
      LAYER met2 ;
        RECT 157.870 696.000 158.150 700.000 ;
    END
  END tag[26]
  PIN tag[27]
    DIRECTION OUTPUT ;
    USE SIGNAL ;
    ANTENNADIFFAREA 0.445500 ;
    PORT
      LAYER met2 ;
        RECT 99.910 696.000 100.190 700.000 ;
    END
  END tag[27]
  PIN tag[28]
    DIRECTION OUTPUT ;
    USE SIGNAL ;
    ANTENNADIFFAREA 0.445500 ;
    PORT
      LAYER met2 ;
        RECT 470.210 696.000 470.490 700.000 ;
    END
  END tag[28]
  PIN tag[29]
    DIRECTION OUTPUT ;
    USE SIGNAL ;
    ANTENNADIFFAREA 0.445500 ;
    PORT
      LAYER met2 ;
        RECT 473.430 696.000 473.710 700.000 ;
    END
  END tag[29]
  PIN tag[2]
    DIRECTION OUTPUT ;
    USE SIGNAL ;
    ANTENNADIFFAREA 0.445500 ;
    PORT
      LAYER met2 ;
        RECT 180.410 696.000 180.690 700.000 ;
    END
  END tag[2]
  PIN tag[30]
    DIRECTION OUTPUT ;
    USE SIGNAL ;
    ANTENNADIFFAREA 0.445500 ;
    PORT
      LAYER met2 ;
        RECT 463.770 696.000 464.050 700.000 ;
    END
  END tag[30]
  PIN tag[31]
    DIRECTION OUTPUT ;
    USE SIGNAL ;
    ANTENNADIFFAREA 0.445500 ;
    PORT
      LAYER met2 ;
        RECT 415.470 696.000 415.750 700.000 ;
    END
  END tag[31]
  PIN tag[32]
    DIRECTION OUTPUT ;
    USE SIGNAL ;
    ANTENNADIFFAREA 0.445500 ;
    PORT
      LAYER met2 ;
        RECT 531.390 696.000 531.670 700.000 ;
    END
  END tag[32]
  PIN tag[33]
    DIRECTION OUTPUT ;
    USE SIGNAL ;
    ANTENNADIFFAREA 0.445500 ;
    PORT
      LAYER met2 ;
        RECT 122.450 696.000 122.730 700.000 ;
    END
  END tag[33]
  PIN tag[34]
    DIRECTION OUTPUT ;
    USE SIGNAL ;
    ANTENNADIFFAREA 0.445500 ;
    PORT
      LAYER met2 ;
        RECT 260.910 696.000 261.190 700.000 ;
    END
  END tag[34]
  PIN tag[35]
    DIRECTION OUTPUT ;
    USE SIGNAL ;
    ANTENNADIFFAREA 0.445500 ;
    PORT
      LAYER met2 ;
        RECT 135.330 696.000 135.610 700.000 ;
    END
  END tag[35]
  PIN tag[36]
    DIRECTION OUTPUT ;
    USE SIGNAL ;
    ANTENNADIFFAREA 0.445500 ;
    PORT
      LAYER met2 ;
        RECT 318.870 696.000 319.150 700.000 ;
    END
  END tag[36]
  PIN tag[37]
    DIRECTION OUTPUT ;
    USE SIGNAL ;
    ANTENNADIFFAREA 0.445500 ;
    PORT
      LAYER met2 ;
        RECT 296.330 696.000 296.610 700.000 ;
    END
  END tag[37]
  PIN tag[38]
    DIRECTION OUTPUT ;
    USE SIGNAL ;
    ANTENNADIFFAREA 0.445500 ;
    PORT
      LAYER met2 ;
        RECT 618.330 696.000 618.610 700.000 ;
    END
  END tag[38]
  PIN tag[39]
    DIRECTION OUTPUT ;
    USE SIGNAL ;
    ANTENNADIFFAREA 0.445500 ;
    PORT
      LAYER met2 ;
        RECT 541.050 696.000 541.330 700.000 ;
    END
  END tag[39]
  PIN tag[3]
    DIRECTION OUTPUT ;
    USE SIGNAL ;
    ANTENNADIFFAREA 0.445500 ;
    PORT
      LAYER met2 ;
        RECT 225.490 696.000 225.770 700.000 ;
    END
  END tag[3]
  PIN tag[40]
    DIRECTION OUTPUT ;
    USE SIGNAL ;
    ANTENNADIFFAREA 0.445500 ;
    PORT
      LAYER met2 ;
        RECT 627.990 696.000 628.270 700.000 ;
    END
  END tag[40]
  PIN tag[41]
    DIRECTION OUTPUT ;
    USE SIGNAL ;
    ANTENNADIFFAREA 0.445500 ;
    PORT
      LAYER met2 ;
        RECT 441.230 696.000 441.510 700.000 ;
    END
  END tag[41]
  PIN tag[42]
    DIRECTION OUTPUT ;
    USE SIGNAL ;
    ANTENNADIFFAREA 0.445500 ;
    PORT
      LAYER met2 ;
        RECT 228.710 696.000 228.990 700.000 ;
    END
  END tag[42]
  PIN tag[43]
    DIRECTION OUTPUT ;
    USE SIGNAL ;
    ANTENNADIFFAREA 0.445500 ;
    PORT
      LAYER met2 ;
        RECT 144.990 696.000 145.270 700.000 ;
    END
  END tag[43]
  PIN tag[44]
    DIRECTION OUTPUT ;
    USE SIGNAL ;
    ANTENNADIFFAREA 0.445500 ;
    PORT
      LAYER met2 ;
        RECT 457.330 696.000 457.610 700.000 ;
    END
  END tag[44]
  PIN tag[45]
    DIRECTION OUTPUT ;
    USE SIGNAL ;
    ANTENNADIFFAREA 0.445500 ;
    PORT
      LAYER met2 ;
        RECT 173.970 696.000 174.250 700.000 ;
    END
  END tag[45]
  PIN tag[46]
    DIRECTION OUTPUT ;
    USE SIGNAL ;
    ANTENNADIFFAREA 0.445500 ;
    PORT
      LAYER met2 ;
        RECT 515.290 696.000 515.570 700.000 ;
    END
  END tag[46]
  PIN tag[47]
    DIRECTION OUTPUT ;
    USE SIGNAL ;
    ANTENNADIFFAREA 0.445500 ;
    PORT
      LAYER met2 ;
        RECT 460.550 696.000 460.830 700.000 ;
    END
  END tag[47]
  PIN tag[48]
    DIRECTION OUTPUT ;
    USE SIGNAL ;
    ANTENNADIFFAREA 0.445500 ;
    PORT
      LAYER met2 ;
        RECT 103.130 696.000 103.410 700.000 ;
    END
  END tag[48]
  PIN tag[49]
    DIRECTION OUTPUT ;
    USE SIGNAL ;
    ANTENNADIFFAREA 0.445500 ;
    PORT
      LAYER met2 ;
        RECT 347.850 696.000 348.130 700.000 ;
    END
  END tag[49]
  PIN tag[4]
    DIRECTION OUTPUT ;
    USE SIGNAL ;
    ANTENNADIFFAREA 0.445500 ;
    PORT
      LAYER met2 ;
        RECT 215.830 696.000 216.110 700.000 ;
    END
  END tag[4]
  PIN tag[50]
    DIRECTION OUTPUT ;
    USE SIGNAL ;
    ANTENNADIFFAREA 0.445500 ;
    PORT
      LAYER met2 ;
        RECT 341.410 696.000 341.690 700.000 ;
    END
  END tag[50]
  PIN tag[51]
    DIRECTION OUTPUT ;
    USE SIGNAL ;
    ANTENNADIFFAREA 0.445500 ;
    PORT
      LAYER met2 ;
        RECT 257.690 696.000 257.970 700.000 ;
    END
  END tag[51]
  PIN tag[52]
    DIRECTION OUTPUT ;
    USE SIGNAL ;
    ANTENNADIFFAREA 0.445500 ;
    PORT
      LAYER met2 ;
        RECT 344.630 696.000 344.910 700.000 ;
    END
  END tag[52]
  PIN tag[53]
    DIRECTION OUTPUT ;
    USE SIGNAL ;
    ANTENNADIFFAREA 0.445500 ;
    PORT
      LAYER met2 ;
        RECT 421.910 696.000 422.190 700.000 ;
    END
  END tag[53]
  PIN tag[54]
    DIRECTION OUTPUT ;
    USE SIGNAL ;
    ANTENNADIFFAREA 0.445500 ;
    PORT
      LAYER met2 ;
        RECT 106.350 696.000 106.630 700.000 ;
    END
  END tag[54]
  PIN tag[55]
    DIRECTION OUTPUT ;
    USE SIGNAL ;
    ANTENNADIFFAREA 0.445500 ;
    PORT
      LAYER met2 ;
        RECT 447.670 696.000 447.950 700.000 ;
    END
  END tag[55]
  PIN tag[56]
    DIRECTION OUTPUT ;
    USE SIGNAL ;
    ANTENNADIFFAREA 0.445500 ;
    PORT
      LAYER met2 ;
        RECT 367.170 696.000 367.450 700.000 ;
    END
  END tag[56]
  PIN tag[57]
    DIRECTION OUTPUT ;
    USE SIGNAL ;
    ANTENNADIFFAREA 0.445500 ;
    PORT
      LAYER met2 ;
        RECT 151.430 696.000 151.710 700.000 ;
    END
  END tag[57]
  PIN tag[58]
    DIRECTION OUTPUT ;
    USE SIGNAL ;
    ANTENNADIFFAREA 0.445500 ;
    PORT
      LAYER met2 ;
        RECT 251.250 696.000 251.530 700.000 ;
    END
  END tag[58]
  PIN tag[59]
    DIRECTION OUTPUT ;
    USE SIGNAL ;
    ANTENNADIFFAREA 0.445500 ;
    PORT
      LAYER met2 ;
        RECT 241.590 696.000 241.870 700.000 ;
    END
  END tag[59]
  PIN tag[5]
    DIRECTION OUTPUT ;
    USE SIGNAL ;
    ANTENNADIFFAREA 0.445500 ;
    PORT
      LAYER met2 ;
        RECT 302.770 696.000 303.050 700.000 ;
    END
  END tag[5]
  PIN tag[60]
    DIRECTION OUTPUT ;
    USE SIGNAL ;
    ANTENNADIFFAREA 0.445500 ;
    PORT
      LAYER met2 ;
        RECT 528.170 696.000 528.450 700.000 ;
    END
  END tag[60]
  PIN tag[61]
    DIRECTION OUTPUT ;
    USE SIGNAL ;
    ANTENNADIFFAREA 0.445500 ;
    PORT
      LAYER met2 ;
        RECT 450.890 696.000 451.170 700.000 ;
    END
  END tag[61]
  PIN tag[62]
    DIRECTION OUTPUT ;
    USE SIGNAL ;
    ANTENNADIFFAREA 0.445500 ;
    PORT
      LAYER met2 ;
        RECT 264.130 696.000 264.410 700.000 ;
    END
  END tag[62]
  PIN tag[63]
    DIRECTION OUTPUT ;
    USE SIGNAL ;
    ANTENNADIFFAREA 0.445500 ;
    PORT
      LAYER met2 ;
        RECT 534.610 696.000 534.890 700.000 ;
    END
  END tag[63]
  PIN tag[6]
    DIRECTION OUTPUT ;
    USE SIGNAL ;
    ANTENNADIFFAREA 0.445500 ;
    PORT
      LAYER met2 ;
        RECT 109.570 696.000 109.850 700.000 ;
    END
  END tag[6]
  PIN tag[7]
    DIRECTION OUTPUT ;
    USE SIGNAL ;
    ANTENNADIFFAREA 0.445500 ;
    PORT
      LAYER met2 ;
        RECT 576.470 696.000 576.750 700.000 ;
    END
  END tag[7]
  PIN tag[8]
    DIRECTION OUTPUT ;
    USE SIGNAL ;
    ANTENNADIFFAREA 0.445500 ;
    PORT
      LAYER met2 ;
        RECT 164.310 696.000 164.590 700.000 ;
    END
  END tag[8]
  PIN tag[9]
    DIRECTION OUTPUT ;
    USE SIGNAL ;
    ANTENNADIFFAREA 0.445500 ;
    PORT
      LAYER met2 ;
        RECT 521.730 696.000 522.010 700.000 ;
    END
  END tag[9]
  PIN tag_in[0]
    DIRECTION INPUT ;
    USE SIGNAL ;
    ANTENNAGATEAREA 0.196500 ;
    PORT
      LAYER met2 ;
        RECT 273.790 696.000 274.070 700.000 ;
    END
  END tag_in[0]
  PIN tag_in[10]
    DIRECTION INPUT ;
    USE SIGNAL ;
    ANTENNAGATEAREA 0.196500 ;
    PORT
      LAYER met2 ;
        RECT 277.010 696.000 277.290 700.000 ;
    END
  END tag_in[10]
  PIN tag_in[11]
    DIRECTION INPUT ;
    USE SIGNAL ;
    ANTENNAGATEAREA 0.196500 ;
    PORT
      LAYER met2 ;
        RECT 254.470 696.000 254.750 700.000 ;
    END
  END tag_in[11]
  PIN tag_in[12]
    DIRECTION INPUT ;
    USE SIGNAL ;
    ANTENNAGATEAREA 0.196500 ;
    PORT
      LAYER met2 ;
        RECT 396.150 696.000 396.430 700.000 ;
    END
  END tag_in[12]
  PIN tag_in[13]
    DIRECTION INPUT ;
    USE SIGNAL ;
    ANTENNAGATEAREA 0.196500 ;
    PORT
      LAYER met2 ;
        RECT 582.910 696.000 583.190 700.000 ;
    END
  END tag_in[13]
  PIN tag_in[14]
    DIRECTION INPUT ;
    USE SIGNAL ;
    ANTENNAGATEAREA 0.196500 ;
    PORT
      LAYER met2 ;
        RECT 244.810 696.000 245.090 700.000 ;
    END
  END tag_in[14]
  PIN tag_in[15]
    DIRECTION INPUT ;
    USE SIGNAL ;
    ANTENNAGATEAREA 0.196500 ;
    PORT
      LAYER met2 ;
        RECT 363.950 696.000 364.230 700.000 ;
    END
  END tag_in[15]
  PIN tag_in[16]
    DIRECTION INPUT ;
    USE SIGNAL ;
    ANTENNAGATEAREA 0.196500 ;
    PORT
      LAYER met2 ;
        RECT 373.610 696.000 373.890 700.000 ;
    END
  END tag_in[16]
  PIN tag_in[17]
    DIRECTION INPUT ;
    USE SIGNAL ;
    ANTENNAGATEAREA 0.196500 ;
    PORT
      LAYER met2 ;
        RECT 644.090 696.000 644.370 700.000 ;
    END
  END tag_in[17]
  PIN tag_in[18]
    DIRECTION INPUT ;
    USE SIGNAL ;
    ANTENNAGATEAREA 0.196500 ;
    PORT
      LAYER met2 ;
        RECT 334.970 696.000 335.250 700.000 ;
    END
  END tag_in[18]
  PIN tag_in[19]
    DIRECTION INPUT ;
    USE SIGNAL ;
    ANTENNAGATEAREA 0.196500 ;
    PORT
      LAYER met2 ;
        RECT 270.570 696.000 270.850 700.000 ;
    END
  END tag_in[19]
  PIN tag_in[1]
    DIRECTION INPUT ;
    USE SIGNAL ;
    ANTENNAGATEAREA 0.196500 ;
    PORT
      LAYER met2 ;
        RECT 656.970 696.000 657.250 700.000 ;
    END
  END tag_in[1]
  PIN tag_in[20]
    DIRECTION INPUT ;
    USE SIGNAL ;
    ANTENNAGATEAREA 0.196500 ;
    PORT
      LAYER met2 ;
        RECT 483.090 696.000 483.370 700.000 ;
    END
  END tag_in[20]
  PIN tag_in[21]
    DIRECTION INPUT ;
    USE SIGNAL ;
    ANTENNAGATEAREA 0.213000 ;
    PORT
      LAYER met2 ;
        RECT 631.210 696.000 631.490 700.000 ;
    END
  END tag_in[21]
  PIN tag_in[22]
    DIRECTION INPUT ;
    USE SIGNAL ;
    ANTENNAGATEAREA 0.196500 ;
    PORT
      LAYER met2 ;
        RECT 325.310 696.000 325.590 700.000 ;
    END
  END tag_in[22]
  PIN tag_in[23]
    DIRECTION INPUT ;
    USE SIGNAL ;
    ANTENNAGATEAREA 0.196500 ;
    PORT
      LAYER met2 ;
        RECT 550.710 696.000 550.990 700.000 ;
    END
  END tag_in[23]
  PIN tag_in[24]
    DIRECTION INPUT ;
    USE SIGNAL ;
    ANTENNAGATEAREA 0.196500 ;
    PORT
      LAYER met2 ;
        RECT 305.990 696.000 306.270 700.000 ;
    END
  END tag_in[24]
  PIN tag_in[25]
    DIRECTION INPUT ;
    USE SIGNAL ;
    ANTENNAGATEAREA 0.196500 ;
    PORT
      LAYER met2 ;
        RECT 351.070 696.000 351.350 700.000 ;
    END
  END tag_in[25]
  PIN tag_in[26]
    DIRECTION INPUT ;
    USE SIGNAL ;
    ANTENNAGATEAREA 0.196500 ;
    PORT
      LAYER met2 ;
        RECT 286.670 696.000 286.950 700.000 ;
    END
  END tag_in[26]
  PIN tag_in[27]
    DIRECTION INPUT ;
    USE SIGNAL ;
    ANTENNAGATEAREA 0.196500 ;
    PORT
      LAYER met2 ;
        RECT 119.230 696.000 119.510 700.000 ;
    END
  END tag_in[27]
  PIN tag_in[28]
    DIRECTION INPUT ;
    USE SIGNAL ;
    ANTENNAGATEAREA 0.196500 ;
    PORT
      LAYER met2 ;
        RECT 566.810 696.000 567.090 700.000 ;
    END
  END tag_in[28]
  PIN tag_in[29]
    DIRECTION INPUT ;
    USE SIGNAL ;
    ANTENNAGATEAREA 0.213000 ;
    PORT
      LAYER met2 ;
        RECT 77.370 696.000 77.650 700.000 ;
    END
  END tag_in[29]
  PIN tag_in[2]
    DIRECTION INPUT ;
    USE SIGNAL ;
    ANTENNAGATEAREA 0.196500 ;
    PORT
      LAYER met2 ;
        RECT 196.510 696.000 196.790 700.000 ;
    END
  END tag_in[2]
  PIN tag_in[30]
    DIRECTION INPUT ;
    USE SIGNAL ;
    ANTENNAGATEAREA 0.196500 ;
    PORT
      LAYER met2 ;
        RECT 454.110 696.000 454.390 700.000 ;
    END
  END tag_in[30]
  PIN tag_in[31]
    DIRECTION INPUT ;
    USE SIGNAL ;
    ANTENNAGATEAREA 0.213000 ;
    PORT
      LAYER met2 ;
        RECT 599.010 696.000 599.290 700.000 ;
    END
  END tag_in[31]
  PIN tag_in[32]
    DIRECTION INPUT ;
    USE SIGNAL ;
    ANTENNAGATEAREA 0.196500 ;
    PORT
      LAYER met2 ;
        RECT 409.030 696.000 409.310 700.000 ;
    END
  END tag_in[32]
  PIN tag_in[33]
    DIRECTION INPUT ;
    USE SIGNAL ;
    ANTENNAGATEAREA 0.196500 ;
    PORT
      LAYER met2 ;
        RECT 141.770 696.000 142.050 700.000 ;
    END
  END tag_in[33]
  PIN tag_in[34]
    DIRECTION INPUT ;
    USE SIGNAL ;
    ANTENNAGATEAREA 0.196500 ;
    PORT
      LAYER met2 ;
        RECT 87.030 696.000 87.310 700.000 ;
    END
  END tag_in[34]
  PIN tag_in[35]
    DIRECTION INPUT ;
    USE SIGNAL ;
    ANTENNAGATEAREA 0.196500 ;
    PORT
      LAYER met2 ;
        RECT 299.550 696.000 299.830 700.000 ;
    END
  END tag_in[35]
  PIN tag_in[36]
    DIRECTION INPUT ;
    USE SIGNAL ;
    ANTENNAGATEAREA 0.196500 ;
    PORT
      LAYER met2 ;
        RECT 328.530 696.000 328.810 700.000 ;
    END
  END tag_in[36]
  PIN tag_in[37]
    DIRECTION INPUT ;
    USE SIGNAL ;
    ANTENNAGATEAREA 0.196500 ;
    PORT
      LAYER met2 ;
        RECT 170.750 696.000 171.030 700.000 ;
    END
  END tag_in[37]
  PIN tag_in[38]
    DIRECTION INPUT ;
    USE SIGNAL ;
    ANTENNAGATEAREA 0.196500 ;
    PORT
      LAYER met2 ;
        RECT 383.270 696.000 383.550 700.000 ;
    END
  END tag_in[38]
  PIN tag_in[39]
    DIRECTION INPUT ;
    USE SIGNAL ;
    ANTENNAGATEAREA 0.196500 ;
    PORT
      LAYER met2 ;
        RECT 570.030 696.000 570.310 700.000 ;
    END
  END tag_in[39]
  PIN tag_in[3]
    DIRECTION INPUT ;
    USE SIGNAL ;
    ANTENNAGATEAREA 0.196500 ;
    PORT
      LAYER met2 ;
        RECT 235.150 696.000 235.430 700.000 ;
    END
  END tag_in[3]
  PIN tag_in[40]
    DIRECTION INPUT ;
    USE SIGNAL ;
    ANTENNAGATEAREA 0.196500 ;
    PORT
      LAYER met2 ;
        RECT 602.230 696.000 602.510 700.000 ;
    END
  END tag_in[40]
  PIN tag_in[41]
    DIRECTION INPUT ;
    USE SIGNAL ;
    ANTENNAGATEAREA 0.196500 ;
    PORT
      LAYER met2 ;
        RECT 492.750 696.000 493.030 700.000 ;
    END
  END tag_in[41]
  PIN tag_in[42]
    DIRECTION INPUT ;
    USE SIGNAL ;
    ANTENNAGATEAREA 0.196500 ;
    PORT
      LAYER met2 ;
        RECT 93.470 696.000 93.750 700.000 ;
    END
  END tag_in[42]
  PIN tag_in[43]
    DIRECTION INPUT ;
    USE SIGNAL ;
    ANTENNAGATEAREA 0.196500 ;
    PORT
      LAYER met2 ;
        RECT 283.450 696.000 283.730 700.000 ;
    END
  END tag_in[43]
  PIN tag_in[44]
    DIRECTION INPUT ;
    USE SIGNAL ;
    ANTENNAGATEAREA 0.196500 ;
    PORT
      LAYER met2 ;
        RECT 438.010 696.000 438.290 700.000 ;
    END
  END tag_in[44]
  PIN tag_in[45]
    DIRECTION INPUT ;
    USE SIGNAL ;
    ANTENNAGATEAREA 0.196500 ;
    PORT
      LAYER met2 ;
        RECT 112.790 696.000 113.070 700.000 ;
    END
  END tag_in[45]
  PIN tag_in[46]
    DIRECTION INPUT ;
    USE SIGNAL ;
    ANTENNAGATEAREA 0.196500 ;
    PORT
      LAYER met2 ;
        RECT 399.370 696.000 399.650 700.000 ;
    END
  END tag_in[46]
  PIN tag_in[47]
    DIRECTION INPUT ;
    USE SIGNAL ;
    ANTENNAGATEAREA 0.196500 ;
    PORT
      LAYER met2 ;
        RECT 489.530 696.000 489.810 700.000 ;
    END
  END tag_in[47]
  PIN tag_in[48]
    DIRECTION INPUT ;
    USE SIGNAL ;
    ANTENNAGATEAREA 0.196500 ;
    PORT
      LAYER met2 ;
        RECT 177.190 696.000 177.470 700.000 ;
    END
  END tag_in[48]
  PIN tag_in[49]
    DIRECTION INPUT ;
    USE SIGNAL ;
    ANTENNAGATEAREA 0.196500 ;
    PORT
      LAYER met2 ;
        RECT 331.750 696.000 332.030 700.000 ;
    END
  END tag_in[49]
  PIN tag_in[4]
    DIRECTION INPUT ;
    USE SIGNAL ;
    ANTENNAGATEAREA 0.196500 ;
    PORT
      LAYER met2 ;
        RECT 186.850 696.000 187.130 700.000 ;
    END
  END tag_in[4]
  PIN tag_in[50]
    DIRECTION INPUT ;
    USE SIGNAL ;
    ANTENNAGATEAREA 0.196500 ;
    PORT
      LAYER met2 ;
        RECT 322.090 696.000 322.370 700.000 ;
    END
  END tag_in[50]
  PIN tag_in[51]
    DIRECTION INPUT ;
    USE SIGNAL ;
    ANTENNAGATEAREA 0.196500 ;
    PORT
      LAYER met2 ;
        RECT 238.370 696.000 238.650 700.000 ;
    END
  END tag_in[51]
  PIN tag_in[52]
    DIRECTION INPUT ;
    USE SIGNAL ;
    ANTENNAGATEAREA 0.196500 ;
    PORT
      LAYER met2 ;
        RECT 338.190 696.000 338.470 700.000 ;
    END
  END tag_in[52]
  PIN tag_in[53]
    DIRECTION INPUT ;
    USE SIGNAL ;
    ANTENNAGATEAREA 0.159000 ;
    PORT
      LAYER met2 ;
        RECT 647.310 696.000 647.590 700.000 ;
    END
  END tag_in[53]
  PIN tag_in[54]
    DIRECTION INPUT ;
    USE SIGNAL ;
    ANTENNAGATEAREA 0.196500 ;
    PORT
      LAYER met2 ;
        RECT 96.690 696.000 96.970 700.000 ;
    END
  END tag_in[54]
  PIN tag_in[55]
    DIRECTION INPUT ;
    USE SIGNAL ;
    ANTENNAGATEAREA 0.196500 ;
    PORT
      LAYER met2 ;
        RECT 434.790 696.000 435.070 700.000 ;
    END
  END tag_in[55]
  PIN tag_in[56]
    DIRECTION INPUT ;
    USE SIGNAL ;
    ANTENNAGATEAREA 0.196500 ;
    PORT
      LAYER met2 ;
        RECT 354.290 696.000 354.570 700.000 ;
    END
  END tag_in[56]
  PIN tag_in[57]
    DIRECTION INPUT ;
    USE SIGNAL ;
    ANTENNAGATEAREA 0.196500 ;
    PORT
      LAYER met2 ;
        RECT 267.350 696.000 267.630 700.000 ;
    END
  END tag_in[57]
  PIN tag_in[58]
    DIRECTION INPUT ;
    USE SIGNAL ;
    ANTENNAGATEAREA 0.196500 ;
    PORT
      LAYER met2 ;
        RECT 167.530 696.000 167.810 700.000 ;
    END
  END tag_in[58]
  PIN tag_in[59]
    DIRECTION INPUT ;
    USE SIGNAL ;
    ANTENNAGATEAREA 0.196500 ;
    PORT
      LAYER met2 ;
        RECT 138.550 696.000 138.830 700.000 ;
    END
  END tag_in[59]
  PIN tag_in[5]
    DIRECTION INPUT ;
    USE SIGNAL ;
    ANTENNAGATEAREA 0.196500 ;
    PORT
      LAYER met2 ;
        RECT 125.670 696.000 125.950 700.000 ;
    END
  END tag_in[5]
  PIN tag_in[60]
    DIRECTION INPUT ;
    USE SIGNAL ;
    ANTENNAGATEAREA 0.196500 ;
    PORT
      LAYER met2 ;
        RECT 589.350 696.000 589.630 700.000 ;
    END
  END tag_in[60]
  PIN tag_in[61]
    DIRECTION INPUT ;
    USE SIGNAL ;
    ANTENNAGATEAREA 0.196500 ;
    PORT
      LAYER met2 ;
        RECT 537.830 696.000 538.110 700.000 ;
    END
  END tag_in[61]
  PIN tag_in[62]
    DIRECTION INPUT ;
    USE SIGNAL ;
    ANTENNAGATEAREA 0.196500 ;
    PORT
      LAYER met2 ;
        RECT 202.950 696.000 203.230 700.000 ;
    END
  END tag_in[62]
  PIN tag_in[63]
    DIRECTION INPUT ;
    USE SIGNAL ;
    ANTENNAGATEAREA 0.196500 ;
    PORT
      LAYER met2 ;
        RECT 431.570 696.000 431.850 700.000 ;
    END
  END tag_in[63]
  PIN tag_in[6]
    DIRECTION INPUT ;
    USE SIGNAL ;
    ANTENNAGATEAREA 0.196500 ;
    PORT
      LAYER met2 ;
        RECT 199.730 696.000 200.010 700.000 ;
    END
  END tag_in[6]
  PIN tag_in[7]
    DIRECTION INPUT ;
    USE SIGNAL ;
    ANTENNAGATEAREA 0.196500 ;
    PORT
      LAYER met2 ;
        RECT 586.130 696.000 586.410 700.000 ;
    END
  END tag_in[7]
  PIN tag_in[8]
    DIRECTION INPUT ;
    USE SIGNAL ;
    ANTENNAGATEAREA 0.196500 ;
    PORT
      LAYER met2 ;
        RECT 154.650 696.000 154.930 700.000 ;
    END
  END tag_in[8]
  PIN tag_in[9]
    DIRECTION INPUT ;
    USE SIGNAL ;
    ANTENNAGATEAREA 0.196500 ;
    PORT
      LAYER met2 ;
        RECT 502.410 696.000 502.690 700.000 ;
    END
  END tag_in[9]
  PIN valid
    DIRECTION OUTPUT ;
    USE SIGNAL ;
    ANTENNADIFFAREA 0.445500 ;
    PORT
      LAYER met2 ;
        RECT 386.490 696.000 386.770 700.000 ;
    END
  END valid
  OBS
      LAYER nwell ;
        RECT 5.330 10.795 694.330 688.350 ;
      LAYER li1 ;
        RECT 5.520 10.795 694.140 688.245 ;
      LAYER met1 ;
        RECT 1.450 6.840 699.130 689.480 ;
      LAYER met2 ;
        RECT 0.650 695.720 3.030 696.730 ;
        RECT 3.870 695.720 6.250 696.730 ;
        RECT 7.090 695.720 9.470 696.730 ;
        RECT 10.310 695.720 12.690 696.730 ;
        RECT 13.530 695.720 15.910 696.730 ;
        RECT 16.750 695.720 19.130 696.730 ;
        RECT 19.970 695.720 22.350 696.730 ;
        RECT 23.190 695.720 25.570 696.730 ;
        RECT 26.410 695.720 28.790 696.730 ;
        RECT 29.630 695.720 32.010 696.730 ;
        RECT 32.850 695.720 35.230 696.730 ;
        RECT 36.070 695.720 38.450 696.730 ;
        RECT 39.290 695.720 41.670 696.730 ;
        RECT 42.510 695.720 44.890 696.730 ;
        RECT 45.730 695.720 48.110 696.730 ;
        RECT 48.950 695.720 51.330 696.730 ;
        RECT 52.170 695.720 54.550 696.730 ;
        RECT 55.390 695.720 67.430 696.730 ;
        RECT 68.270 695.720 70.650 696.730 ;
        RECT 71.490 695.720 73.870 696.730 ;
        RECT 74.710 695.720 77.090 696.730 ;
        RECT 77.930 695.720 80.310 696.730 ;
        RECT 81.150 695.720 83.530 696.730 ;
        RECT 84.370 695.720 86.750 696.730 ;
        RECT 87.590 695.720 89.970 696.730 ;
        RECT 90.810 695.720 93.190 696.730 ;
        RECT 94.030 695.720 96.410 696.730 ;
        RECT 97.250 695.720 99.630 696.730 ;
        RECT 100.470 695.720 102.850 696.730 ;
        RECT 103.690 695.720 106.070 696.730 ;
        RECT 106.910 695.720 109.290 696.730 ;
        RECT 110.130 695.720 112.510 696.730 ;
        RECT 113.350 695.720 115.730 696.730 ;
        RECT 116.570 695.720 118.950 696.730 ;
        RECT 119.790 695.720 122.170 696.730 ;
        RECT 123.010 695.720 125.390 696.730 ;
        RECT 126.230 695.720 128.610 696.730 ;
        RECT 129.450 695.720 131.830 696.730 ;
        RECT 132.670 695.720 135.050 696.730 ;
        RECT 135.890 695.720 138.270 696.730 ;
        RECT 139.110 695.720 141.490 696.730 ;
        RECT 142.330 695.720 144.710 696.730 ;
        RECT 145.550 695.720 147.930 696.730 ;
        RECT 148.770 695.720 151.150 696.730 ;
        RECT 151.990 695.720 154.370 696.730 ;
        RECT 155.210 695.720 157.590 696.730 ;
        RECT 158.430 695.720 160.810 696.730 ;
        RECT 161.650 695.720 164.030 696.730 ;
        RECT 164.870 695.720 167.250 696.730 ;
        RECT 168.090 695.720 170.470 696.730 ;
        RECT 171.310 695.720 173.690 696.730 ;
        RECT 174.530 695.720 176.910 696.730 ;
        RECT 177.750 695.720 180.130 696.730 ;
        RECT 180.970 695.720 183.350 696.730 ;
        RECT 184.190 695.720 186.570 696.730 ;
        RECT 187.410 695.720 189.790 696.730 ;
        RECT 190.630 695.720 193.010 696.730 ;
        RECT 193.850 695.720 196.230 696.730 ;
        RECT 197.070 695.720 199.450 696.730 ;
        RECT 200.290 695.720 202.670 696.730 ;
        RECT 203.510 695.720 205.890 696.730 ;
        RECT 206.730 695.720 209.110 696.730 ;
        RECT 209.950 695.720 212.330 696.730 ;
        RECT 213.170 695.720 215.550 696.730 ;
        RECT 216.390 695.720 218.770 696.730 ;
        RECT 219.610 695.720 221.990 696.730 ;
        RECT 222.830 695.720 225.210 696.730 ;
        RECT 226.050 695.720 228.430 696.730 ;
        RECT 229.270 695.720 231.650 696.730 ;
        RECT 232.490 695.720 234.870 696.730 ;
        RECT 235.710 695.720 238.090 696.730 ;
        RECT 238.930 695.720 241.310 696.730 ;
        RECT 242.150 695.720 244.530 696.730 ;
        RECT 245.370 695.720 247.750 696.730 ;
        RECT 248.590 695.720 250.970 696.730 ;
        RECT 251.810 695.720 254.190 696.730 ;
        RECT 255.030 695.720 257.410 696.730 ;
        RECT 258.250 695.720 260.630 696.730 ;
        RECT 261.470 695.720 263.850 696.730 ;
        RECT 264.690 695.720 267.070 696.730 ;
        RECT 267.910 695.720 270.290 696.730 ;
        RECT 271.130 695.720 273.510 696.730 ;
        RECT 274.350 695.720 276.730 696.730 ;
        RECT 277.570 695.720 279.950 696.730 ;
        RECT 280.790 695.720 283.170 696.730 ;
        RECT 284.010 695.720 286.390 696.730 ;
        RECT 287.230 695.720 289.610 696.730 ;
        RECT 290.450 695.720 292.830 696.730 ;
        RECT 293.670 695.720 296.050 696.730 ;
        RECT 296.890 695.720 299.270 696.730 ;
        RECT 300.110 695.720 302.490 696.730 ;
        RECT 303.330 695.720 305.710 696.730 ;
        RECT 306.550 695.720 308.930 696.730 ;
        RECT 309.770 695.720 312.150 696.730 ;
        RECT 312.990 695.720 315.370 696.730 ;
        RECT 316.210 695.720 318.590 696.730 ;
        RECT 319.430 695.720 321.810 696.730 ;
        RECT 322.650 695.720 325.030 696.730 ;
        RECT 325.870 695.720 328.250 696.730 ;
        RECT 329.090 695.720 331.470 696.730 ;
        RECT 332.310 695.720 334.690 696.730 ;
        RECT 335.530 695.720 337.910 696.730 ;
        RECT 338.750 695.720 341.130 696.730 ;
        RECT 341.970 695.720 344.350 696.730 ;
        RECT 345.190 695.720 347.570 696.730 ;
        RECT 348.410 695.720 350.790 696.730 ;
        RECT 351.630 695.720 354.010 696.730 ;
        RECT 354.850 695.720 357.230 696.730 ;
        RECT 358.070 695.720 360.450 696.730 ;
        RECT 361.290 695.720 363.670 696.730 ;
        RECT 364.510 695.720 366.890 696.730 ;
        RECT 367.730 695.720 370.110 696.730 ;
        RECT 370.950 695.720 373.330 696.730 ;
        RECT 374.170 695.720 376.550 696.730 ;
        RECT 377.390 695.720 379.770 696.730 ;
        RECT 380.610 695.720 382.990 696.730 ;
        RECT 383.830 695.720 386.210 696.730 ;
        RECT 387.050 695.720 389.430 696.730 ;
        RECT 390.270 695.720 392.650 696.730 ;
        RECT 393.490 695.720 395.870 696.730 ;
        RECT 396.710 695.720 399.090 696.730 ;
        RECT 399.930 695.720 402.310 696.730 ;
        RECT 403.150 695.720 405.530 696.730 ;
        RECT 406.370 695.720 408.750 696.730 ;
        RECT 409.590 695.720 411.970 696.730 ;
        RECT 412.810 695.720 415.190 696.730 ;
        RECT 416.030 695.720 418.410 696.730 ;
        RECT 419.250 695.720 421.630 696.730 ;
        RECT 422.470 695.720 424.850 696.730 ;
        RECT 425.690 695.720 428.070 696.730 ;
        RECT 428.910 695.720 431.290 696.730 ;
        RECT 432.130 695.720 434.510 696.730 ;
        RECT 435.350 695.720 437.730 696.730 ;
        RECT 438.570 695.720 440.950 696.730 ;
        RECT 441.790 695.720 444.170 696.730 ;
        RECT 445.010 695.720 447.390 696.730 ;
        RECT 448.230 695.720 450.610 696.730 ;
        RECT 451.450 695.720 453.830 696.730 ;
        RECT 454.670 695.720 457.050 696.730 ;
        RECT 457.890 695.720 460.270 696.730 ;
        RECT 461.110 695.720 463.490 696.730 ;
        RECT 464.330 695.720 466.710 696.730 ;
        RECT 467.550 695.720 469.930 696.730 ;
        RECT 470.770 695.720 473.150 696.730 ;
        RECT 473.990 695.720 476.370 696.730 ;
        RECT 477.210 695.720 479.590 696.730 ;
        RECT 480.430 695.720 482.810 696.730 ;
        RECT 483.650 695.720 486.030 696.730 ;
        RECT 486.870 695.720 489.250 696.730 ;
        RECT 490.090 695.720 492.470 696.730 ;
        RECT 493.310 695.720 495.690 696.730 ;
        RECT 496.530 695.720 498.910 696.730 ;
        RECT 499.750 695.720 502.130 696.730 ;
        RECT 502.970 695.720 505.350 696.730 ;
        RECT 506.190 695.720 508.570 696.730 ;
        RECT 509.410 695.720 511.790 696.730 ;
        RECT 512.630 695.720 515.010 696.730 ;
        RECT 515.850 695.720 518.230 696.730 ;
        RECT 519.070 695.720 521.450 696.730 ;
        RECT 522.290 695.720 524.670 696.730 ;
        RECT 525.510 695.720 527.890 696.730 ;
        RECT 528.730 695.720 531.110 696.730 ;
        RECT 531.950 695.720 534.330 696.730 ;
        RECT 535.170 695.720 537.550 696.730 ;
        RECT 538.390 695.720 540.770 696.730 ;
        RECT 541.610 695.720 543.990 696.730 ;
        RECT 544.830 695.720 547.210 696.730 ;
        RECT 548.050 695.720 550.430 696.730 ;
        RECT 551.270 695.720 553.650 696.730 ;
        RECT 554.490 695.720 556.870 696.730 ;
        RECT 557.710 695.720 560.090 696.730 ;
        RECT 560.930 695.720 563.310 696.730 ;
        RECT 564.150 695.720 566.530 696.730 ;
        RECT 567.370 695.720 569.750 696.730 ;
        RECT 570.590 695.720 572.970 696.730 ;
        RECT 573.810 695.720 576.190 696.730 ;
        RECT 577.030 695.720 579.410 696.730 ;
        RECT 580.250 695.720 582.630 696.730 ;
        RECT 583.470 695.720 585.850 696.730 ;
        RECT 586.690 695.720 589.070 696.730 ;
        RECT 589.910 695.720 592.290 696.730 ;
        RECT 593.130 695.720 595.510 696.730 ;
        RECT 596.350 695.720 598.730 696.730 ;
        RECT 599.570 695.720 601.950 696.730 ;
        RECT 602.790 695.720 605.170 696.730 ;
        RECT 606.010 695.720 608.390 696.730 ;
        RECT 609.230 695.720 611.610 696.730 ;
        RECT 612.450 695.720 614.830 696.730 ;
        RECT 615.670 695.720 618.050 696.730 ;
        RECT 618.890 695.720 621.270 696.730 ;
        RECT 622.110 695.720 624.490 696.730 ;
        RECT 625.330 695.720 627.710 696.730 ;
        RECT 628.550 695.720 630.930 696.730 ;
        RECT 631.770 695.720 634.150 696.730 ;
        RECT 634.990 695.720 637.370 696.730 ;
        RECT 638.210 695.720 640.590 696.730 ;
        RECT 641.430 695.720 643.810 696.730 ;
        RECT 644.650 695.720 647.030 696.730 ;
        RECT 647.870 695.720 650.250 696.730 ;
        RECT 651.090 695.720 653.470 696.730 ;
        RECT 654.310 695.720 656.690 696.730 ;
        RECT 657.530 695.720 659.910 696.730 ;
        RECT 660.750 695.720 663.130 696.730 ;
        RECT 663.970 695.720 699.100 696.730 ;
        RECT 0.370 4.280 699.100 695.720 ;
        RECT 0.370 0.155 51.330 4.280 ;
        RECT 52.170 0.155 54.550 4.280 ;
        RECT 55.390 0.155 57.770 4.280 ;
        RECT 58.610 0.155 60.990 4.280 ;
        RECT 61.830 0.155 64.210 4.280 ;
        RECT 65.050 0.155 67.430 4.280 ;
        RECT 68.270 0.155 70.650 4.280 ;
        RECT 71.490 0.155 73.870 4.280 ;
        RECT 74.710 0.155 77.090 4.280 ;
        RECT 77.930 0.155 80.310 4.280 ;
        RECT 81.150 0.155 83.530 4.280 ;
        RECT 84.370 0.155 86.750 4.280 ;
        RECT 87.590 0.155 89.970 4.280 ;
        RECT 90.810 0.155 93.190 4.280 ;
        RECT 94.030 0.155 96.410 4.280 ;
        RECT 97.250 0.155 99.630 4.280 ;
        RECT 100.470 0.155 102.850 4.280 ;
        RECT 103.690 0.155 106.070 4.280 ;
        RECT 106.910 0.155 109.290 4.280 ;
        RECT 110.130 0.155 112.510 4.280 ;
        RECT 113.350 0.155 115.730 4.280 ;
        RECT 116.570 0.155 118.950 4.280 ;
        RECT 119.790 0.155 122.170 4.280 ;
        RECT 123.010 0.155 125.390 4.280 ;
        RECT 126.230 0.155 128.610 4.280 ;
        RECT 129.450 0.155 131.830 4.280 ;
        RECT 132.670 0.155 135.050 4.280 ;
        RECT 135.890 0.155 138.270 4.280 ;
        RECT 139.110 0.155 141.490 4.280 ;
        RECT 142.330 0.155 144.710 4.280 ;
        RECT 145.550 0.155 147.930 4.280 ;
        RECT 148.770 0.155 151.150 4.280 ;
        RECT 151.990 0.155 154.370 4.280 ;
        RECT 155.210 0.155 157.590 4.280 ;
        RECT 158.430 0.155 160.810 4.280 ;
        RECT 161.650 0.155 164.030 4.280 ;
        RECT 164.870 0.155 167.250 4.280 ;
        RECT 168.090 0.155 170.470 4.280 ;
        RECT 171.310 0.155 173.690 4.280 ;
        RECT 174.530 0.155 176.910 4.280 ;
        RECT 177.750 0.155 180.130 4.280 ;
        RECT 180.970 0.155 183.350 4.280 ;
        RECT 184.190 0.155 186.570 4.280 ;
        RECT 187.410 0.155 189.790 4.280 ;
        RECT 190.630 0.155 193.010 4.280 ;
        RECT 193.850 0.155 196.230 4.280 ;
        RECT 197.070 0.155 199.450 4.280 ;
        RECT 200.290 0.155 202.670 4.280 ;
        RECT 203.510 0.155 205.890 4.280 ;
        RECT 206.730 0.155 209.110 4.280 ;
        RECT 209.950 0.155 212.330 4.280 ;
        RECT 213.170 0.155 215.550 4.280 ;
        RECT 216.390 0.155 218.770 4.280 ;
        RECT 219.610 0.155 221.990 4.280 ;
        RECT 222.830 0.155 225.210 4.280 ;
        RECT 226.050 0.155 228.430 4.280 ;
        RECT 229.270 0.155 231.650 4.280 ;
        RECT 232.490 0.155 234.870 4.280 ;
        RECT 235.710 0.155 238.090 4.280 ;
        RECT 238.930 0.155 241.310 4.280 ;
        RECT 242.150 0.155 244.530 4.280 ;
        RECT 245.370 0.155 247.750 4.280 ;
        RECT 248.590 0.155 250.970 4.280 ;
        RECT 251.810 0.155 254.190 4.280 ;
        RECT 255.030 0.155 257.410 4.280 ;
        RECT 258.250 0.155 260.630 4.280 ;
        RECT 261.470 0.155 263.850 4.280 ;
        RECT 264.690 0.155 267.070 4.280 ;
        RECT 267.910 0.155 270.290 4.280 ;
        RECT 271.130 0.155 273.510 4.280 ;
        RECT 274.350 0.155 276.730 4.280 ;
        RECT 277.570 0.155 279.950 4.280 ;
        RECT 280.790 0.155 283.170 4.280 ;
        RECT 284.010 0.155 286.390 4.280 ;
        RECT 287.230 0.155 289.610 4.280 ;
        RECT 290.450 0.155 292.830 4.280 ;
        RECT 293.670 0.155 296.050 4.280 ;
        RECT 296.890 0.155 299.270 4.280 ;
        RECT 300.110 0.155 302.490 4.280 ;
        RECT 303.330 0.155 305.710 4.280 ;
        RECT 306.550 0.155 308.930 4.280 ;
        RECT 309.770 0.155 312.150 4.280 ;
        RECT 312.990 0.155 315.370 4.280 ;
        RECT 316.210 0.155 318.590 4.280 ;
        RECT 319.430 0.155 321.810 4.280 ;
        RECT 322.650 0.155 325.030 4.280 ;
        RECT 325.870 0.155 328.250 4.280 ;
        RECT 329.090 0.155 331.470 4.280 ;
        RECT 332.310 0.155 334.690 4.280 ;
        RECT 335.530 0.155 337.910 4.280 ;
        RECT 338.750 0.155 341.130 4.280 ;
        RECT 341.970 0.155 344.350 4.280 ;
        RECT 345.190 0.155 347.570 4.280 ;
        RECT 348.410 0.155 350.790 4.280 ;
        RECT 351.630 0.155 354.010 4.280 ;
        RECT 354.850 0.155 357.230 4.280 ;
        RECT 358.070 0.155 360.450 4.280 ;
        RECT 361.290 0.155 363.670 4.280 ;
        RECT 364.510 0.155 366.890 4.280 ;
        RECT 367.730 0.155 370.110 4.280 ;
        RECT 370.950 0.155 373.330 4.280 ;
        RECT 374.170 0.155 376.550 4.280 ;
        RECT 377.390 0.155 379.770 4.280 ;
        RECT 380.610 0.155 382.990 4.280 ;
        RECT 383.830 0.155 386.210 4.280 ;
        RECT 387.050 0.155 389.430 4.280 ;
        RECT 390.270 0.155 392.650 4.280 ;
        RECT 393.490 0.155 395.870 4.280 ;
        RECT 396.710 0.155 399.090 4.280 ;
        RECT 399.930 0.155 402.310 4.280 ;
        RECT 403.150 0.155 405.530 4.280 ;
        RECT 406.370 0.155 408.750 4.280 ;
        RECT 409.590 0.155 411.970 4.280 ;
        RECT 412.810 0.155 415.190 4.280 ;
        RECT 416.030 0.155 418.410 4.280 ;
        RECT 419.250 0.155 421.630 4.280 ;
        RECT 422.470 0.155 424.850 4.280 ;
        RECT 425.690 0.155 428.070 4.280 ;
        RECT 428.910 0.155 431.290 4.280 ;
        RECT 432.130 0.155 434.510 4.280 ;
        RECT 435.350 0.155 437.730 4.280 ;
        RECT 438.570 0.155 440.950 4.280 ;
        RECT 441.790 0.155 444.170 4.280 ;
        RECT 445.010 0.155 447.390 4.280 ;
        RECT 448.230 0.155 450.610 4.280 ;
        RECT 451.450 0.155 453.830 4.280 ;
        RECT 454.670 0.155 457.050 4.280 ;
        RECT 457.890 0.155 460.270 4.280 ;
        RECT 461.110 0.155 463.490 4.280 ;
        RECT 464.330 0.155 466.710 4.280 ;
        RECT 467.550 0.155 469.930 4.280 ;
        RECT 470.770 0.155 473.150 4.280 ;
        RECT 473.990 0.155 476.370 4.280 ;
        RECT 477.210 0.155 479.590 4.280 ;
        RECT 480.430 0.155 482.810 4.280 ;
        RECT 483.650 0.155 486.030 4.280 ;
        RECT 486.870 0.155 489.250 4.280 ;
        RECT 490.090 0.155 492.470 4.280 ;
        RECT 493.310 0.155 495.690 4.280 ;
        RECT 496.530 0.155 498.910 4.280 ;
        RECT 499.750 0.155 502.130 4.280 ;
        RECT 502.970 0.155 505.350 4.280 ;
        RECT 506.190 0.155 508.570 4.280 ;
        RECT 509.410 0.155 511.790 4.280 ;
        RECT 512.630 0.155 515.010 4.280 ;
        RECT 515.850 0.155 518.230 4.280 ;
        RECT 519.070 0.155 521.450 4.280 ;
        RECT 522.290 0.155 524.670 4.280 ;
        RECT 525.510 0.155 527.890 4.280 ;
        RECT 528.730 0.155 531.110 4.280 ;
        RECT 531.950 0.155 534.330 4.280 ;
        RECT 535.170 0.155 537.550 4.280 ;
        RECT 538.390 0.155 540.770 4.280 ;
        RECT 541.610 0.155 543.990 4.280 ;
        RECT 544.830 0.155 547.210 4.280 ;
        RECT 548.050 0.155 550.430 4.280 ;
        RECT 551.270 0.155 553.650 4.280 ;
        RECT 554.490 0.155 556.870 4.280 ;
        RECT 557.710 0.155 560.090 4.280 ;
        RECT 560.930 0.155 563.310 4.280 ;
        RECT 564.150 0.155 566.530 4.280 ;
        RECT 567.370 0.155 569.750 4.280 ;
        RECT 570.590 0.155 572.970 4.280 ;
        RECT 573.810 0.155 576.190 4.280 ;
        RECT 577.030 0.155 579.410 4.280 ;
        RECT 580.250 0.155 582.630 4.280 ;
        RECT 583.470 0.155 585.850 4.280 ;
        RECT 586.690 0.155 589.070 4.280 ;
        RECT 589.910 0.155 592.290 4.280 ;
        RECT 593.130 0.155 595.510 4.280 ;
        RECT 596.350 0.155 598.730 4.280 ;
        RECT 599.570 0.155 601.950 4.280 ;
        RECT 602.790 0.155 605.170 4.280 ;
        RECT 606.010 0.155 608.390 4.280 ;
        RECT 609.230 0.155 611.610 4.280 ;
        RECT 612.450 0.155 614.830 4.280 ;
        RECT 615.670 0.155 618.050 4.280 ;
        RECT 618.890 0.155 621.270 4.280 ;
        RECT 622.110 0.155 624.490 4.280 ;
        RECT 625.330 0.155 627.710 4.280 ;
        RECT 628.550 0.155 630.930 4.280 ;
        RECT 631.770 0.155 634.150 4.280 ;
        RECT 634.990 0.155 637.370 4.280 ;
        RECT 638.210 0.155 640.590 4.280 ;
        RECT 641.430 0.155 643.810 4.280 ;
        RECT 644.650 0.155 647.030 4.280 ;
        RECT 647.870 0.155 650.250 4.280 ;
        RECT 651.090 0.155 653.470 4.280 ;
        RECT 654.310 0.155 656.690 4.280 ;
        RECT 657.530 0.155 659.910 4.280 ;
        RECT 660.750 0.155 663.130 4.280 ;
        RECT 663.970 0.155 666.350 4.280 ;
        RECT 667.190 0.155 669.570 4.280 ;
        RECT 670.410 0.155 672.790 4.280 ;
        RECT 673.630 0.155 676.010 4.280 ;
        RECT 676.850 0.155 679.230 4.280 ;
        RECT 680.070 0.155 682.450 4.280 ;
        RECT 683.290 0.155 685.670 4.280 ;
        RECT 686.510 0.155 688.890 4.280 ;
        RECT 689.730 0.155 692.110 4.280 ;
        RECT 692.950 0.155 695.330 4.280 ;
        RECT 696.170 0.155 698.550 4.280 ;
      LAYER met3 ;
        RECT 3.950 647.040 696.000 688.325 ;
        RECT 3.950 645.640 695.600 647.040 ;
        RECT 3.950 643.640 696.000 645.640 ;
        RECT 3.950 642.240 695.600 643.640 ;
        RECT 3.950 640.240 696.000 642.240 ;
        RECT 4.400 638.840 695.600 640.240 ;
        RECT 3.950 636.840 696.000 638.840 ;
        RECT 4.400 635.440 695.600 636.840 ;
        RECT 3.950 633.440 696.000 635.440 ;
        RECT 4.400 632.040 695.600 633.440 ;
        RECT 3.950 630.040 696.000 632.040 ;
        RECT 4.400 628.640 695.600 630.040 ;
        RECT 3.950 626.640 696.000 628.640 ;
        RECT 4.400 625.240 695.600 626.640 ;
        RECT 3.950 623.240 696.000 625.240 ;
        RECT 4.400 621.840 695.600 623.240 ;
        RECT 3.950 619.840 696.000 621.840 ;
        RECT 4.400 618.440 695.600 619.840 ;
        RECT 3.950 616.440 696.000 618.440 ;
        RECT 4.400 615.040 695.600 616.440 ;
        RECT 3.950 613.040 696.000 615.040 ;
        RECT 4.400 611.640 695.600 613.040 ;
        RECT 3.950 609.640 696.000 611.640 ;
        RECT 4.400 608.240 695.600 609.640 ;
        RECT 3.950 606.240 696.000 608.240 ;
        RECT 4.400 604.840 695.600 606.240 ;
        RECT 3.950 602.840 696.000 604.840 ;
        RECT 4.400 601.440 695.600 602.840 ;
        RECT 3.950 599.440 696.000 601.440 ;
        RECT 4.400 598.040 695.600 599.440 ;
        RECT 3.950 596.040 696.000 598.040 ;
        RECT 4.400 594.640 695.600 596.040 ;
        RECT 3.950 592.640 696.000 594.640 ;
        RECT 4.400 591.240 695.600 592.640 ;
        RECT 3.950 589.240 696.000 591.240 ;
        RECT 4.400 587.840 695.600 589.240 ;
        RECT 3.950 585.840 696.000 587.840 ;
        RECT 4.400 584.440 695.600 585.840 ;
        RECT 3.950 582.440 696.000 584.440 ;
        RECT 4.400 581.040 695.600 582.440 ;
        RECT 3.950 579.040 696.000 581.040 ;
        RECT 4.400 577.640 695.600 579.040 ;
        RECT 3.950 575.640 696.000 577.640 ;
        RECT 4.400 574.240 695.600 575.640 ;
        RECT 3.950 572.240 696.000 574.240 ;
        RECT 4.400 570.840 695.600 572.240 ;
        RECT 3.950 568.840 696.000 570.840 ;
        RECT 4.400 567.440 695.600 568.840 ;
        RECT 3.950 565.440 696.000 567.440 ;
        RECT 4.400 564.040 695.600 565.440 ;
        RECT 3.950 562.040 696.000 564.040 ;
        RECT 4.400 560.640 695.600 562.040 ;
        RECT 3.950 558.640 696.000 560.640 ;
        RECT 4.400 557.240 695.600 558.640 ;
        RECT 3.950 555.240 696.000 557.240 ;
        RECT 4.400 553.840 695.600 555.240 ;
        RECT 3.950 551.840 696.000 553.840 ;
        RECT 4.400 550.440 695.600 551.840 ;
        RECT 3.950 548.440 696.000 550.440 ;
        RECT 4.400 547.040 695.600 548.440 ;
        RECT 3.950 545.040 696.000 547.040 ;
        RECT 4.400 543.640 695.600 545.040 ;
        RECT 3.950 541.640 696.000 543.640 ;
        RECT 4.400 540.240 695.600 541.640 ;
        RECT 3.950 538.240 696.000 540.240 ;
        RECT 4.400 536.840 695.600 538.240 ;
        RECT 3.950 534.840 696.000 536.840 ;
        RECT 4.400 533.440 695.600 534.840 ;
        RECT 3.950 531.440 696.000 533.440 ;
        RECT 4.400 530.040 695.600 531.440 ;
        RECT 3.950 528.040 696.000 530.040 ;
        RECT 4.400 526.640 695.600 528.040 ;
        RECT 3.950 524.640 696.000 526.640 ;
        RECT 4.400 523.240 695.600 524.640 ;
        RECT 3.950 521.240 696.000 523.240 ;
        RECT 4.400 519.840 695.600 521.240 ;
        RECT 3.950 517.840 696.000 519.840 ;
        RECT 4.400 516.440 695.600 517.840 ;
        RECT 3.950 514.440 696.000 516.440 ;
        RECT 4.400 513.040 695.600 514.440 ;
        RECT 3.950 511.040 696.000 513.040 ;
        RECT 4.400 509.640 695.600 511.040 ;
        RECT 3.950 507.640 696.000 509.640 ;
        RECT 4.400 506.240 695.600 507.640 ;
        RECT 3.950 504.240 696.000 506.240 ;
        RECT 4.400 502.840 695.600 504.240 ;
        RECT 3.950 500.840 696.000 502.840 ;
        RECT 4.400 499.440 695.600 500.840 ;
        RECT 3.950 497.440 696.000 499.440 ;
        RECT 4.400 496.040 695.600 497.440 ;
        RECT 3.950 494.040 696.000 496.040 ;
        RECT 4.400 492.640 695.600 494.040 ;
        RECT 3.950 490.640 696.000 492.640 ;
        RECT 4.400 489.240 695.600 490.640 ;
        RECT 3.950 487.240 696.000 489.240 ;
        RECT 4.400 485.840 695.600 487.240 ;
        RECT 3.950 483.840 696.000 485.840 ;
        RECT 4.400 482.440 695.600 483.840 ;
        RECT 3.950 480.440 696.000 482.440 ;
        RECT 4.400 479.040 695.600 480.440 ;
        RECT 3.950 477.040 696.000 479.040 ;
        RECT 4.400 475.640 695.600 477.040 ;
        RECT 3.950 473.640 696.000 475.640 ;
        RECT 4.400 472.240 695.600 473.640 ;
        RECT 3.950 470.240 696.000 472.240 ;
        RECT 4.400 468.840 695.600 470.240 ;
        RECT 3.950 466.840 696.000 468.840 ;
        RECT 4.400 465.440 695.600 466.840 ;
        RECT 3.950 463.440 696.000 465.440 ;
        RECT 4.400 462.040 695.600 463.440 ;
        RECT 3.950 460.040 696.000 462.040 ;
        RECT 4.400 458.640 695.600 460.040 ;
        RECT 3.950 456.640 696.000 458.640 ;
        RECT 4.400 455.240 695.600 456.640 ;
        RECT 3.950 453.240 696.000 455.240 ;
        RECT 4.400 451.840 695.600 453.240 ;
        RECT 3.950 449.840 696.000 451.840 ;
        RECT 4.400 448.440 695.600 449.840 ;
        RECT 3.950 446.440 696.000 448.440 ;
        RECT 4.400 445.040 695.600 446.440 ;
        RECT 3.950 443.040 696.000 445.040 ;
        RECT 4.400 441.640 695.600 443.040 ;
        RECT 3.950 439.640 696.000 441.640 ;
        RECT 4.400 438.240 695.600 439.640 ;
        RECT 3.950 436.240 696.000 438.240 ;
        RECT 4.400 434.840 695.600 436.240 ;
        RECT 3.950 432.840 696.000 434.840 ;
        RECT 4.400 431.440 695.600 432.840 ;
        RECT 3.950 429.440 696.000 431.440 ;
        RECT 4.400 428.040 695.600 429.440 ;
        RECT 3.950 426.040 696.000 428.040 ;
        RECT 4.400 424.640 695.600 426.040 ;
        RECT 3.950 422.640 696.000 424.640 ;
        RECT 4.400 421.240 695.600 422.640 ;
        RECT 3.950 419.240 696.000 421.240 ;
        RECT 4.400 417.840 695.600 419.240 ;
        RECT 3.950 415.840 696.000 417.840 ;
        RECT 4.400 414.440 695.600 415.840 ;
        RECT 3.950 412.440 696.000 414.440 ;
        RECT 4.400 411.040 695.600 412.440 ;
        RECT 3.950 409.040 696.000 411.040 ;
        RECT 4.400 407.640 695.600 409.040 ;
        RECT 3.950 405.640 696.000 407.640 ;
        RECT 4.400 404.240 695.600 405.640 ;
        RECT 3.950 402.240 696.000 404.240 ;
        RECT 4.400 400.840 695.600 402.240 ;
        RECT 3.950 398.840 696.000 400.840 ;
        RECT 4.400 397.440 695.600 398.840 ;
        RECT 3.950 395.440 696.000 397.440 ;
        RECT 4.400 394.040 695.600 395.440 ;
        RECT 3.950 392.040 696.000 394.040 ;
        RECT 4.400 390.640 695.600 392.040 ;
        RECT 3.950 388.640 696.000 390.640 ;
        RECT 4.400 387.240 695.600 388.640 ;
        RECT 3.950 385.240 696.000 387.240 ;
        RECT 4.400 383.840 695.600 385.240 ;
        RECT 3.950 381.840 696.000 383.840 ;
        RECT 4.400 380.440 695.600 381.840 ;
        RECT 3.950 378.440 696.000 380.440 ;
        RECT 4.400 377.040 695.600 378.440 ;
        RECT 3.950 375.040 696.000 377.040 ;
        RECT 4.400 373.640 695.600 375.040 ;
        RECT 3.950 371.640 696.000 373.640 ;
        RECT 4.400 370.240 695.600 371.640 ;
        RECT 3.950 368.240 696.000 370.240 ;
        RECT 4.400 366.840 695.600 368.240 ;
        RECT 3.950 364.840 696.000 366.840 ;
        RECT 4.400 363.440 695.600 364.840 ;
        RECT 3.950 361.440 696.000 363.440 ;
        RECT 4.400 360.040 695.600 361.440 ;
        RECT 3.950 358.040 696.000 360.040 ;
        RECT 4.400 356.640 695.600 358.040 ;
        RECT 3.950 354.640 696.000 356.640 ;
        RECT 4.400 353.240 695.600 354.640 ;
        RECT 3.950 351.240 696.000 353.240 ;
        RECT 4.400 349.840 695.600 351.240 ;
        RECT 3.950 347.840 696.000 349.840 ;
        RECT 4.400 346.440 695.600 347.840 ;
        RECT 3.950 344.440 696.000 346.440 ;
        RECT 4.400 343.040 695.600 344.440 ;
        RECT 3.950 341.040 696.000 343.040 ;
        RECT 4.400 339.640 695.600 341.040 ;
        RECT 3.950 337.640 696.000 339.640 ;
        RECT 4.400 336.240 695.600 337.640 ;
        RECT 3.950 334.240 696.000 336.240 ;
        RECT 4.400 332.840 695.600 334.240 ;
        RECT 3.950 330.840 696.000 332.840 ;
        RECT 4.400 329.440 695.600 330.840 ;
        RECT 3.950 327.440 696.000 329.440 ;
        RECT 4.400 326.040 695.600 327.440 ;
        RECT 3.950 324.040 696.000 326.040 ;
        RECT 4.400 322.640 695.600 324.040 ;
        RECT 3.950 320.640 696.000 322.640 ;
        RECT 4.400 319.240 695.600 320.640 ;
        RECT 3.950 317.240 696.000 319.240 ;
        RECT 4.400 315.840 695.600 317.240 ;
        RECT 3.950 313.840 696.000 315.840 ;
        RECT 4.400 312.440 695.600 313.840 ;
        RECT 3.950 310.440 696.000 312.440 ;
        RECT 4.400 309.040 695.600 310.440 ;
        RECT 3.950 307.040 696.000 309.040 ;
        RECT 4.400 305.640 695.600 307.040 ;
        RECT 3.950 303.640 696.000 305.640 ;
        RECT 4.400 302.240 695.600 303.640 ;
        RECT 3.950 300.240 696.000 302.240 ;
        RECT 4.400 298.840 695.600 300.240 ;
        RECT 3.950 296.840 696.000 298.840 ;
        RECT 4.400 295.440 695.600 296.840 ;
        RECT 3.950 293.440 696.000 295.440 ;
        RECT 4.400 292.040 695.600 293.440 ;
        RECT 3.950 290.040 696.000 292.040 ;
        RECT 4.400 288.640 695.600 290.040 ;
        RECT 3.950 286.640 696.000 288.640 ;
        RECT 4.400 285.240 695.600 286.640 ;
        RECT 3.950 283.240 696.000 285.240 ;
        RECT 4.400 281.840 695.600 283.240 ;
        RECT 3.950 279.840 696.000 281.840 ;
        RECT 4.400 278.440 695.600 279.840 ;
        RECT 3.950 276.440 696.000 278.440 ;
        RECT 4.400 275.040 695.600 276.440 ;
        RECT 3.950 273.040 696.000 275.040 ;
        RECT 4.400 271.640 695.600 273.040 ;
        RECT 3.950 269.640 696.000 271.640 ;
        RECT 4.400 268.240 695.600 269.640 ;
        RECT 3.950 266.240 696.000 268.240 ;
        RECT 4.400 264.840 695.600 266.240 ;
        RECT 3.950 262.840 696.000 264.840 ;
        RECT 4.400 261.440 695.600 262.840 ;
        RECT 3.950 259.440 696.000 261.440 ;
        RECT 4.400 258.040 695.600 259.440 ;
        RECT 3.950 256.040 696.000 258.040 ;
        RECT 4.400 254.640 695.600 256.040 ;
        RECT 3.950 252.640 696.000 254.640 ;
        RECT 4.400 251.240 695.600 252.640 ;
        RECT 3.950 249.240 696.000 251.240 ;
        RECT 4.400 247.840 695.600 249.240 ;
        RECT 3.950 245.840 696.000 247.840 ;
        RECT 4.400 244.440 695.600 245.840 ;
        RECT 3.950 242.440 696.000 244.440 ;
        RECT 4.400 241.040 695.600 242.440 ;
        RECT 3.950 239.040 696.000 241.040 ;
        RECT 4.400 237.640 695.600 239.040 ;
        RECT 3.950 235.640 696.000 237.640 ;
        RECT 4.400 234.240 695.600 235.640 ;
        RECT 3.950 232.240 696.000 234.240 ;
        RECT 4.400 230.840 695.600 232.240 ;
        RECT 3.950 228.840 696.000 230.840 ;
        RECT 4.400 227.440 695.600 228.840 ;
        RECT 3.950 225.440 696.000 227.440 ;
        RECT 4.400 224.040 695.600 225.440 ;
        RECT 3.950 222.040 696.000 224.040 ;
        RECT 4.400 220.640 695.600 222.040 ;
        RECT 3.950 218.640 696.000 220.640 ;
        RECT 4.400 217.240 695.600 218.640 ;
        RECT 3.950 215.240 696.000 217.240 ;
        RECT 4.400 213.840 695.600 215.240 ;
        RECT 3.950 211.840 696.000 213.840 ;
        RECT 4.400 210.440 695.600 211.840 ;
        RECT 3.950 208.440 696.000 210.440 ;
        RECT 4.400 207.040 695.600 208.440 ;
        RECT 3.950 205.040 696.000 207.040 ;
        RECT 4.400 203.640 695.600 205.040 ;
        RECT 3.950 201.640 696.000 203.640 ;
        RECT 4.400 200.240 695.600 201.640 ;
        RECT 3.950 198.240 696.000 200.240 ;
        RECT 4.400 196.840 695.600 198.240 ;
        RECT 3.950 194.840 696.000 196.840 ;
        RECT 4.400 193.440 695.600 194.840 ;
        RECT 3.950 191.440 696.000 193.440 ;
        RECT 4.400 190.040 695.600 191.440 ;
        RECT 3.950 188.040 696.000 190.040 ;
        RECT 4.400 186.640 695.600 188.040 ;
        RECT 3.950 184.640 696.000 186.640 ;
        RECT 4.400 183.240 695.600 184.640 ;
        RECT 3.950 181.240 696.000 183.240 ;
        RECT 4.400 179.840 695.600 181.240 ;
        RECT 3.950 177.840 696.000 179.840 ;
        RECT 4.400 176.440 695.600 177.840 ;
        RECT 3.950 174.440 696.000 176.440 ;
        RECT 4.400 173.040 695.600 174.440 ;
        RECT 3.950 171.040 696.000 173.040 ;
        RECT 4.400 169.640 695.600 171.040 ;
        RECT 3.950 167.640 696.000 169.640 ;
        RECT 4.400 166.240 695.600 167.640 ;
        RECT 3.950 164.240 696.000 166.240 ;
        RECT 4.400 162.840 695.600 164.240 ;
        RECT 3.950 160.840 696.000 162.840 ;
        RECT 4.400 159.440 695.600 160.840 ;
        RECT 3.950 157.440 696.000 159.440 ;
        RECT 4.400 156.040 695.600 157.440 ;
        RECT 3.950 154.040 696.000 156.040 ;
        RECT 4.400 152.640 695.600 154.040 ;
        RECT 3.950 150.640 696.000 152.640 ;
        RECT 4.400 149.240 695.600 150.640 ;
        RECT 3.950 147.240 696.000 149.240 ;
        RECT 4.400 145.840 695.600 147.240 ;
        RECT 3.950 143.840 696.000 145.840 ;
        RECT 4.400 142.440 695.600 143.840 ;
        RECT 3.950 140.440 696.000 142.440 ;
        RECT 4.400 139.040 695.600 140.440 ;
        RECT 3.950 137.040 696.000 139.040 ;
        RECT 4.400 135.640 695.600 137.040 ;
        RECT 3.950 133.640 696.000 135.640 ;
        RECT 4.400 132.240 695.600 133.640 ;
        RECT 3.950 130.240 696.000 132.240 ;
        RECT 4.400 128.840 695.600 130.240 ;
        RECT 3.950 126.840 696.000 128.840 ;
        RECT 4.400 125.440 695.600 126.840 ;
        RECT 3.950 123.440 696.000 125.440 ;
        RECT 4.400 122.040 695.600 123.440 ;
        RECT 3.950 120.040 696.000 122.040 ;
        RECT 4.400 118.640 695.600 120.040 ;
        RECT 3.950 116.640 696.000 118.640 ;
        RECT 4.400 115.240 695.600 116.640 ;
        RECT 3.950 113.240 696.000 115.240 ;
        RECT 4.400 111.840 695.600 113.240 ;
        RECT 3.950 109.840 696.000 111.840 ;
        RECT 4.400 108.440 695.600 109.840 ;
        RECT 3.950 106.440 696.000 108.440 ;
        RECT 3.950 105.040 695.600 106.440 ;
        RECT 3.950 103.040 696.000 105.040 ;
        RECT 3.950 101.640 695.600 103.040 ;
        RECT 3.950 99.640 696.000 101.640 ;
        RECT 3.950 98.240 695.600 99.640 ;
        RECT 3.950 96.240 696.000 98.240 ;
        RECT 3.950 94.840 695.600 96.240 ;
        RECT 3.950 92.840 696.000 94.840 ;
        RECT 3.950 91.440 695.600 92.840 ;
        RECT 3.950 89.440 696.000 91.440 ;
        RECT 3.950 88.040 695.600 89.440 ;
        RECT 3.950 86.040 696.000 88.040 ;
        RECT 3.950 84.640 695.600 86.040 ;
        RECT 3.950 82.640 696.000 84.640 ;
        RECT 3.950 81.240 695.600 82.640 ;
        RECT 3.950 79.240 696.000 81.240 ;
        RECT 3.950 77.840 695.600 79.240 ;
        RECT 3.950 75.840 696.000 77.840 ;
        RECT 3.950 74.440 695.600 75.840 ;
        RECT 3.950 72.440 696.000 74.440 ;
        RECT 3.950 71.040 695.600 72.440 ;
        RECT 3.950 69.040 696.000 71.040 ;
        RECT 3.950 67.640 695.600 69.040 ;
        RECT 3.950 65.640 696.000 67.640 ;
        RECT 3.950 64.240 695.600 65.640 ;
        RECT 3.950 62.240 696.000 64.240 ;
        RECT 3.950 60.840 695.600 62.240 ;
        RECT 3.950 58.840 696.000 60.840 ;
        RECT 3.950 57.440 695.600 58.840 ;
        RECT 3.950 55.440 696.000 57.440 ;
        RECT 3.950 54.040 695.600 55.440 ;
        RECT 3.950 52.040 696.000 54.040 ;
        RECT 3.950 50.640 695.600 52.040 ;
        RECT 3.950 48.640 696.000 50.640 ;
        RECT 3.950 47.240 695.600 48.640 ;
        RECT 3.950 45.240 696.000 47.240 ;
        RECT 3.950 43.840 695.600 45.240 ;
        RECT 3.950 41.840 696.000 43.840 ;
        RECT 3.950 40.440 695.600 41.840 ;
        RECT 3.950 38.440 696.000 40.440 ;
        RECT 3.950 37.040 695.600 38.440 ;
        RECT 3.950 35.040 696.000 37.040 ;
        RECT 3.950 33.640 695.600 35.040 ;
        RECT 3.950 31.640 696.000 33.640 ;
        RECT 3.950 30.240 695.600 31.640 ;
        RECT 3.950 28.240 696.000 30.240 ;
        RECT 3.950 26.840 695.600 28.240 ;
        RECT 3.950 24.840 696.000 26.840 ;
        RECT 3.950 23.440 695.600 24.840 ;
        RECT 3.950 21.440 696.000 23.440 ;
        RECT 3.950 20.040 695.600 21.440 ;
        RECT 3.950 18.040 696.000 20.040 ;
        RECT 3.950 16.640 695.600 18.040 ;
        RECT 3.950 14.640 696.000 16.640 ;
        RECT 3.950 13.240 695.600 14.640 ;
        RECT 3.950 11.240 696.000 13.240 ;
        RECT 3.950 9.840 695.600 11.240 ;
        RECT 3.950 7.840 696.000 9.840 ;
        RECT 3.950 6.440 695.600 7.840 ;
        RECT 3.950 4.440 696.000 6.440 ;
        RECT 3.950 3.040 695.600 4.440 ;
        RECT 3.950 1.040 696.000 3.040 ;
        RECT 3.950 0.175 695.600 1.040 ;
      LAYER met4 ;
        RECT 3.975 12.415 20.640 670.305 ;
        RECT 23.040 12.415 23.940 670.305 ;
        RECT 26.340 12.415 174.240 670.305 ;
        RECT 176.640 12.415 177.540 670.305 ;
        RECT 179.940 12.415 327.840 670.305 ;
        RECT 330.240 12.415 331.140 670.305 ;
        RECT 333.540 12.415 481.440 670.305 ;
        RECT 483.840 12.415 484.740 670.305 ;
        RECT 487.140 12.415 635.040 670.305 ;
        RECT 637.440 12.415 638.340 670.305 ;
        RECT 640.740 12.415 689.705 670.305 ;
  END
END tinyjambu_core
END LIBRARY

